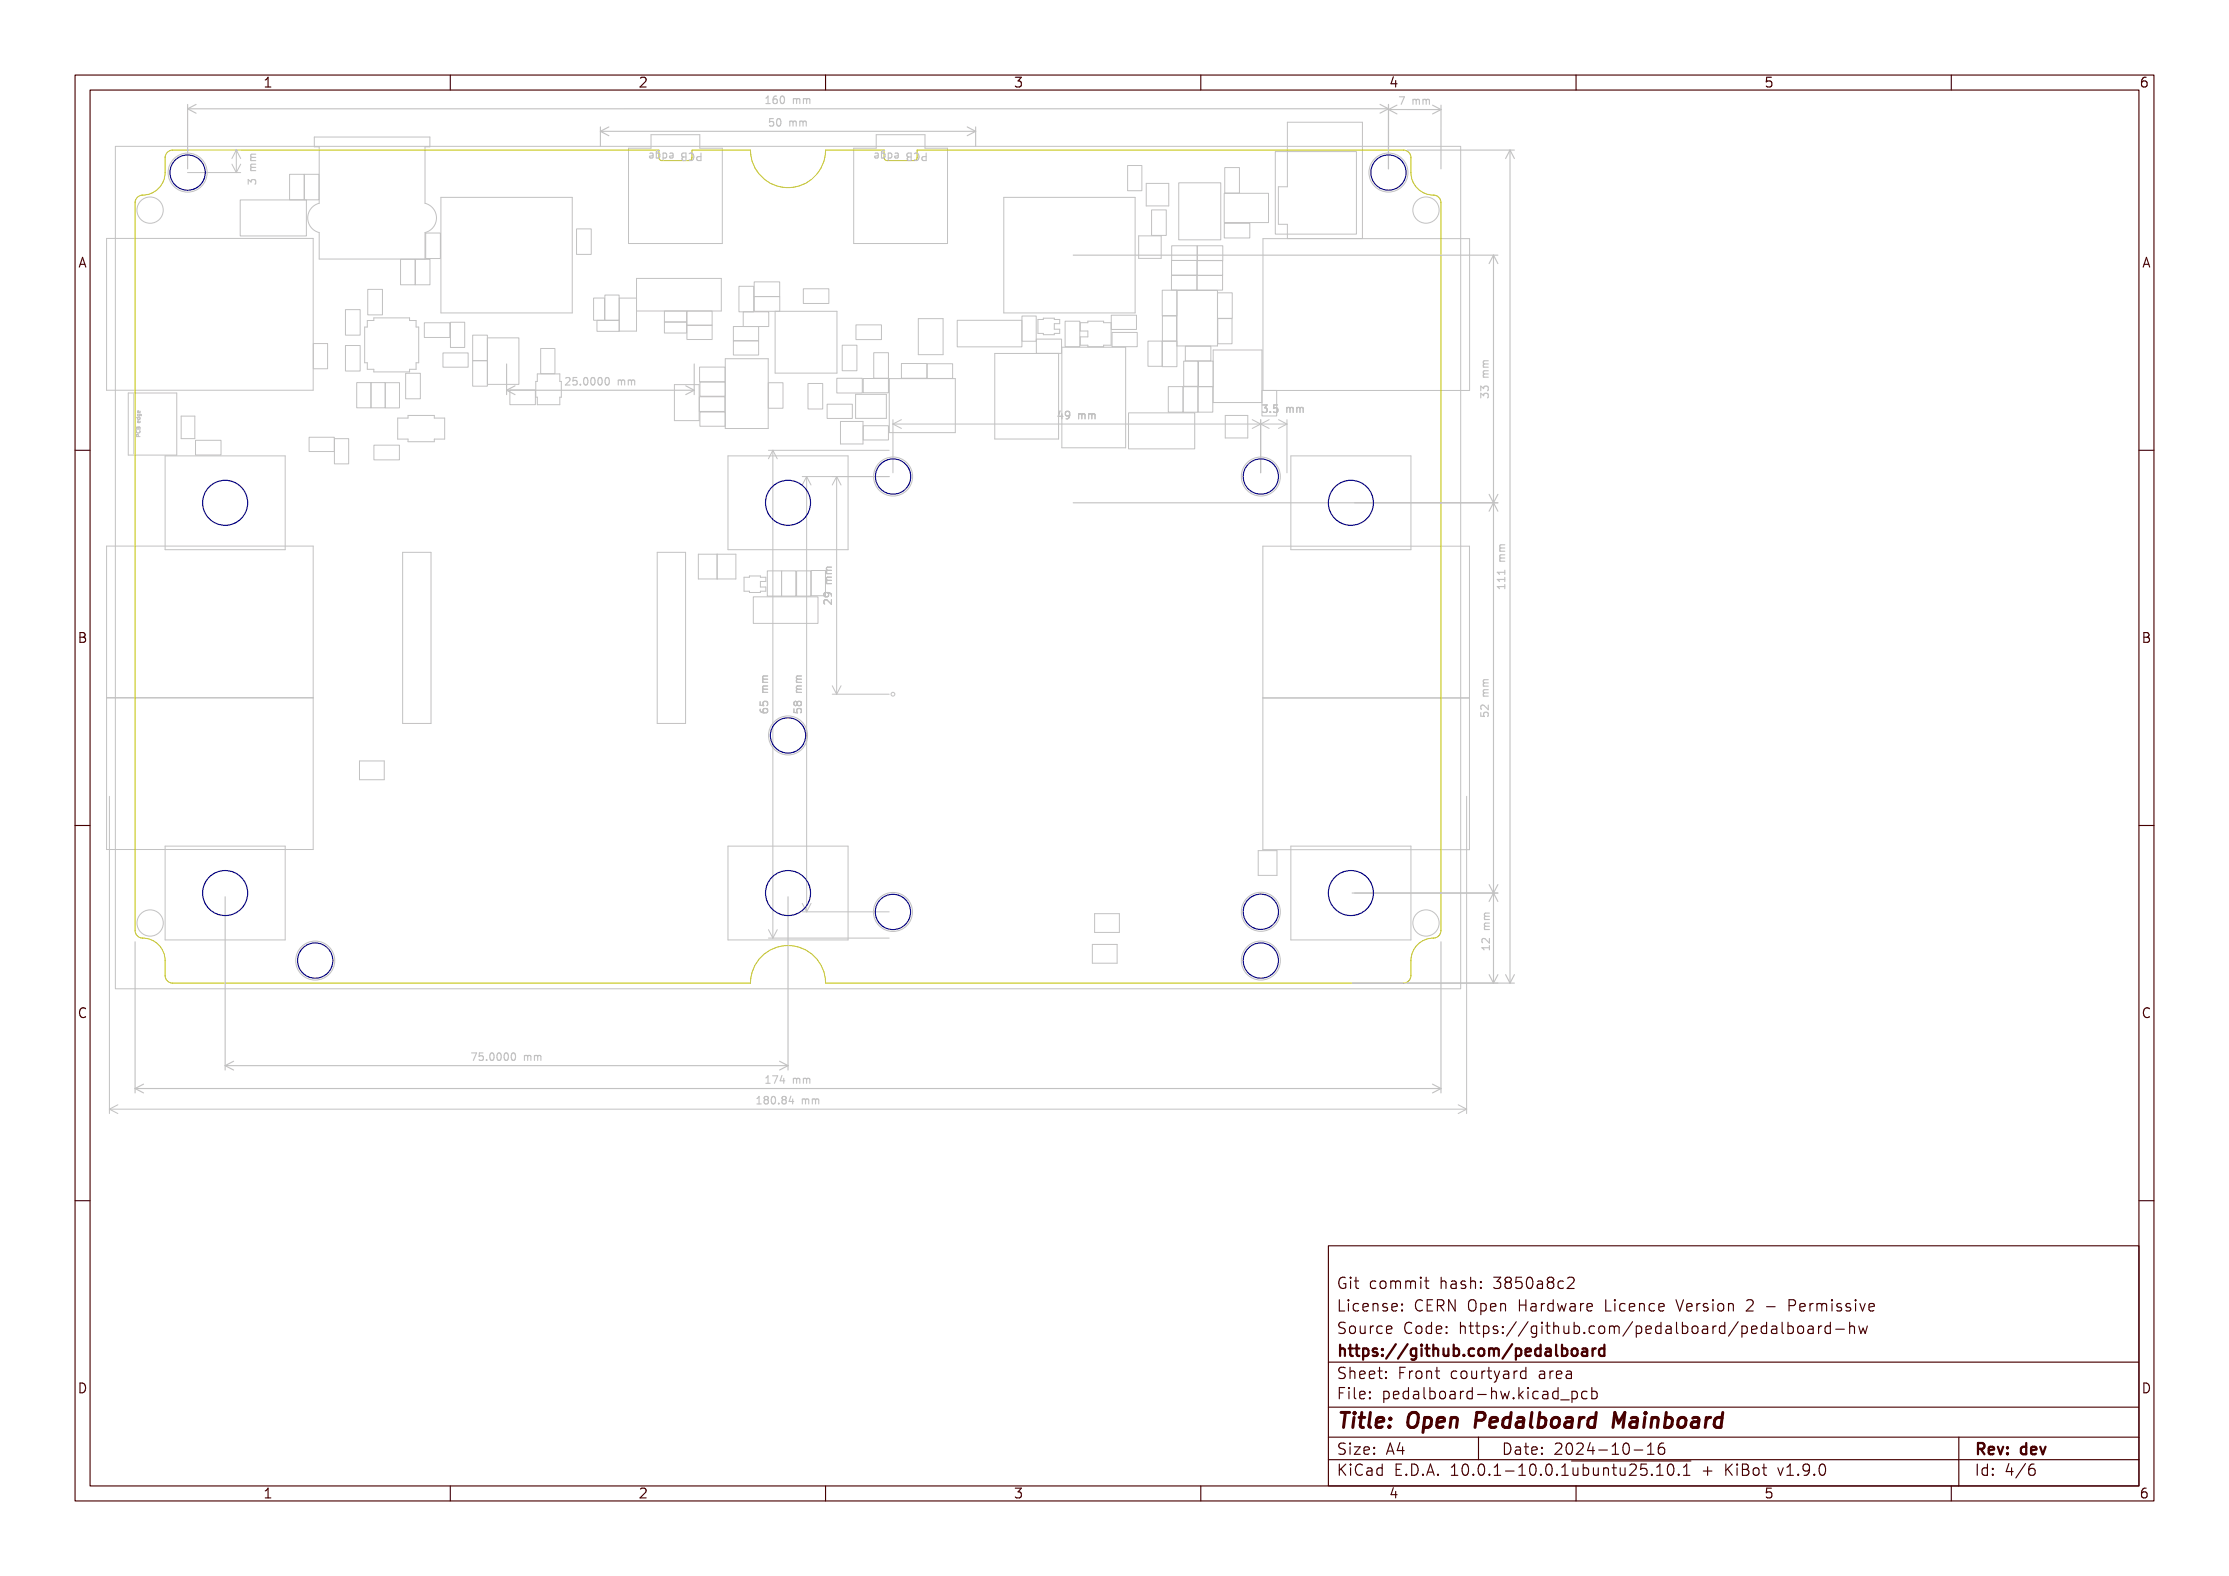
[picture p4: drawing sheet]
<svg xmlns="http://www.w3.org/2000/svg" width="297mm" height="210mm" viewBox="0 0 297 210" stroke-linecap="round" stroke-linejoin="round" font-family="sans-serif">
<defs><g id="words">
<text font-size="2.7" fill="#fff" x="178" y="190.3">Title: Open Pedalboard Mainboard</text>
<g font-size="2" fill="#fff">
<text x="178" y="171.8">Git commit hash: 3850a8c2</text>
<text x="178" y="174.8">License: CERN Open Hardware Licence Version 2 - Permissive</text>
<text x="178" y="177.8">Source Code: https://github.com/pedalboard/pedalboard-hw</text>
<text x="178" y="180.8">https://github.com/pedalboard</text>
<text x="178" y="183.8">Sheet: Front courtyard area</text>
<text x="178" y="186.5">File: pedalboard-hw.kicad_pcb</text>
<text x="178" y="193.9">Size: A4</text>
<text x="178" y="196.7">KiCad E.D.A. 10.0.1-10.0.1~{ubuntu25.10.1} + KiBot v1.9.0</text>
<text x="200" y="193.9">Date: 2024-10-16</text>
<text x="263" y="196.7">Id: 4/6</text>
<text x="263" y="193.9">Rev: dev</text>
</g>
<g font-size="1.7" fill="#fff">
<text x="35" y="11.6">1</text>
<text x="85" y="11.6">2</text>
<text x="135" y="11.6">3</text>
<text x="185" y="11.6">4</text>
<text x="235" y="11.6">5</text>
<text x="285" y="11.6">6</text>
<text x="10.5" y="35.6">A</text>
<text x="285.5" y="35.6">A</text>
<text x="10.5" y="85.6">B</text>
<text x="285.5" y="85.6">B</text>
<text x="10.5" y="135.6">C</text>
<text x="285.5" y="135.6">C</text>
<text x="10.5" y="185.6">D</text>
<text x="285.5" y="185.6">D</text>
<text x="35" y="199.7">1</text>
<text x="85" y="199.7">2</text>
<text x="135" y="199.7">3</text>
<text x="185" y="199.7">4</text>
<text x="235" y="199.7">5</text>
<text x="285" y="199.7">6</text>
</g>
<g font-size="1.3" fill="#fff">
<text x="102.6" y="13.8">160 mm</text>
<text x="103" y="16.8">50 mm</text>
<text x="186.9" y="13.9">7 mm</text>
<text x="93.2" y="20.4" transform="rotate(180 93.2 20.4)">PCB edge</text>
<text x="123.2" y="20.4" transform="rotate(180 123.2 20.4)">PCB edge</text>
<text x="34.1" y="24.1" transform="rotate(-90 34.1 24.1)">3 mm</text>
<text x="76" y="51.3">25.0000 mm</text>
<text x="198.3" y="52.5" transform="rotate(-90 198.3 52.5)">33 mm</text>
<text x="141.5" y="55.9">49 mm</text>
<text x="168.6" y="55">3.5 mm</text>
<text x="200.5" y="77.9" transform="rotate(-90 200.5 77.9)">111 mm</text>
<text x="110.8" y="80" transform="rotate(-90 110.8 80)">29 mm</text>
<text x="102.3" y="94.5" transform="rotate(-90 102.3 94.5)">65 mm</text>
<text x="106.8" y="94.5" transform="rotate(-90 106.8 94.5)">58 mm</text>
<text x="198.3" y="95" transform="rotate(-90 198.3 95)">52 mm</text>
<text x="198.5" y="126.1" transform="rotate(-90 198.5 126.1)">12 mm</text>
<text x="63.5" y="141.3">75.0000 mm</text>
<text x="101.4" y="147.1">180.84 mm</text>
<text x="102.6" y="144.4">174 mm</text>
</g>
<text font-size=".7" fill="#fff" x="18.7" y="58.1" transform="rotate(-90 18.7 58.1)">PCB edge</text>
</g></defs>
<g fill="none" stroke="#c2c2c2" stroke-width=".13">
<path d="M15.4 19.5h179.2v112.3h-179.2zM25 20h7.1M31.5 20v3M31.5 20l.6 1.1M31.5 20l-.6 1.1M41.9 18.3h15.4v1.3h-.7v7.5a2.01 2.01 0 0 1 1.6 1.9 2.01 2.01 0 0 1-1.6 2v3.5h-14.1v-3.5a2.01 2.01 0 0 1-1.5-2 2.01 2.01 0 0 1 1.5-1.9v-7.5h-.6zM83.7 19.7h3v-1.7h6.5v1.7h3v12.7h-12.5zM113.8 19.7h3v-1.7h6.5v1.7h3v12.7h-12.5zM171.5 16.3h10v15.5h-10v-1.9h-1.2v-5h1.2zM14.2 31.8h27.5v20.2h-27.5zM25 23h7.1M30.9 21.9l.6 1.1"/>
<path d="M32 26.6h8.8v4.8h-8.8zM32.1 21.9l-.6 1.1M38.6 23.2h1.9v3.4h-1.9zM40.5 23.2h2v3.4h-2zM49 38.6h2v3.4h-2zM53.4 34.6h1.9v3.4h-1.9zM55.3 34.6h2v3.4h-2zM56.7 31.1h2v3.3h-2zM58.7 26.3h17.5v15.4h-17.5zM76.8 30.5h2v3.4h-2zM79.1 39.7h1.5v3h-1.5zM80.6 39.3h1.9v3.4h-1.9z"/>
<path d="M84.8 39.7h-2.3v4.4h2.3v-7h11.3v4.3h-11.3M98.5 38.1h1.9v3.5h-1.9zM100.5 37.6h3.4v1.9h-3.4zM100.5 39.5h3.4v2h-3.4zM107 38.5h3.4v1.9h-3.4zM133.7 26.3h17.5v15.4h-17.5zM150.2 22.1h1.9v3.3h-1.9zM151.7 31.4h3v3h-3zM152.7 24.4h3v3h-3zM153.4 28h2v3.4h-2zM154.9 38.7h1.9v3.4h-1.9zM156.1 36.7h3.4v1.9h-3.4z"/>
<path d="M156.1 34.7h3.4v2h-3.4zM156.1 32.8h3.4v1.9h-3.4zM156.8 38.7h5.4v7.4h-5.4zM157.1 24.4h5.6v7.6h-5.6zM159.5 36.7h3.4v2h-3.4zM159.5 34.7h3.4v2h-3.4zM159.5 32.8h3.4v1.9h-3.4zM162.2 39h2v3.4h-2zM163.1 25.8h5.9v3.9h-5.9zM163.1 29.8h3.4v1.9h-3.4zM163.2 22.3h1.9v3.4h-1.9zM168.3 31.8h27.5v20.2h-27.5z"/>
<path d="M169.9 20.2h10.8v11h-10.8zM17.1 52.4h6.5v8.2h-6.5zM17.8 52.5v8M18.2 55.7h.4v.1l-.2 .1v-.2M18.2 56.9l.2 .1 .1-.1h.1l.1 .3h-.5zM18.2 57.4a.22 .22 0 0 0 .2 .3 .22 .22 0 0 0 .2-.3M18.3 55.2h.4l.1 .2M18.4 55.2v.2h.2v-.2M18.4 57.9h-.2v.3h.5M18.4 57.9h.1M18.4 57.9v.3M18.4 57v.2"/>
<path d="M18.6 54.8v.2h-.2v-.2v-.1l.1 .3M18.6 56.1v.2h-.2v-.2l.1 .2M24.1 55.4h1.9v3h-1.9zM26.1 58.7h3.4v1.9h-3.4zM41.2 58.3h3.3v1.9h-3.3zM41.8 45.8h1.8v3.3h-1.8zM44.6 58.5h1.9v3.3h-1.9zM46 41.3h2v3.4h-2zM46 46h2v3.4h-2zM47.5 51h1.9v3.3h-1.9zM48.9 42.7h.9v-.3h4.8v.3h.8v.9h.4v4.7h-.4v.9h-.8v.4h-4.8v-.4h-.9v-.9h-.3v-4.7h.3zM49.4 51h1.9v3.3h-1.9z"/>
<path d="M49.8 59.3h3.4v2h-3.4zM51.3 51h1.9v3.4h-1.9zM53 55.7h1.4v-.3h3.5v.3h1.4v2.8h-1.4v.4h-3.5v-.4h-1.4zM54 49.7h2v3.4h-2zM56.5 43h3.4v2h-3.4zM59 47h3.4v1.9h-3.4zM60 42.9h1.9v3.4h-1.9zM63 44.7h1.9v3.4h-1.9zM63 48.1h1.9v3.4h-1.9zM64.9 45h4.2v6.2h-4.2zM67.9 52h3.4v1.9h-3.4zM71.6 49.8h3v1h.2v2.1h-.2v1h-3v-1h-.2v-2.1h.2z"/>
<path d="M72 46.4h1.9v3.4h-1.9zM79.5 42.7h3v1.5h-3zM88.5 42.9h3v1.5h-3zM88.5 41.4h3v1.5h-3zM89.9 51.3h3.3v4.8h-3.3zM91.5 41.4h3.4v1.9h-3.4zM91.5 43.3h3.4v1.9h-3.4zM93.2 52.9h3.4v1.9h-3.4zM93.2 48.9h3.4v2h-3.4zM93.3 54.9h3.3v1.9h-3.3zM93.3 50.9h3.3v1.9h-3.3zM96.6 47.8h5.8v9.3h-5.8z"/>
<path d="M97.7 43.5h3.4v1.9h-3.4zM97.7 45.4h3.4v1.9h-3.4zM99 41.6h3.4v1.9h-3.4zM102.4 51h1.9v3.4h-1.9zM103.3 41.5h8.2v8.2h-8.2zM107.7 51.1h1.9v3.4h-1.9zM110.2 53.9h3.4v1.9h-3.4zM111.5 50.4h3.4v2h-3.4zM112 56.2h3v3h-3zM112.2 46h2v3.4h-2zM114 52.5h4.1v3.2h-4.1zM114.1 43.3h3.4v2h-3.4z"/>
<path d="M115 56.7h3.4v1.9h-3.4zM115 50.4h3.4v1.9h-3.4zM116.4 47h2v3.4h-2zM118.5 50.5h8.8v7.2h-8.8zM119 55.9v7.1M119 56.5h52.5M119 56.5l1.1 .6M120.1 55.9l-1.1 .6M120.1 48.4h3.4v2h-3.4zM122.4 42.5h3.3v4.8h-3.3zM123.5 48.5h3.4v1.9h-3.4zM127.5 42.7h8.7v3.5h-8.7z"/>
<path d="M132.5 47.1h8.6v11.4h-8.6zM136.2 42.1h1.9v3.4h-1.9zM138.1 45.2h3.3v1.9h-3.3zM138.3 42.6h.7v-.2h1.5v.2h.7v.5h-.7v.8h.7v.5h-.7v.2h-1.5v-.2h-.7zM141.5 46.3h8.5v13.4h-8.5zM141.9 42.8h2v3.4h-2zM143.9 43h1.1v-.2h2.1v.2h.9v3h-.9v.2h-2.1v-.2h-1.1v-1.1h1.1v-.8h-1.1zM148.1 42h3.3v1.9h-3.3zM148.2 44.3h3.3v1.9h-3.3zM150.4 55h8.8v4.8h-8.8zM153 45.5h1.9v3.3h-1.9zM154.9 45.5h1.9v3.4h-1.9z"/>
<path d="M154.9 42.1h1.9v3.4h-1.9zM155.7 51.5h1.9v3.4h-1.9zM157.7 51.5h1.9v3.4h-1.9zM157.7 48.1h1.9v3.4h-1.9zM157.9 46.1h3.4v2h-3.4zM159.6 51.5h2v3.4h-2zM159.7 48.1h1.9v3.4h-1.9zM161.6 46.6h6.5v7h-6.5zM162.3 42.5h1.9v3.3h-1.9zM163.3 55.4h3v3h-3zM166.9 55.9l2.2 1.2M168 55.9v7.1"/>
<path d="M168.1 52h2v3.4h-2zM169.1 55.9l-2.2 1.2M170.4 55.9l1.1 .6M171.5 55.9v7.1M171.5 56.5l-1.1 .6M14.2 72.8h27.5v40.4h-27.5zM22 60.7h16v12.5h-16zM53.6 73.6h3.8v22.8h-3.8zM87.6 73.6h3.8v22.8h-3.8zM93.1 73.9h5v3.2h-5zM95.6 73.9v3.2M97 60.7h16v12.5h-16z"/>
<path d="M99.1 76.9h.8v-.1h1.4v.1h.7v.6h-.7v.7h.7v.6h-.7v.2h-1.4v-.2h-.8zM100.4 79.5h8.6v3.6h-8.6zM102.2 76.1h1.9v3.3h-1.9zM102.4 60h16.1M103 60v65M103 60l.6 1.1M103 60l-.6 1.1M104.1 76.1h1.9v3.3h-1.9zM106.1 76.1h1.9v3.3h-1.9zM106.9 63.5h11.6M107.5 63.5v58M107.5 63.5l.6 1.1"/>
<path d="M107.5 63.5l-.6 1.1M108.1 76h1.9v3.4h-1.9zM111.5 63.5v29M111.5 63.5l.6 1.1M111.5 63.5l-.6 1.1M168.3 72.8h27.5v40.4h-27.5zM172 60.7h16v12.5h-16zM14.2 93h27.5M110.9 92.5h7.6M110.9 91.4l.6 1.1M112.1 91.4l-.6 1.1M168.3 93h27.5"/>
<path d="M14.6 106.1v42.3M22 112.7h16v12.5h-16zM47.9 101.4h3.3v2.5h-3.3zM97 112.7h16v12.5h-16zM167.6 113.4h2.6v3.2h-2.6zM172 112.7h16v12.5h-16zM195.4 106.1v42.3M102.4 125h16.1M102.4 123.9l.6 1.1M103.6 123.9l-.6 1.1M106.9 121.5h11.6M106.9 120.4l.6 1.1"/>
<path d="M108.1 120.4l-.6 1.1M145.5 125.8h3.4v2.6h-3.4zM145.9 121.7h3.3v2.5h-3.3zM14.6 147.8h180.8M14.6 147.8l1.1 .6M15.7 147.2l-1.1 .6M194.3 147.2l1.1 .6M195.4 147.8l-1.1 .6"/>
<circle cx="20" cy="28" r="1.75"/>
<circle cx="25" cy="23" r="2.6"/>
<circle cx="185" cy="23" r="2.6"/>
<circle cx="190" cy="28" r="1.75"/>
<circle cx="119" cy="63.5" r="2.6"/>
<circle cx="168" cy="63.5" r="2.6"/>
<circle cx="105" cy="98" r="2.6"/>
<circle cx="119" cy="92.5" r=".25"/>
<circle cx="20" cy="123" r="1.75"/>
<circle cx="42" cy="128" r="2.6"/>
<circle cx="119" cy="121.5" r="2.6"/>
<circle cx="168" cy="121.5" r="2.6"/>
<circle cx="168" cy="128" r="2.6"/>
<circle cx="190" cy="123" r="1.75"/>
</g>
<path d="M22.3 20.3l.3-.2 .4-.1h64.8v1l.2 .3 3.8 .1 .3-.2 .1-1.2h7.8a5 5 0 0 0 5 5 5 5 0 0 0 5-5h7.8l.1 1.2 .3 .2 3.8-.1 .2-.3v-1h64.8a1 1 0 0 1 1 1v2a3 3 0 0 0 3 3 1 1 0 0 1 1 1v97a1 1 0 0 1-1 1 3 3 0 0 0-3 3v2a1 1 0 0 1-1 1h-77a5 5 0 0 0-5-5 5 5 0 0 0-5 5h-77a1 1 0 0 1-1-1v-2a3 3 0 0 0-3-3 1 1 0 0 1-1-1v-97a1 1 0 0 1 1-1 3 3 0 0 0 3-3v-2l.1-.4z" fill="none" stroke="#c2c200" stroke-width=".13"/>
<g fill="none" stroke="#c2c2c2" stroke-width=".15">
<path d="M25 13.9v8.6M25 14.5l1.1 .6M26.1 13.9l-1.1 .6M80 16.9v2.6M80 17.5h50M80 17.5l1.1 .6M81.1 16.9l-1.1 .6M102.1 13.1l.2-.3v1M102.1 13.8h.5M103 15.8h-.4l-.1 .5 .2-.1h.3l.1 .2-.1 .3-.1 .1-.4-.1M103.5 12.8l-.3 .1a.67 .67 0 0 0 0 .9l.3-.1 .1-.3-.2-.2h-.2l-.2 .2M103.6 15.9l.1-.1a.53 .53 0 0 1 .4 .5 .53 .53 0 0 1-.4 .5l-.1-.1-.1-.3z"/>
<path d="M104.1 12.9l.1-.1a.53 .53 0 0 1 .3 .5 .53 .53 0 0 1-.3 .5l-.1-.1-.1-.3zM105.2 16.1v.7M105.2 16.2l.3-.1 .2 .2M105.7 16.3l.1-.2 .2 .1 .1 .6M105.7 16.3v.5M105.7 13.1v.7M105.7 13.2l.3-.1 .1 .2M106.1 13.3l.2-.2 .2 .1 .1 .6M106.1 13.3v.5M106.6 16.2l.3-.1 .1 .2M106.6 16.1v.7M107 16.3l.1-.2 .3 .1v.6"/>
<path d="M107 16.3v.5M107.1 13.1v.7M107.1 13.2l.2-.1 .2 .2M107.5 13.3l.1-.2 .3 .1v.6M107.5 13.3v.5M128.9 16.9l1.1 .6M130 16.9v2.6M130 17.5l-1.1 .6M183.9 13.9l1.1 .6M185 13.9v8.6M185 14.5h-160M185 14.5l-1.1 .6"/>
<path d="M185 14.6h7M185 14.6l1.1 .6M186.1 14l-1.1 .6M186.5 12.9h.6l-.4 1M187.5 20h14.3M188.3 13.2v.7M188.3 13.3l.3-.1 .1 .2M188.7 13.4v.5M188.7 13.4l.1-.2 .3 .1v.6M189.6 13.3l.3-.1 .1 .2M189.6 13.2v.7M190 13.4l.2-.2 .2 .1 .1 .6"/>
<path d="M190 13.4v.5M190.9 14l1.1 .6M192 14.6l-1.1 .6M192 14v8.5M201.2 20v111M201.2 20l.6 1.1M201.2 20l-.6 1.1M33.1 24.5v-.6l.4 .4v-.3h.5l.1 .1-.1 .4M33.4 22.7h.7M33.4 21.4h.7M33.5 22.3l-.1 .1 .1 .3M33.5 21l-.1 .1 .1 .3"/>
<path d="M33.5 22.3h.6M33.5 21h.6M34.1 20.5l-.6 .1-.1 .2 .1 .2M34.1 21.9h-.6l-.1 .3 .1 .1M86.6 20.4h.3l.1 .1v.5h-.4l-.1-.2 .5-.1M87.4 20.4h.3l.2 .2-.1 .4h-.4M87.9 20.1h-.3l-.2 .2v.8M88.4 20.4h.2l.2 .2-.1 .4h-.3M88.4 20.4v1M89.3 20.4h.2l.2 .1-.1 .5h-.3l-.1-.2 .5-.1M90.9 20.4h.5v1l-.5-.1v-.2l.2-.2-.3-.2zM91.1 20.9h.3"/>
<path d="M91.8 20.5a.47 .47 0 0 1 .7 .3 .47 .47 0 0 1-.5 .6l-.2-.1M93.4 20.4v1h-.4l-.1-.1-.1-.2 .1-.2h.5M116.6 20.4h.3l.1 .1v.5h-.4l-.1-.2 .5-.1M117.5 20.4h.2l.2 .2-.1 .4h-.3M117.9 20.1h-.3l-.1 .2v.8M118.4 20.4h.2l.2 .2-.1 .4h-.3M118.4 20.4v1M119.3 20.4h.2l.2 .1-.1 .5h-.3l-.1-.2 .5-.1M120.9 20.4h.5v1l-.5-.1v-.2l.2-.2-.3-.2zM121.1 20.9h.3M121.8 20.5a.47 .47 0 0 1 .7 .3 .47 .47 0 0 1-.5 .6l-.2-.1M123.4 20.4v1h-.4l-.1-.1-.1-.2 .1-.2h.5"/>
<path d="M143 34h56.6M199 34v97M199 34l.6 1.1M199 34l-.6 1.1M67.5 48.5v4.1M67.5 52h25M67.5 52l1.1 .6M68.6 51.4l-1.1 .6M75.4 50.4l.4-.1 .2 .3-.7 .7h.7M76.9 50.3h-.5l-.1 .5 .2-.1h.3l.1 .2v.3l-.2 .1-.4-.1M77.3 51.2v.1M77.9 50.4l.1-.1a.53 .53 0 0 1 .3 .5 .53 .53 0 0 1-.3 .5 .66 .66 0 0 1-.1-.9z"/>
<path d="M78.9 50.4l.1-.1a.53 .53 0 0 1 .3 .5 .53 .53 0 0 1-.3 .5 .67 .67 0 0 1-.1-.9zM79.8 50.4l.1-.1a.53 .53 0 0 1 .4 .5 .53 .53 0 0 1-.4 .5 .67 .67 0 0 1-.1-.9zM80.8 50.4l.1-.1a.53 .53 0 0 1 .3 .5 .53 .53 0 0 1-.3 .5 .66 .66 0 0 1-.1-.9zM82.4 50.6v.7M82.4 50.7l.3-.1 .1 .2M82.8 50.8l.2-.2 .2 .1v.6M82.8 50.8v.5M83.7 50.7l.3-.1 .1 .2M83.7 50.6v.7M84.1 50.8l.2-.2 .2 .1 .1 .6M84.1 50.8v.5M91.4 51.4l1.1 .6"/>
<path d="M92.5 48.5v4.1M92.5 52l-1.1 .6M141.2 54.8l-.2 .7h.6M141.5 55.1v.7M142.5 55.2l-.2 .2h-.2l-.1-.2 .1-.3 .2-.1 .2 .1a.66 .66 0 0 1-.3 .9h-.1M143.7 55.1v.7M143.7 55.2l.3-.1 .1 .2M144.1 55.3l.2-.2 .2 .1 .1 .6M144.1 55.3v.5M145.1 55.2l.2-.1 .2 .2M145.1 55.1v.7M145.5 55.3l.1-.2 .3 .1v.6"/>
<path d="M145.5 55.3v.5M168.2 54h.6l-.3 .3 .3 .1v.5l-.2 .1-.4-.1M169.3 54.9v.1M170.2 54h-.5v.4l.1-.1 .4 .1 .1 .1-.1 .4-.1 .1-.4-.1M171.5 54.3v.7M171.5 54.4l.2-.1 .2 .1M171.9 54.4l.1-.1h.3v.7M171.9 54.4v.6M172.8 54.4l.3-.1 .1 .1M172.8 54.3v.7M173.2 54.4l.2-.1h.2v.7M173.2 54.4v.6"/>
<path d="M197.3 52.1v-.6l.4 .3 .1-.3h.4l.1 .1-.1 .5M197.3 53v-.6l.4 .3 .1-.2h.4l.1 .1-.1 .4M197.6 50.3h.7M197.6 48.9h.7M197.8 49.8l-.2 .2 .1 .3M197.8 48.5l-.2 .1 .1 .3M197.8 49.8h.5M197.8 48.5h.5M198.3 48.1h-.6l-.1 .3 .2 .1M198.3 49.4l-.6 .1-.1 .2 .2 .1M110.1 77.8h.7M110.1 76.4h.7"/>
<path d="M110.2 79l.2 .1v.2l-.2 .2-.4-.1v-.3l.1-.1a.66 .66 0 0 1 .9 .2v.2M110.3 77.3l-.2 .2 .1 .3M110.3 76l-.2 .1 .1 .3M110.3 77.3h.5M110.3 76h.5M110.8 79.9v.6l-.7-.6-.3 .2 .1 .4M110.8 75.6h-.6l-.1 .3 .2 .1M110.8 76.9l-.6 .1-.1 .2 .2 .1M143 67h56.6M198.4 65.9l1.2 2.2M199.6 65.9l-1.2 2.2M199.8 74.8h.7"/>
<path d="M199.8 73.5h.7M200 74.4l-.2 .1 .1 .3M200 73l-.2 .2 .1 .3M200 74.4h.5M200 73h.5M200.5 76v.5M200.5 76.9v.6M200.5 77.9v.6M200.5 78.2h-1l.3 .3M200.5 77.2h-1l.3 .3M200.5 76.3h-1l.3 .2M200.5 72.6h-.6l-.1 .3 .2 .1"/>
<path d="M200.5 73.9l-.6 .1-.1 .2 .2 .2M101.3 94.5v.3a.67 .67 0 0 0 1 0l-.1-.3-.3-.1-.2 .2v.3l.2 .1M101.3 93.5v.5h.5l-.1-.1v-.3l.2-.1h.3l.1 .1-.1 .4M101.6 92.3h.7M101.6 90.9h.7M101.8 91.8h.5M101.8 90.5h.5M101.8 91.8l-.2 .2 .1 .3M101.8 90.5l-.2 .1 .1 .3M102.3 91.4l-.6 .1-.1 .2 .2 .1M102.3 90.1h-.6l-.1 .3 .2 .1M105.8 94.5v.4l.5 .1-.1-.2v-.3l.2-.1 .3 .1 .1 .1-.1 .4"/>
<path d="M106.1 92.3h.7M106.1 90.9h.7M106.2 93.6l-.2-.1-.2 .1v.3l.2 .1 .2-.2M106.2 93.6l.2-.1h.3l.1 .1-.1 .3-.1 .1h-.3l-.1-.2M106.2 93.6v.2M106.3 90.5l-.2 .1 .1 .3M106.3 91.8l-.2 .2 .1 .3M106.3 91.8h.5M106.3 90.5h.5M106.8 90.1h-.6l-.1 .3 .2 .1M106.8 91.4l-.6 .1-.1 .2 .2 .1M197.3 95v.4l.5 .1-.1-.2v-.3l.2-.1 .3 .1 .1 .1-.1 .4"/>
<path d="M197.6 92.8h.7M197.6 91.4h.7M197.8 91l-.2 .1 .1 .3M197.8 92.3l-.2 .2 .1 .3M197.8 92.3h.5M197.8 91h.5M198.3 94v.6l-.7-.6-.3 .1 .1 .4M198.3 90.6h-.6l-.1 .3 .2 .1M198.3 91.9l-.6 .1-.1 .2 .2 .1M30 119.5v23.1M105 119.5v23.1M180.2 119h19.4"/>
<path d="M198.4 117.9l1.2 2.2M199.6 117.9l-1.2 2.2M18 125.5v20.1M180.2 131h21.6M192 125.5v20.1M197.8 123.9h.7M197.8 122.5h.7M197.9 123.4l-.1 .2 .1 .3M197.9 122.1l-.1 .1 .1 .3M197.9 123.4h.6M197.9 122.1h.6M198.4 129.9l.6 1.1"/>
<path d="M198.5 125.1v.6l-.8-.6h-.2v.1v.4M198.5 126v.6M198.5 126.3h-1l.2 .3M198.5 121.7h-.7v.3l.1 .1M198.5 123l-.7 .1v.2l.1 .1M199.6 129.9l-.6 1.1M200.6 129.9l.6 1.1M201.8 129.9l-.6 1.1M18 145h174M18 145l1.1 .6M19.1 144.5l-1.1 .5M30 142h75"/>
<path d="M30 142l1.1 .6M31.1 141.4l-1.1 .6M62.8 140.3h.7l-.4 1M64.4 140.3h-.5l-.1 .5 .2-.1h.3l.1 .2v.3l-.2 .1-.4-.1M64.8 141.2v.1M65.4 140.4l.1-.1a.53 .53 0 0 1 .3 .5 .53 .53 0 0 1-.3 .5 .67 .67 0 0 1-.1-.9zM66.4 140.4l.1-.1a.53 .53 0 0 1 .3 .5 .53 .53 0 0 1-.3 .5 .67 .67 0 0 1-.1-.9zM67.3 140.4l.1-.1a.53 .53 0 0 1 .4 .5 .53 .53 0 0 1-.4 .5 .67 .67 0 0 1-.1-.9zM68.2 140.4l.2-.1a.53 .53 0 0 1 .3 .5 .53 .53 0 0 1-.3 .5l-.2-.1-.1-.3zM69.9 140.6v.7M69.9 140.7l.3-.1 .1 .2M70.3 140.8l.2-.2 .2 .1v.6"/>
<path d="M70.3 140.8v.5M71.2 140.7l.3-.1 .1 .2M71.2 140.6v.7M71.6 140.8l.2-.2 .2 .1 .1 .6M71.6 140.8v.5M100.9 147.1h.5M100.9 146.4l.2-.3v1M102 146.5l-.2 .2v.2l.2 .2h.3l.1-.2v-.2l-.2-.2M102 146.5l-.2-.2 .2-.2 .3 .1 .1 .1-.2 .2M102 146.5h.2M102 144.4h.6M102 143.6l.3-.2v1"/>
<path d="M102.9 146.2l.1-.1a.53 .53 0 0 1 .3 .5 .53 .53 0 0 1-.3 .5l-.1-.1-.1-.3zM103 143.4h.6l-.4 1M103.8 147v.1M103.9 141.4l1.1 .6M104.2 143.3l-.2 .7h.6M104.4 146.5l-.2 .2v.3l.2 .1h.3l.1-.2-.1-.3-.1-.1M104.4 146.5l-.2-.2 .2-.2 .3 .1 .1 .1-.2 .2M104.4 146.5h.2M104.4 143.7v.7M105 142l-1.1 .6M105.4 146.1l-.3 .7h.7M105.6 146.4v.7"/>
<path d="M105.7 143.7v.7M105.7 143.8l.3-.1 .1 .1M106.1 143.8l.2-.1h.2l.1 .7M106.1 143.8v.6M106.9 146.4v.7M106.9 146.5l.3-.1 .1 .2M107 143.8l.3-.1 .2 .1M107 143.7v.7M107.3 146.6l.2-.2 .2 .1 .1 .6M107.3 146.6v.5M107.5 143.8l.1-.1h.3v.7M107.5 143.8v.6"/>
<path d="M108.2 146.5l.3-.1 .2 .2M108.2 146.4v.7M108.7 146.6l.1-.2 .2 .1 .1 .6M108.7 146.6v.5M190.9 144.5l1.1 .5M192 145l-1.1 .6"/>
</g>
<g fill="none" stroke="#000084" stroke-width=".15">
<circle cx="25" cy="23" r="2.35"/>
<circle cx="185" cy="23" r="2.35"/>
<circle cx="30" cy="67" r="3"/>
<circle cx="105" cy="67" r="3"/>
<circle cx="119" cy="63.5" r="2.35"/>
<circle cx="168" cy="63.5" r="2.35"/>
<circle cx="180" cy="67" r="3"/>
<circle cx="105" cy="98" r="2.35"/>
<circle cx="30" cy="119" r="3"/>
<circle cx="105" cy="119" r="3"/>
<circle cx="180" cy="119" r="3"/>
<circle cx="42" cy="128" r="2.35"/>
<circle cx="119" cy="121.5" r="2.35"/>
<circle cx="168" cy="121.5" r="2.35"/>
<circle cx="168" cy="128" r="2.35"/>
</g>
<g fill="none" stroke="#480000" stroke-width=".15">
<path d="M10 10h277v190h-277zM12 12h273v186h-273zM35.3 11.6h.8M35.3 10.7l.4-.4v1.3M60 10v2M85.3 10.4l.2-.1 .5 .1a.35 .35 0 0 1 0 .5l-.7 .7h.8M110 10v2M135.3 10.3h.8l-.4 .5a.35 .35 0 0 1 .4 .2v.3l-.1 .2-.5 .1-.2-.1M160 10v2M185.7 10.2l-.4 1h.9M186 10.7v.9M210 10v2"/>
<path d="M236 10.3h-.6l-.1 .6 .2-.1 .5 .1 .1 .1-.1 .5-.2 .1h-.3l-.2-.1M260 10v2M286 10.3a.52 .52 0 0 0-.7 .6v.4l.2 .2 .3 .1 .2-.1 .1-.5-.1-.1-.4-.1-.3 .2M10.6 35.6l.4-1.3 .4 1.3M10.7 35.2h.6M285.6 35.6l.4-1.3 .4 1.3M285.7 35.2h.6M10 60h2M285 60h2M10.7 84.3h.4l.2 .1v.3l-.2 .2a.35 .35 0 0 1 .3 .3 .35 .35 0 0 1-.2 .4h-.5zM10.7 84.9h.4M285.7 84.3h.4l.2 .1v.3l-.2 .2a.35 .35 0 0 1 .3 .3 .35 .35 0 0 1-.2 .4h-.5z"/>
<path d="M285.7 84.9h.4M10 110h2M285 110h2M11.4 134.4a.52 .52 0 0 0-.6 0 .52 .52 0 0 0-.2 .6 .49 .49 0 0 0 .2 .5 .49 .49 0 0 0 .6 0M286.4 134.4a.52 .52 0 0 0-.6 0 .52 .52 0 0 0-.2 .6 .49 .49 0 0 0 .3 .5 .49 .49 0 0 0 .5 0M10 160h2M285 160h2M177 166h108v32h-108zM178.5 173.2v1.5h.7M179.2 176.3l-.5-.1a.36 .36 0 0 0-.3 .4 .36 .36 0 0 0 .3 .3 .55 .55 0 0 1 .5 .4v.3l-.2 .1-.6-.1M179.2 170.3a.62 .62 0 0 0-.7 .1 .62 .62 0 0 0-.1 .7 .56 .56 0 0 0 .3 .5 .56 .56 0 0 0 .6 0v-.5h-.3M179.7 173.2v.1"/>
<path d="M179.7 173.7v1M179.7 173.2l-.1 .1h.1M180 170.2v.1M180 170.7v1M180 176.8a.41 .41 0 0 1 .6 .2v.4a.41 .41 0 0 1-.4 .3 .41 .41 0 0 1-.4-.3v-.4zM180 170.2l-.1 .1h.1M180.5 170.7h.5M180.7 170.2v1.3v.1l.3 .1M181 173.8l-.4-.1-.3 .3v.4l.2 .2 .1 .1 .4-.1M181.2 176.7l.1 .9a.41 .41 0 0 0 .6 0M181.6 174.2l.7-.1-.1-.3-.4-.1-.2 .2 .1 .7 .1 .1 .4-.1M181.9 176.7v1"/>
<path d="M182.6 176.7v1M183 173.8a.37 .37 0 0 1 .6 .1v.8M183 173.7v1M183 176.7l-.3 .1-.1 .2M183.3 170.8l-.4-.1-.3 .3v.4l.1 .2 .2 .1 .4-.1M184 170.8a.41 .41 0 0 1 .4-.1 .41 .41 0 0 1 .3 .3v.4a.41 .41 0 0 1-.4 .3 .41 .41 0 0 1-.4-.3zM184.2 176.8l-.5-.1-.2 .3v.4l.1 .2 .1 .1 .5-.1M184.7 177.2l.8-.1-.1-.3-.4-.1-.3 .2 .1 .7 .2 .1 .4-.1M184.8 173.8l-.3-.1-.3 .2 .1 .2 .5 .2 .1 .1-.1 .2-.1 .1-.5-.1M185.3 170.8a.37 .37 0 0 1 .7 .1M185.3 170.7v1M185.5 174.2l.7-.1-.1-.3-.4-.1-.2 .2v.7l.2 .1 .4-.1"/>
<path d="M186 170.9l.2-.2 .3 .1 .1 .9M186 170.9v.8M186.8 174.6h.1l-.1 .1M186.8 174.6h-.1l.1 .1M186.8 173.8v.1M186.8 174.6v.1M186.8 173.8h.1l-.1 .1M186.8 173.8h-.1l.1 .1M187.3 170.8a.37 .37 0 0 1 .7 .1M187.3 170.7v1M188 170.9l.2-.2 .3 .1 .1 .9M188 170.9v.8"/>
<path d="M188.1 176.3a.6 .6 0 0 0-.7 0 .6 .6 0 0 0-.2 .8 .56 .56 0 0 0 .3 .5 .56 .56 0 0 0 .6 0M188.8 176.8a.41 .41 0 0 1 .7 .2v.4a.41 .41 0 0 1-.4 .3 .41 .41 0 0 1-.4-.3v-.4zM189.3 170.2l-.1 .1h.1M189.3 170.2v.1M189.3 170.7v1M189.3 170.2l.1 .1h-.1M189.5 173.3a.6 .6 0 0 0-.7 0 .6 .6 0 0 0-.2 .8 .56 .56 0 0 0 .3 .5 .56 .56 0 0 0 .6 0M189.8 170.7h.6M190 170.2v1.3l.1 .1 .3 .1M190.2 173.9h.5M190.7 176.2v1.5M190.7 176.8l-.4-.1-.3 .3v.4l.2 .2 .1 .1 .4-.1"/>
<path d="M190.9 173.2h-.7v1.5h.7M191.4 177.2l.7-.1-.1-.3-.4-.1-.2 .2 .1 .7 .1 .1 .4-.1M191.5 174h.6a.41 .41 0 0 0 .3-.4 .41 .41 0 0 0-.3-.4h-.6v1.5M191.9 174l.5 .7M192 170.8a.37 .37 0 0 1 .7 .1v.8M192 170.2v1.5M192.7 177.6h.1l-.1 .1M192.7 177.6v.1M192.7 176.8v.1M192.7 176.8h.1l-.1 .1M193.4 170.8l.1-.1 .5 .1v.9M193.9 173.2v1.5l-.9-1.5v1.5"/>
<path d="M194 171.1h-.5a.29 .29 0 0 0-.2 .3 .29 .29 0 0 0 .2 .3l.5-.1M194.6 176.2v1.5M194.6 176.8a.37 .37 0 0 1 .6 .1v.8M195.2 170.8l-.3-.1-.2 .2v.2l.5 .2 .1 .1-.1 .2-.1 .1-.4-.1M195.7 173.4a.5 .5 0 0 1 .6-.2 .5 .5 0 0 1 .4 .5v.5a.5 .5 0 0 1-.5 .5 .5 .5 0 0 1-.5-.5zM195.7 176.7h.6M196 176.2v1.3v.1l.3 .1M196 170.2v1.5M196 170.8a.37 .37 0 0 1 .6 .1v.8M196.6 176.7h.6M196.8 176.2v1.3l.1 .1 .3 .1M197.3 173.8l.4-.1 .3 .3v.4l-.1 .2-.2 .1-.4-.1"/>
<path d="M197.3 170.8v.1M197.3 171.6v.1M197.3 173.7v1.5M197.3 171.6h.1l-.1 .1M197.3 171.6h-.1l.1 .1M197.3 170.8h.1l-.1 .1M197.3 170.8h-.1l.1 .1M197.7 176.8l.4-.1 .3 .3v.4l-.2 .2-.1 .1-.4-.1M197.7 176.7v1.5M198.6 174.2l.7-.1-.1-.3-.4-.1-.2 .2 .1 .7 .1 .1 .4-.1M199 170.2h1l-.5 .6a.41 .41 0 0 1 .5 .3v.3l-.2 .2-.6 .1-.2-.1M199.5 176.8l-.3-.1-.2 .2v.2l.5 .2 .1 .1-.1 .2-.1 .1-.4-.1"/>
<path d="M200 173.8a.37 .37 0 0 1 .6 .1v.8M200 173.7v1M200.2 177.6h.1l-.1 .1M200.2 177.6v.1M200.2 176.8v.1M200.2 176.8h.1l-.1 .1M200.8 170.8l-.2-.1a.3 .3 0 0 1 0-.3 .3 .3 0 0 1 .2-.2l.4 .1a.31 .31 0 0 1 .2 .3 .31 .31 0 0 1-.3 .2M200.8 170.8l-.3 .3v.3l.3 .3h.3l.3-.3v-.3l-.3-.3M200.8 170.8h.3M202 176.1l-1.3 2M202.5 173.9h.8M202.5 173.2v1.5"/>
<path d="M202.7 170.2h-.7v.7l.2-.1h.5l.1 .3-.1 .5-.2 .1h-.3l-.2-.1M203.3 173.2v1.5M203.5 170.3a.36 .36 0 0 1 .4-.1 .36 .36 0 0 1 .3 .3 .78 .78 0 0 1-.5 1.2 .91 .91 0 0 1-.2-1.4zM203.6 176.1l-1.3 2M204 173.8l.2-.1 .4 .1 .1 .9M204.7 174.1h-.5a.29 .29 0 0 0-.3 .3 .29 .29 0 0 0 .3 .3l.5-.1M204.7 176.8l-.4-.1-.3 .3v.4l.2 .2 .1 .1 .4-.1M204.7 176.7v1.2a.41 .41 0 0 1-.6 .2M204.9 170.8l.1-.1 .5 .1v.9M205.4 173.7v1M205.5 176.2v.1M205.5 176.7v1"/>
<path d="M205.5 176.2l-.1 .1h.1M205.5 171.1h-.5a.29 .29 0 0 0-.2 .3 .29 .29 0 0 0 .2 .3l.5-.1M205.8 173.7l-.3 .1-.1 .2M206 176.7h.5M206.2 176.2v1.3v.1l.3 .1M206.5 170.8l-.3-.1a.3 .3 0 0 1 0-.3 .3 .3 0 0 1 .3-.2l.4 .1a.31 .31 0 0 1 .1 .3 .31 .31 0 0 1-.3 .2M206.5 170.8l-.3 .3v.3l.3 .3h.2l.3-.3v-.3l-.3-.3M206.5 170.8h.2M207 173.8l-.5-.1-.3 .3v.4l.2 .2 .1 .1 .5-.1M207 173.2v1.5M207 176.8a.37 .37 0 0 1 .7 .1v.8M207 176.2v1.5"/>
<path d="M207.5 173.7l.3 1 .3-.7 .3 .7 .3-1M208.3 170.8l-.4-.1-.3 .3v.4l.1 .2 .2 .1 .4-.1M208.4 176.7l.1 .9a.41 .41 0 0 0 .5 0M208.9 170.3l.2-.1 .5 .1a.41 .41 0 0 1 .1 .5l-.9 .9h.9M209 176.7v1M209.2 173.8l.2-.1 .4 .1 .1 .9M209.7 176.8l.5-.1 .3 .3v.4l-.2 .2-.1 .1-.5-.1M209.7 176.2v1.5M209.9 174.1h-.5a.3 .3 0 0 0-.2 .3 .3 .3 0 0 0 .2 .3l.5-.1M210.6 173.7v1M211 173.7l-.3 .1-.1 .2M211.1 177.6h.1l-.1 .1"/>
<path d="M211.1 177.6h-.1l.1 .1M211.1 177.6v.1M211.5 174.2l.7-.1-.1-.3-.4-.1-.2 .2v.7l.2 .1 .4-.1M212.5 176.8l-.5-.1-.3 .3v.4l.2 .2 .1 .1 .5-.1M213.1 176.8a.41 .41 0 0 1 .4-.1 .41 .41 0 0 1 .3 .3v.4a.41 .41 0 0 1-.4 .3 .41 .41 0 0 1-.4-.3zM214 173.2v1.5h.7M214.5 176.8a.37 .37 0 0 1 .6 .1M214.5 176.7v1M215.1 176.9l.2-.2 .4 .1v.9M215.1 176.9v.8M215.2 173.2l-.1 .1h.1M215.2 173.2v.1"/>
<path d="M215.2 173.7v1M216.5 173.8l-.4-.1-.3 .3v.4l.2 .2 .1 .1 .4-.1M217.1 174.2l.7-.1-.1-.3-.4-.1-.2 .2 .1 .7 .1 .1 .4-.1M217.5 176.1l-1.3 2M218 176.7v1.5M218 176.8l.5-.1 .2 .3v.4l-.1 .2-.1 .1-.5-.1M218.5 173.8a.37 .37 0 0 1 .6 .1v.8M218.5 173.7v1M219.3 177.2l.7-.1v-.3l-.5-.1-.2 .2 .1 .7 .1 .1 .5-.1M220.5 173.8l-.5-.1-.3 .3v.4l.2 .2 .1 .1 .5-.1M221 174.2l.7-.1v-.3l-.5-.1-.2 .2 .1 .7 .1 .1 .5-.1M221.3 176.8l-.4-.1-.3 .3v.4l.1 .2 .2 .1 .4-.1"/>
<path d="M221.3 176.2v1.5M222 176.8l.2-.1 .4 .1 .1 .9M222.7 177.1h-.5a.29 .29 0 0 0-.3 .3 .29 .29 0 0 0 .3 .3l.5-.1M223.3 173.2l.5 1.5 .5-1.5M223.4 176.2v1.3l.2 .2M224.2 176.8l.4-.1 .3 .3v.4l-.2 .2-.1 .1-.4-.1M224.2 176.2v1.5M224.7 174.2l.8-.1-.1-.3-.4-.1-.3 .2 .1 .7 .2 .1 .4-.1M225.6 176.8a.41 .41 0 0 1 .6 .2v.4a.41 .41 0 0 1-.3 .3 .41 .41 0 0 1-.4-.3v-.4zM226.1 173.7v1M226.5 173.7l-.3 .1-.1 .2M226.9 176.8l.1-.1 .5 .1v.9"/>
<path d="M227.5 177.1h-.5a.29 .29 0 0 0-.2 .3 .29 .29 0 0 0 .2 .3l.5-.1M227.5 173.8l-.3-.1-.2 .2v.2l.5 .2 .1 .1-.1 .2-.1 .1-.4-.1M228.2 173.2v.1M228.2 173.7v1M228.2 176.7v1M228.2 173.2l.1 .1h-.1M228.7 176.7l-.3 .1-.2 .2M229 173.8a.41 .41 0 0 1 .7 .2v.4a.41 .41 0 0 1-.4 .3 .41 .41 0 0 1-.4-.3v-.4zM229.8 176.8l-.4-.1-.3 .3v.4l.1 .2 .2 .1 .4-.1M229.8 176.2v1.5M230.3 173.8a.37 .37 0 0 1 .7 .1v.8M230.3 173.7v1"/>
<path d="M231.6 176.1l-1.3 2M232.1 176.8l.4-.1 .3 .3v.4l-.1 .2-.2 .1-.4-.1M232.1 176.7v1.5M232.7 173.3l.3-.1 .5 .1a.41 .41 0 0 1 0 .5l-.8 .9h.9M233.4 177.2l.7-.1-.1-.3-.4-.1-.2 .2 .1 .7 .1 .1 .4-.1M235.4 176.8l-.4-.1-.3 .3v.4l.1 .2 .2 .1 .4-.1M235.4 176.2v1.5M235.4 174.1h1.1M236.1 176.8l.1-.1 .5 .1v.9M236.7 177.1h-.5a.29 .29 0 0 0-.2 .3 .29 .29 0 0 0 .2 .3l.5-.1M237.5 176.2v1.3l.2 .2M238.2 176.8l.5-.1 .3 .3v.4l-.2 .2-.1 .1-.5-.1"/>
<path d="M238.2 176.2v1.5M238.4 174h.6a.41 .41 0 0 0 .3-.4 .41 .41 0 0 0-.3-.4h-.6v1.5M239.7 176.8a.41 .41 0 0 1 .6 .2v.4a.41 .41 0 0 1-.4 .3 .41 .41 0 0 1-.4-.3v-.4zM239.8 174.2l.7-.1v-.3l-.5-.1-.2 .2 .1 .7 .1 .1 .5-.1M241 176.8l.1-.1 .4 .1 .1 .9M241.2 173.7v1M241.6 177.1h-.5a.29 .29 0 0 0-.2 .3 .29 .29 0 0 0 .2 .3l.5-.1M241.6 173.7l-.3 .1-.1 .2M242.1 173.8a.37 .37 0 0 1 .6 .1M242.1 173.7v1M242.3 176.7v1M242.7 176.7l-.2 .1-.2 .2"/>
<path d="M242.7 173.9l.3-.2 .3 .1 .1 .9M242.7 173.9v.8M243.9 176.8l-.4-.1-.3 .3v.4l.1 .2 .2 .1 .4-.1M243.9 176.2v1.5M244.1 173.2v.1M244.1 173.7v1M244.1 173.2l-.1 .1h.1M244.1 173.2l.1 .1h-.1M244.6 177.1h1.1M245.3 173.8l-.3-.1-.3 .2 .1 .2 .5 .2 .1 .1-.1 .2-.1 .1-.5-.1M246.5 176.8a.37 .37 0 0 1 .6 .1v.8M246.5 176.2v1.5"/>
<path d="M246.5 173.8l-.3-.1-.2 .2v.2l.5 .2 .1 .1-.1 .2-.1 .1-.4-.1M247.2 173.2v.1M247.2 173.7v1M247.2 173.2l.1 .1h-.1M247.7 176.7l.3 1 .2-.7 .3 .7 .3-1M247.8 173.7l.4 1 .3-1M249 174.2l.7-.1v-.3l-.5-.1-.2 .2 .1 .7 .1 .1 .5-.1M10.7 184.3a.66 .66 0 0 1 .7 .6 .66 .66 0 0 1-.7 .7zM35.3 198.7l.4-.4v1.3M35.3 199.6h.8M60 198v2M85.3 198.4l.2-.1 .5 .1a.35 .35 0 0 1 0 .5l-.7 .7h.8"/>
<path d="M110 198v2M135.3 198.3h.8l-.4 .5a.35 .35 0 0 1 .4 .2v.4l-.1 .1-.5 .1-.2-.1M160 198v2M177 194.5h108M177 191.5h108M177 187.5h108M177 181.5h108M178.5 185.6h.5M178.5 195.1v1.5M178.7 195.7l.6 .9M179.2 184.9h-.7v1.5M179.2 192.4l-.5-.1a.36 .36 0 0 0-.3 .4 .36 .36 0 0 0 .3 .3 .55 .55 0 0 1 .5 .4v.3l-.2 .1-.6-.1"/>
<path d="M179.2 182.3l-.5-.1a.36 .36 0 0 0-.3 .4 .36 .36 0 0 0 .3 .3 .55 .55 0 0 1 .5 .4v.3l-.2 .1-.6-.1M179.3 195.1l-.8 .9M179.7 184.9v.1M179.7 185.4v1M179.7 184.9l.1 .1h-.1M179.9 182.2v1.5M179.9 192.3v.1M179.9 192.8v1M179.9 192.3l-.1 .1h.1M179.9 192.3l.1 .1h-.1M179.9 182.8a.37 .37 0 0 1 .6 .1v.8M180 195.1v.1"/>
<path d="M180 195.6v1M180 195.1l-.1 .1h.1M180.5 192.8h.7l-.7 1h.7M180.5 184.9v1.3l.2 .2M181.2 183.2l.7-.1-.1-.3-.4-.1-.2 .2v.7l.2 .1 .4-.1M181.2 185.9l.7-.2-.1-.2-.4-.1-.2 .2v.7l.2 .1 .4-.1M181.5 195.2a.6 .6 0 0 0-.7 0 .6 .6 0 0 0-.2 .8 .56 .56 0 0 0 .3 .5 .56 .56 0 0 0 .6 0M181.7 193.3l.8-.1-.1-.3-.4-.1-.3 .2 .1 .7 .2 .1 .4-.1M182.2 195.7l.1-.1 .4 .1 .1 .9M182.5 183.2l.7-.1-.1-.3-.4-.1-.2 .2v.7l.2 .1 .4-.1M182.5 186.3h.1l-.1 .1M182.5 186.3v.1"/>
<path d="M182.5 185.5v.1M182.5 185.5h.1l-.1 .1M182.8 196h-.5a.29 .29 0 0 0-.2 .3 .29 .29 0 0 0 .2 .3l.5-.1M183.1 193.7h.1l-.1 .1M183.1 193.7h-.1l.1 .1M183.1 192.9v.1M183.1 193.7v.1M183.1 192.9h.1l-.1 .1M183.1 192.9h-.1l.1 .1M183.6 182.7h.6M183.8 182.2v1.3l.1 .1 .3 .1M184.2 195.7l-.5-.1-.2 .3v.4l.1 .2 .1 .1 .5-.1"/>
<path d="M184.2 195.1v1.5M184.4 185.5l.4-.1 .3 .3v.4l-.1 .2-.2 .1-.4-.1M184.4 185.4v1.5M184.7 183.6v.1M184.7 183.6h-.1l.1 .1M184.7 182.8v.1M184.7 182.8h-.1l.1 .1M184.7 193.8l.5-1.5 .5 1.5M184.9 193.4h.7M185.7 198.2l-.4 1h.9M185.7 185.9l.7-.2-.1-.2-.4-.1-.2 .2v.7l.2 .1 .4-.1M186 198.7v.9"/>
<path d="M186 195.8h.5M186.5 192.2l-.3 1.1h.9M186.5 182.9h.5M186.7 195.1h-.7v1.5h.7M186.9 192.8v1M187.2 182.2h-.7v1.5M187.4 196.5h.1l-.1 .1M187.4 196.5h-.1l.1 .1M187.4 196.5v.1M187.7 185.5l-.5-.1-.2 .3v.4l.1 .2 .1 .1 .5-.1M187.7 184.9v1.5M187.8 182.7v1"/>
<path d="M188.1 195.1a.79 .79 0 0 1 .9 .5 .79 .79 0 0 1-.3 .9l-.6 .1zM188.2 182.7l-.2 .1-.2 .2M188.4 185.5l.1-.1 .5 .1v.9M188.8 182.8a.41 .41 0 0 1 .7 .2v.4a.41 .41 0 0 1-.4 .3 .41 .41 0 0 1-.4-.3v-.4zM189 185.7l-.5 .1a.3 .3 0 0 0-.2 .3 .3 .3 0 0 0 .2 .3l.5-.1M189.6 196.5h.1l-.1 .1M189.6 196.5h-.1l.1 .1M189.6 196.5v.1M189.7 184.9v1.3l.3 .2M190.1 196.6l.5-1.5 .5 1.5M190.1 182.8a.37 .37 0 0 1 .6 .1v.8M190.1 182.7v1"/>
<path d="M190.2 196.2h.8M190.5 185.5l.5-.1 .2 .3v.4l-.1 .2-.1 .1-.5-.1M190.5 184.9v1.5M191.2 182.7h.6M191.5 182.2v1.3v.1l.3 .1M191.6 196.5h.1l-.1 .1M191.6 196.5h-.1l.1 .1M191.6 196.5v.1M191.9 185.5a.41 .41 0 0 1 .4-.1 .41 .41 0 0 1 .3 .3v.4a.41 .41 0 0 1-.4 .3 .41 .41 0 0 1-.4-.3zM193.2 185.5l.2-.1 .4 .1 .1 .9M193.4 196.6h.8M193.4 195.5l.4-.4v1.5"/>
<path d="M193.9 185.7l-.5 .1a.29 .29 0 0 0-.2 .3 .29 .29 0 0 0 .2 .3l.5-.1M194.1 182.8l-.4-.1-.3 .3v.4l.1 .2 .2 .1 .4-.1M194.6 185.4v1M194.8 182.8a.41 .41 0 0 1 .7 .2v.4a.41 .41 0 0 1-.4 .3 .41 .41 0 0 1-.4-.3v-.4zM195 195.2a.36 .36 0 0 1 .3-.1 .36 .36 0 0 1 .3 .3 .77 .77 0 0 1-.4 1.2 .91 .91 0 0 1-.2-1.4zM195 185.4l-.3 .1-.1 .2M196.1 182.7l.1 .9a.41 .41 0 0 0 .5 0M196.2 185.5l-.5-.1-.2 .3v.4l.1 .2 .1 .1 .5-.1M196.2 184.9v1.5M196.3 196.5h.1l-.1 .1M196.3 196.5h-.1l.1 .1M196.3 196.5v.1"/>
<path d="M196.7 182.7v1M196.9 185.8h1.1M197 191.5v3M197.1 195.2a.36 .36 0 0 1 .4-.1 .36 .36 0 0 1 .2 .3 .77 .77 0 0 1-.4 1.2 .91 .91 0 0 1-.2-1.4zM197.5 182.7v1M197.9 182.7l-.3 .1-.1 .2M198.2 182.7h.5M198.4 182.2v1.3l.1 .1 .2 .1M198.5 196.5v.1M198.5 196.5h-.1l.1 .1M198.7 185.5a.37 .37 0 0 1 .7 .1v.8M198.7 184.9v1.5"/>
<path d="M199.1 196.6h.9M199.1 195.5l.4-.4v1.5M199.1 182.7l.4 1M199.5 183.7l-.2 .4-.2 .1M199.8 182.7l-.3 1M200 185.4l.2 1 .3-.7 .3 .7 .3-1M200.4 182.8l.1-.1 .5 .1v.9M200.5 192.3a.79 .79 0 0 1 .8 .5 .79 .79 0 0 1-.3 .9l-.5 .1zM200.6 196h1.1M201 183.1h-.5a.29 .29 0 0 0-.2 .3 .29 .29 0 0 0 .2 .3l.5-.1M201.7 186.3v.1M201.7 186.3h-.1l.1 .1"/>
<path d="M201.7 182.7v1M202 192.9l.1-.1 .4 .1 .1 .9M202.2 182.7l-.3 .1-.2 .2M202.4 196.6h.8M202.4 195.5l.4-.4v1.5M202.4 184.9v1.5M202.5 185.8l.5 .6M202.6 193.2h-.5a.29 .29 0 0 0-.2 .3 .29 .29 0 0 0 .2 .3l.5-.1M203 185.4l-.6 .6M203.1 192.8h.6M203.3 192.3v1.3l.1 .1 .3 .1M203.3 182.8l-.4-.1-.3 .3v.4l.1 .2 .2 .1 .4-.1"/>
<path d="M203.3 182.2v1.5M203.6 184.9v.1M203.6 185.4v1M203.6 184.9l-.1 .1h.1M203.6 184.9l.1 .1h-.1M204 195.2a.36 .36 0 0 1 .3-.1 .36 .36 0 0 1 .3 .3 .77 .77 0 0 1-.4 1.2 .91 .91 0 0 1-.2-1.4zM204.1 193.3l.7-.1-.1-.3-.4-.1-.2 .2 .1 .7 .1 .1 .4-.1M205 185.5l-.5-.1-.3 .3v.4l.2 .2 .1 .1 .5-.1M205.2 182.8l.1-.1 .4 .1 .1 .9M205.3 196.5h.1l-.1 .1M205.3 196.5h-.1l.1 .1M205.3 196.5v.1"/>
<path d="M205.5 193.7v.1M205.5 193.7h-.1l.1 .1M205.5 192.9v.1M205.5 192.9h-.1l.1 .1M205.6 185.5l.1-.1 .5 .1v.9M205.8 183.1h-.5a.29 .29 0 0 0-.2 .3 .29 .29 0 0 0 .2 .3l.5-.1M206.1 195.2a.36 .36 0 0 1 .4-.1 .36 .36 0 0 1 .2 .3 .77 .77 0 0 1-.4 1.2 .91 .91 0 0 1-.2-1.4zM206.2 185.7l-.5 .1a.29 .29 0 0 0-.2 .3 .29 .29 0 0 0 .2 .3l.5-.1M206.5 182.7v1M207 182.7l-.3 .1-.2 .2M207.2 192.4l.3-.1 .5 .1a.41 .41 0 0 1 0 .5l-.8 .9h.9M207.4 183.2l.7-.1-.1-.3-.4-.1-.2 .2 .1 .7 .1 .1 .4-.1"/>
<path d="M207.5 196.5v.1M207.5 196.5h-.1l.1 .1M207.6 185.5l-.4-.1-.3 .3v.4l.1 .2 .2 .1 .4-.1M207.6 184.9v1.5M208 186.5h1.1M208.1 196.6h.9M208.1 195.5l.4-.4v1.5M208.7 182.8l.2-.1 .4 .1 .1 .9M208.9 192.4a.35 .35 0 0 1 .6 .2 .77 .77 0 0 1-.5 1.2 1 1 0 0 1-.1-1.4zM209.4 183.1h-.5a.29 .29 0 0 0-.2 .3 .29 .29 0 0 0 .2 .3l.5-.1M209.4 194.7h15.9M209.5 185.5l.4-.1 .3 .3v.4l-.2 .2-.1 .1-.4-.1"/>
<path d="M209.5 185.4v1.5M209.6 195.6l.1 .9a.41 .41 0 0 0 .5 0M210 198v2M210.1 192.4l.2-.1 .5 .1a.41 .41 0 0 1 .1 .5l-.9 .9h1M210.2 195.6v1M211 195.1v1.5M211 195.7l.4-.1 .3 .3v.4l-.2 .2-.1 .1-.4-.1M211.5 185.5l-.5-.1-.3 .3v.4l.2 .2 .1 .1 .5-.1M211.9 192.2l-.4 1.1h1M212.1 185.5l.4-.1 .3 .3v.4l-.1 .2-.2 .1-.4-.1M212.1 184.9v1.5M212.2 192.8v1"/>
<path d="M212.3 195.6l.1 .9a.41 .41 0 0 0 .6 0M213 195.6v1M213 193.2h1.2M213.7 195.7a.37 .37 0 0 1 .6 .1v.8M213.7 195.6v1M214.8 193.8h.9M214.8 192.7l.4-.4v1.5M214.8 195.6h.6M215 195.1v1.3l.1 .1 .3 .1M215.9 195.6l.1 .9a.41 .41 0 0 0 .5 0M216.5 192.4a.36 .36 0 0 1 .5 .2 .77 .77 0 0 1-.4 1.2 1 1 0 0 1-.1-1.4zM216.5 195.6v1"/>
<path d="M217.2 195.2l.2-.1 .5 .1a.41 .41 0 0 1 .1 .5l-.9 .9h.9M217.7 193.2h1.2M219.4 195.1h-.7l-.1 .7 .2-.1h.5l.2 .3-.1 .5-.2 .1h-.4l-.2-.1M219.5 193.8h.9M219.5 192.7l.5-.4v1.5M220.1 196.5h.1l-.1 .1M220.1 196.5h-.1l.1 .1M220.1 196.5v.1M220.7 196.6h.9M220.7 195.5l.5-.4v1.5M221.7 192.3a.6 .6 0 0 0-.7 .6v.6l.1 .2 .4 .1 .2-.1 .1-.5-.1-.3h-.5l-.2 .3M222.3 195.2a.36 .36 0 0 1 .4-.1 .36 .36 0 0 1 .3 .3 .77 .77 0 0 1-.5 1.2 .91 .91 0 0 1-.2-1.4z"/>
<path d="M223.7 196.5v.1M223.7 196.5h-.1l.1 .1M224.3 196.6h.9M224.3 195.5l.4-.4v1.5M227 196h1.1M227.5 195.4v1.2M230 195.1v1.5M230.2 195.7l.6 .9M230.8 195.1l-.8 .9M231.5 195.1v.1M231.5 195.6v1M231.5 195.1l-.1 .1h.1"/>
<path d="M232.2 195.1l.6 .1a.36 .36 0 0 1 .2 .3 .36 .36 0 0 1-.3 .3 .4 .4 0 0 1 .3 .4 .4 .4 0 0 1-.3 .4h-.5zM232.2 195.8h.5M233.7 195.7a.41 .41 0 0 1 .7 .2v.4a.41 .41 0 0 1-.4 .3 .41 .41 0 0 1-.4-.3v-.4zM234.8 195.6h.6M235 195.1v1.3l.1 .1 .3 .1M236 198.3h-.6l-.1 .6 .2-.1 .5 .1 .1 .1-.1 .5-.2 .1h-.3l-.2-.1M236.9 195.6l.3 1 .4-1M238.1 196.6h.9M238.1 195.5l.4-.4v1.5M239.6 196.5h.1l-.1 .1M239.6 196.5h-.1l.1 .1M239.6 196.5v.1"/>
<path d="M241.1 195.7l-.3 .3h-.3l-.3-.3v-.3l.2-.2 .4-.1 .2 .1a.99 .99 0 0 1-.3 1.4h-.3M241.7 196.5h.1l-.1 .1M241.7 196.5v.1M242.5 195.2a.36 .36 0 0 1 .4-.1 .36 .36 0 0 1 .3 .3 .77 .77 0 0 1-.5 1.2 .91 .91 0 0 1-.2-1.4zM260 198v2M261 191.5v6.5M263.5 195.1v1.5M264.8 195.7l-.4-.1-.3 .3v.4l.1 .2 .2 .1 .4-.1M264.8 195.1v1.5M265.5 196.5h.1l-.1 .1M265.5 196.5v.1M265.5 195.7v.1"/>
<path d="M265.5 195.7h.1l-.1 .1M267.7 195l-.4 1.1h.9M268 195.6v1M269.9 195l-1.3 2M271 195.1a.6 .6 0 0 0-.7 .6v.6l.2 .2 .4 .1 .2-.1 .1-.5-.2-.3h-.4l-.3 .3M285.7 184.3a.66 .66 0 0 1 .7 .6 .66 .66 0 0 1-.7 .7zM286 198.3a.52 .52 0 0 0-.7 .6v.5l.2 .1 .3 .1 .2-.1 .1-.5-.1-.1-.4-.1-.3 .2"/>
</g>
<g fill="none" stroke="#480000" stroke-width=".3">
<path d="M178.6 179.2v1.5M178.6 179.8a.37 .37 0 0 1 .6 .1v.8M179.7 179.7h.6M179.9 179.2v1.3l.1 .1 .3 .1M180.6 179.7h.5M180.8 179.2v1.3v.1l.3 .1M181.6 179.8l.5-.1 .2 .3v.4l-.1 .2-.1 .1-.5-.1M181.6 179.7v1.5M183.5 179.8l-.4-.1-.2 .2 .1 .2 .5 .2 .1 .1-.1 .2-.2 .1-.4-.1M184.2 179.8v.1M184.2 179.8h.1l-.1 .1M184.2 179.8h-.1l.1 .1"/>
<path d="M186 179.1l-1.3 1.9M187.6 179.1l-1.3 1.9M188.7 179.8l-.4-.1-.3 .3v.4l.1 .2 .2 .1 .4-.1M188.7 179.7v1.2a.41 .41 0 0 1-.6 .2M189.4 179.2v.1M189.4 179.7v1M189.4 179.2l-.1 .1h.1M189.4 179.2l.1 .1h-.1M189.9 179.7h.6M190.1 179.2v1.3l.1 .1 .3 .1M191 179.8a.37 .37 0 0 1 .6 .1v.8M191 179.2v1.5"/>
<path d="M192.3 179.7l.1 .9a.41 .41 0 0 0 .6-.1M193 179.7v1M193.7 179.8l.4-.1 .3 .3v.4l-.1 .2-.2 .1-.4-.1M193.7 179.2v1.5M196.4 179.8l-.4-.1-.3 .3v.4l.1 .2 .2 .1 .4-.1M197.1 179.8a.41 .41 0 0 1 .4-.1 .41 .41 0 0 1 .3 .3v.4a.41 .41 0 0 1-.4 .3 .41 .41 0 0 1-.4-.3zM198.4 179.8a.37 .37 0 0 1 .7 .1M198.4 179.7v1M199.1 179.9l.2-.2 .3 .1 .1 .9M199.1 179.9v.8M201.5 179.1l-1.3 1.9M202 179.8l.4-.1 .3 .3v.4l-.1 .2-.2 .1-.4-.1"/>
<path d="M202 179.7v1.5M205.3 179.8l-.5-.1-.2 .3v.4l.1 .2 .1 .1 .5-.1M205.3 179.2v1.5M206 179.8l.1-.1 .5 .1v.9M207.3 179.2v1.3l.3 .2M208.1 179.8l.5-.1 .2 .3v.4l-.1 .2-.1 .1-.5-.1M208.1 179.2v1.5M209.5 179.8a.41 .41 0 0 1 .4-.1 .41 .41 0 0 1 .3 .3v.4a.41 .41 0 0 1-.4 .3 .41 .41 0 0 1-.4-.3zM210.8 179.8l.2-.1 .4 .1 .1 .9M212.2 179.7v1M212.6 179.7a.38 .38 0 0 0-.4 .3M213.8 179.8l-.5-.1-.2 .3v.4l.1 .2 .1 .1 .5-.1"/>
<path d="M213.8 179.2v1.5M184.2 180.5l.1 .1-.1 .1M184.2 180.5l-.1 .1 .1 .1M184.2 180.5v.2M195.1 180.5v.1v.1M195.1 180.5l-.1 .1 .1 .1M195.1 180.5v.2M203.3 180.2l.7-.2-.1-.2-.4-.1-.2 .2v.7l.2 .1 .4-.1M206.6 180l-.5 .1a.29 .29 0 0 0-.2 .3 .29 .29 0 0 0 .2 .3l.5-.1M211.5 180l-.5 .1a.29 .29 0 0 0-.2 .3 .29 .29 0 0 0 .2 .3l.5-.1M263.6 193.1h.5a.41 .41 0 0 0 .3-.4 .41 .41 0 0 0-.3-.4h-.5v1.5M263.9 193.1l.5 .7"/>
<path d="M265 193.3l.7-.2-.1-.2-.4-.1-.2 .2 .1 .7 .1 .1 .4-.1M266.2 192.8l.4 1 .3-1M267.5 193.6l.1 .1-.1 .1M267.5 193.6l-.1 .1 .1 .1M267.5 192.9v.1M267.5 193.6v.2M267.5 192.9h.1l-.1 .1M267.5 192.9h-.1l.1 .1M270 192.9l-.4-.1-.3 .3v.4l.1 .2 .2 .1 .4-.1M270 192.3v1.5M270.6 193.3l.7-.2v-.2l-.5-.1-.2 .2 .1 .7 .1 .1 .5-.1M271.8 192.8l.4 1 .4-1"/>
</g>
<g fill="none" stroke="#480000" stroke-width=".4">
<path d="M178.7 188.2h1.1M179.3 188.2l-.3 2M180.4 188.9l-.1 1.3M180.5 188.2l-.1 .1 .1 .1M180.5 188.2l.1 .1-.1 .1M180.5 188.2v.2M181.1 188.9h.7M181.5 188.2l-.3 1.7 .1 .2 .4 .1M182.6 188.2l-.2 1.7 .1 .2 .1 .1M183.4 189.5l1-.1-.1-.4-.2-.1-.5 .1-.2 .2-.1 .7 .1 .2 .2 .1 .6-.1M185.1 190l.1 .1-.1 .1M185.1 190l-.1 .1 .1 .1"/>
<path d="M185.1 190v.2M185.3 189l-.1 .2M185.3 189v.1l-.1 .1M185.3 189l-.1 .1v.1M187.8 188.5a.69 .69 0 0 1 1.1 0 1.67 1.67 0 0 1-.3 1.6l-.3 .1-.5-.1a1.5 1.5 0 0 1 0-1.6zM189.8 189l.2-.1 .6 .1 .2 .3-.1 .5a.66 .66 0 0 1-1 .3M189.8 188.9l-.2 2M191.5 189.5l1-.1-.1-.4-.6-.1-.3 .3-.1 .7 .1 .2 .2 .1 .6-.1M193.3 189.1a.49 .49 0 0 1 .9 .1l-.1 1M193.4 188.9l-.2 1.3M196.7 189.3h.7a.55 .55 0 0 0 .5-.5 .55 .55 0 0 0-.3-.6h-.8l-.3 2M198.5 189.5l1-.1v-.4l-.6-.1-.3 .3-.1 .7 .1 .2 .1 .1 .6-.1"/>
<path d="M201.3 189a.66 .66 0 0 0-1 .3l-.1 .5 .2 .3 .1 .1 .6-.1M201.4 188.2l-.3 2M202.2 189l.2-.1 .6 .1 .1 .2-.2 1M203 189.4h-.7a.4 .4 0 0 0-.3 .4 .4 .4 0 0 0 .3 .4l.6-.1M204.1 188.2l-.2 1.7 .1 .2 .2 .1M205.1 189l.2-.1 .5 .1 .2 .3-.1 .5a.66 .66 0 0 1-1 .3M205.2 188.2l-.3 2M206.9 189.1a.52 .52 0 0 1 .5-.2 .52 .52 0 0 1 .4 .4l-.1 .5a.55 .55 0 0 1-.5 .4 .55 .55 0 0 1-.5-.4l.1-.5zM208.7 189l.2-.1 .6 .1v.2l-.1 1M209.5 189.4h-.7a.4 .4 0 0 0-.3 .4 .4 .4 0 0 0 .2 .4l.7-.1M210.5 188.9l-.2 1.3M211.1 188.9a.59 .59 0 0 0-.6 .4"/>
<path d="M212.6 189a.66 .66 0 0 0-1 .3l-.1 .5 .2 .3 .2 .1 .6-.1M212.7 188.2l-.3 2M214.9 190.2l.3-2 .5 1.4 .8-1.4-.2 2M217.4 189l.2-.1 .5 .1 .1 .2-.1 1M218.2 189.4h-.7a.4 .4 0 0 0-.3 .4 .4 .4 0 0 0 .2 .4l.7-.1M219.2 188.9l-.2 1.3M219.3 188.2l-.1 .1v.1M219.3 188.2v.1l-.1 .1M219.3 188.2l-.1 .2M220.1 189.1a.49 .49 0 0 1 .9 .1l-.2 1M220.1 188.9l-.1 1.3M221.9 189l.2-.1 .6 .1 .1 .3v.5a.66 .66 0 0 1-1 .3"/>
<path d="M222 188.2l-.2 2M223.7 189.1a.52 .52 0 0 1 .6-.2 .52 .52 0 0 1 .4 .4l-.1 .5a.55 .55 0 0 1-.5 .4 .55 .55 0 0 1-.6-.4l.1-.5zM225.6 189l.2-.1 .5 .1 .1 .2-.1 1M226.4 189.4h-.7a.4 .4 0 0 0-.4 .4 .4 .4 0 0 0 .3 .4l.7-.1M227.4 188.9l-.2 1.3M227.9 188.9a.59 .59 0 0 0-.6 .4M229.5 189a.66 .66 0 0 0-1 .3l-.1 .5 .2 .3 .1 .1 .6-.1M229.6 188.2l-.3 2"/>
</g>
<use href="#words"/>
</svg>
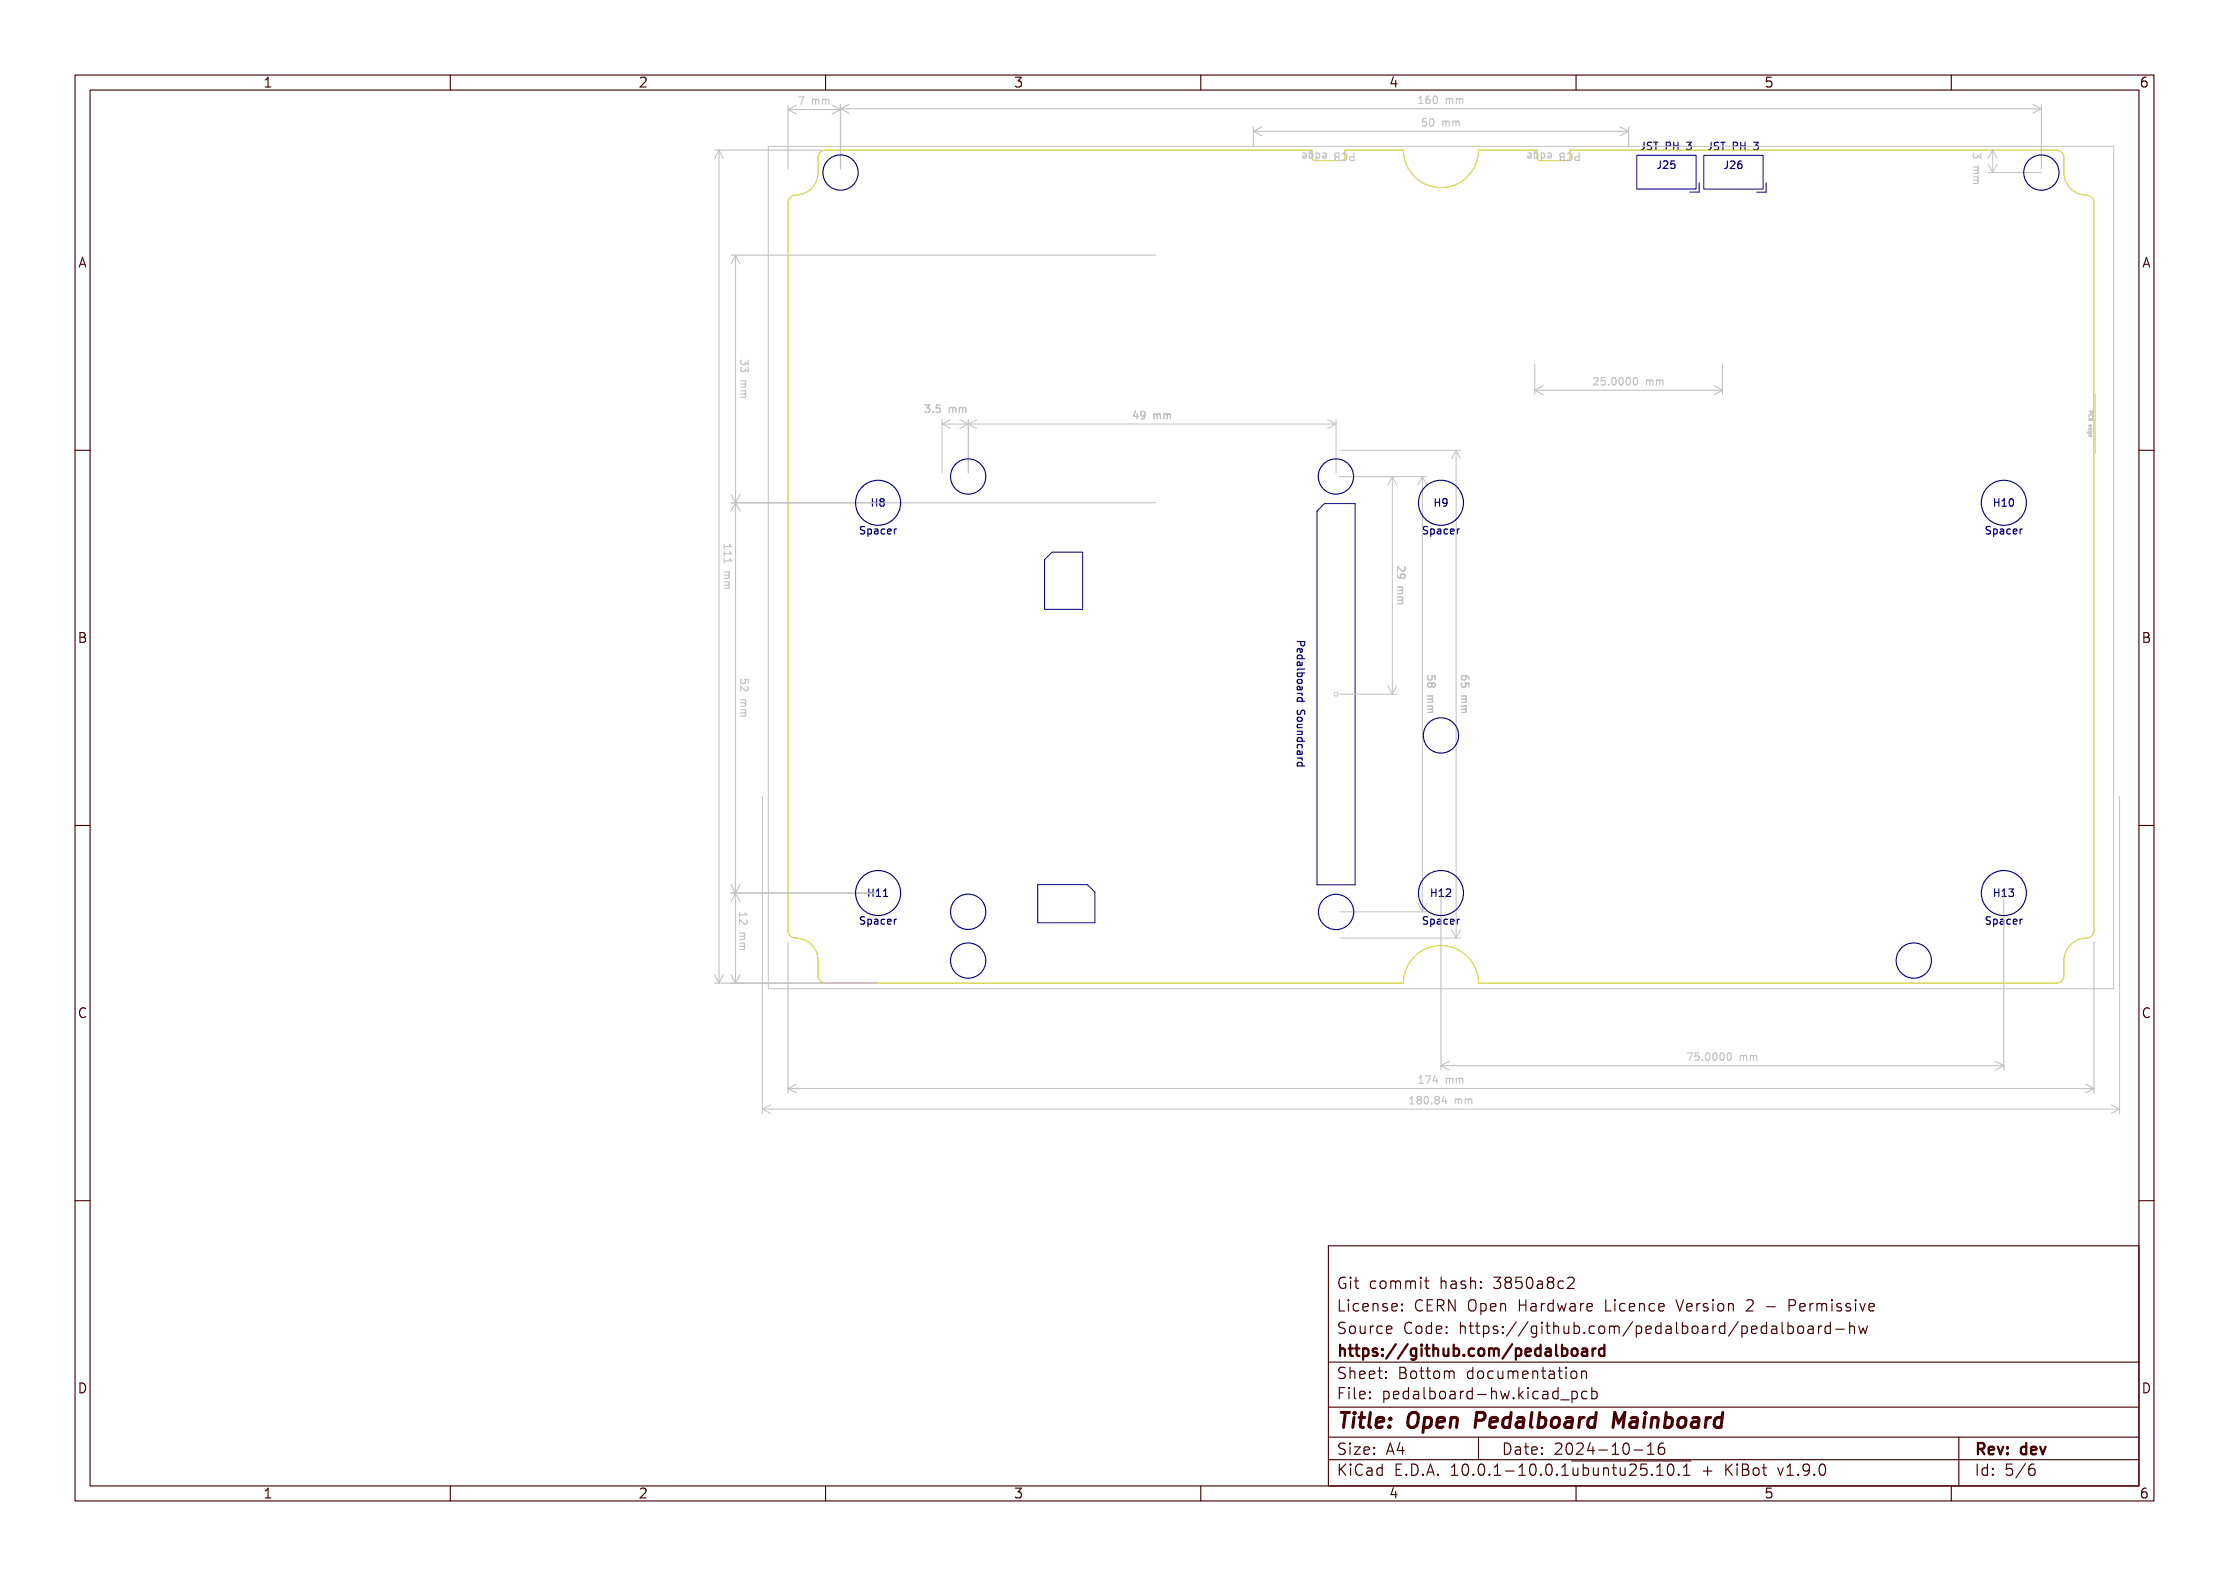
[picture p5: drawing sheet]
<svg xmlns="http://www.w3.org/2000/svg" width="297mm" height="210mm" viewBox="0 0 297 210" stroke-linecap="round" stroke-linejoin="round" font-family="sans-serif">
<defs><g id="words">
<text font-size="2.7" fill="#fff" x="178" y="190.3">Title: Open Pedalboard Mainboard</text>
<g font-size="2" fill="#fff">
<text x="178" y="171.8">Git commit hash: 3850a8c2</text>
<text x="178" y="174.8">License: CERN Open Hardware Licence Version 2 - Permissive</text>
<text x="178" y="177.8">Source Code: https://github.com/pedalboard/pedalboard-hw</text>
<text x="178" y="180.8">https://github.com/pedalboard</text>
<text x="178" y="183.8">Sheet: Bottom documentation</text>
<text x="178" y="186.5">File: pedalboard-hw.kicad_pcb</text>
<text x="178" y="193.9">Size: A4</text>
<text x="178" y="196.7">KiCad E.D.A. 10.0.1-10.0.1~{ubuntu25.10.1} + KiBot v1.9.0</text>
<text x="200" y="193.9">Date: 2024-10-16</text>
<text x="263" y="196.7">Id: 5/6</text>
<text x="263" y="193.9">Rev: dev</text>
</g>
<g font-size="1.7" fill="#fff">
<text x="35" y="11.6">1</text>
<text x="85" y="11.6">2</text>
<text x="135" y="11.6">3</text>
<text x="185" y="11.6">4</text>
<text x="235" y="11.6">5</text>
<text x="285" y="11.6">6</text>
<text x="10.5" y="35.6">A</text>
<text x="285.5" y="35.6">A</text>
<text x="10.5" y="85.6">B</text>
<text x="285.5" y="85.6">B</text>
<text x="10.5" y="135.6">C</text>
<text x="285.5" y="135.6">C</text>
<text x="10.5" y="185.6">D</text>
<text x="285.5" y="185.6">D</text>
<text x="35" y="199.7">1</text>
<text x="85" y="199.7">2</text>
<text x="135" y="199.7">3</text>
<text x="185" y="199.7">4</text>
<text x="235" y="199.7">5</text>
<text x="285" y="199.7">6</text>
</g>
<g font-size="1.3" fill="#fff">
<text x="106.9" y="13.9">7 mm</text>
<text x="189.6" y="13.8">160 mm</text>
<text x="190" y="16.8">50 mm</text>
<text x="180.2" y="20.4" transform="rotate(180 180.2 20.4)">PCB edge</text>
<text x="210.2" y="20.4" transform="rotate(180 210.2 20.4)">PCB edge</text>
<text x="218.8" y="20">JST PH 3</text>
<text x="220.8" y="22.5">J25</text>
<text x="227.8" y="20">JST PH 3</text>
<text x="229.8" y="22.5">J26</text>
<text x="262.9" y="20.9" transform="rotate(90 262.9 20.9)">3 mm</text>
<text x="98.7" y="48.5" transform="rotate(90 98.7 48.5)">33 mm</text>
<text x="213" y="51.3">25.0000 mm</text>
<text x="123.6" y="55">3.5 mm</text>
<text x="151.5" y="55.9">49 mm</text>
<text x="114.6" y="71.2">Spacer</text>
<text x="116.2" y="67.5">H8</text>
<text x="189.6" y="71.2">Spacer</text>
<text x="191.2" y="67.5">H9</text>
<text x="264.6" y="71.2">Spacer</text>
<text x="265.8" y="67.5">H10</text>
<text x="96.5" y="73.1" transform="rotate(90 96.5 73.1)">111 mm</text>
<text x="186.2" y="76" transform="rotate(90 186.2 76)">29 mm</text>
<text x="172.8" y="85.7" transform="rotate(90 172.8 85.7)">Pedalboard Soundcard</text>
<text x="98.7" y="91" transform="rotate(90 98.7 91)">52 mm</text>
<text x="190.2" y="90.5" transform="rotate(90 190.2 90.5)">58 mm</text>
<text x="194.7" y="90.5" transform="rotate(90 194.7 90.5)">65 mm</text>
<text x="115.8" y="119.5">H11</text>
<text x="190.8" y="119.5">H12</text>
<text x="265.8" y="119.5">H13</text>
<text x="98.5" y="122.1" transform="rotate(90 98.5 122.1)">12 mm</text>
<text x="114.6" y="123.2">Spacer</text>
<text x="189.6" y="123.2">Spacer</text>
<text x="264.6" y="123.2">Spacer</text>
<text x="225.5" y="141.3">75.0000 mm</text>
<text x="188.4" y="147.1">180.84 mm</text>
<text x="189.6" y="144.4">174 mm</text>
</g>
<text font-size=".7" fill="#fff" x="278.3" y="54.9" transform="rotate(90 278.3 54.9)">PCB edge</text>
</g></defs>
<g fill="none" stroke="#000084" stroke-width=".15">
<path d="M219.1 18.9v.8a.32 .32 0 0 1-.4 .2M220.1 19l-.4-.1-.2 .2 .1 .3 .4 .2v.2l-.1 .1h-.4M220.4 18.9h.5M220.6 18.9v1M222 19.5l.5-.1 .1-.1-.1-.3-.1-.1h-.4v1M223 18.9v1M223 19.4h.6M223.6 18.9v1M224.7 18.9h.7l-.4 .4 .3 .1v.4l-.1 .1-.5-.1M228 19v.7a.32 .32 0 0 1-.4 .3M229 19h-.4l-.2 .1 .1 .3 .4 .2v.3l-.1 .1-.4-.1M229.3 19h.6"/>
<path d="M229.6 19v1M230.9 19.5l.5-.1 .1-.1v-.3h-.2h-.4v1M231.9 19.4h.6M231.9 19v1M232.5 19v1M233.7 19h.6l-.4 .3 .3 .1v.5l-.1 .1-.4-.1M221.2 21.4v.8a.32 .32 0 0 1-.3 .2M221.7 21.5l.3-.1 .2 .3-.6 .7h.6M223.1 21.4h-.4l-.1 .5 .2-.1 .3 .1 .1 .1-.1 .3-.1 .1-.4-.1M230.2 21.5v.7a.32 .32 0 0 1-.4 .3M230.6 21.5h.4l.2 .2-.7 .8h.7M232 21.5h-.3a.67 .67 0 0 0 0 1l.4-.1v-.4l-.2-.2-.3 .1-.1 .1"/>
<path d="M115.2 70.2h-.4l-.2 .1 .1 .3 .5 .2v.3l-.2 .1-.4-.1M115.6 70.5h.3l.2 .2-.1 .4h-.4M115.6 70.5v1M116.2 66.9h.6M116.2 66.5v1M116.6 70.5h.3l.1 .7M116.8 66.5v1M117 70.7l-.4 .1-.1 .1 .1 .3 .4-.1M117.4 66.9l-.2 .2 .1 .3 .1 .1h.2l.2-.2v-.3l-.2-.1M117.4 66.9l-.2-.2 .2-.2h.2l.2 .1-.2 .3M117.4 66.9h.2M117.9 70.5h-.3l-.2 .2 .1 .4h.4"/>
<path d="M118.3 70.8l.4-.1v-.2h-.3l-.1 .1v.5h.4M119.2 70.5v.7M119.5 70.5l-.3 .2M190.2 70.2h-.4l-.2 .1 .1 .3 .5 .2v.3l-.2 .1-.4-.1M190.6 70.5h.3l.2 .2-.1 .4h-.4M190.6 70.5v1M191.2 66.5v1M191.2 66.9h.6M191.6 70.5h.3l.1 .7M191.8 66.5v1M192 70.7l-.4 .1-.1 .1 .1 .3 .4-.1M192.8 66.9l-.2 .2-.3-.1-.1-.1 .1-.4h.3h.2a.66 .66 0 0 1-.3 1h-.2"/>
<path d="M192.9 70.5h-.3l-.2 .2 .1 .4h.4M193.3 70.8l.4-.1v-.2h-.3l-.1 .1v.5h.4M194.2 70.5v.7M194.5 70.5l-.3 .2M265.2 70.2h-.4l-.2 .1 .1 .3 .5 .2v.3l-.2 .1-.4-.1M265.6 70.5v1M265.6 70.5h.3l.2 .2-.1 .4h-.4M265.8 66.5v1M265.8 66.9h.5M266.3 66.5v1M266.5 70.5h.4l.1 .7M266.8 66.7l.2-.2v1"/>
<path d="M266.8 67.5h.5M267 70.7l-.4 .1-.1 .1 .1 .3 .4-.1M267.9 66.5h.1a.53 .53 0 0 1 .3 .5 .53 .53 0 0 1-.3 .5 .67 .67 0 0 1-.1-1zM267.9 70.5h-.3l-.2 .2 .1 .4h.4M268.3 70.8l.4-.1v-.2h-.3l-.1 .1v.5h.4M269.2 70.5v.7M269.5 70.5l-.3 .2M172.8 85.5h1v.4v.1l-.3 .1-.1-.1-.1-.5M172.8 87.8h1M172.8 89.7h1M172.8 92.4h.7M172.8 93.4h1"/>
<path d="M172.8 97h.7M172.8 97.4h.7M172.8 98.8h1M172.9 94.6l-.1 .4 .1 .2h.3l.2-.5 .3-.1 .1 .2v.4M172.9 87.8l-.1-.3 .2-.2 .5 .1v.4M172.9 88.7l-.1-.4 .2-.1 .2 .1 .1 .4M172.9 89.7l-.1 .3 .2 .2 .5-.1v-.4M172.9 91.9l-.1-.3 .2-.2 .2 .1 .1 .4M172.9 93.4l-.1-.2 .2-.2 .5 .1v.3M172.9 98.8l-.1-.3 .2-.2 .5 .1v.4M172.9 99.7l-.1-.3 .2-.2 .5 .1v.4M172.9 90.6h.5l.1 .1v.3l-.2 .1-.4-.1-.1-.1z"/>
<path d="M172.9 95.6h.5l.1 .2v.2l-.2 .1h-.4l-.1-.2zM173.2 86.4l.1 .5h.2v-.3l-.1-.2-.5 .1v.4M173.3 92.4l.2 .3M173.4 97.4l.1 .2v.2l-.7 .1M173.5 88.3v.3l-.7 .1M173.5 91.5v.4h-.7M173.5 96.5l-.6 .1-.1 .2 .1 .2M173.8 89.2h-.8l-.2 .1M115.8 118.9h.5M115.8 118.5v1M116.3 118.5v1M116.8 119.5h.5"/>
<path d="M116.8 118.7l.2-.2v1M117.7 119.5h.6M117.7 118.7l.3-.2v1M172.8 101h.7M172.8 102.1h1M172.9 100.5l-.1-.3 .2-.1h.2l.1 .4M172.9 102.1l-.1-.3 .2-.2 .5 .1v.4M173.3 101l.2 .3M173.5 100.1v.4h-.7M190.8 118.9h.5M190.8 118.5v1M191.3 118.5v1"/>
<path d="M191.8 119.5h.5M191.8 118.7l.3-.2v1M192.7 118.5h.4h.1l.1 .2-.6 .8h.6M265.8 118.5v1M265.8 118.9h.5M266.3 118.5v1M266.8 119.5h.5M266.8 118.7l.2-.2v1M267.7 118.5h.6l-.3 .3 .2 .1v.5l-.1 .1-.4-.1M115.2 122.2h-.4l-.2 .1 .1 .3 .5 .2v.3l-.2 .1-.4-.1M115.6 122.5h.3l.2 .2-.1 .4h-.4M115.6 122.5v1"/>
<path d="M116.6 122.5h.3l.1 .7M117 122.7l-.4 .1-.1 .1 .1 .3 .4-.1M117.9 122.5h-.3l-.2 .2 .1 .4h.4M118.3 122.8l.4-.1v-.2h-.3l-.1 .1v.5h.4M119.2 122.5v.7M119.5 122.5h-.2l-.1 .2M190.2 122.2h-.4h-.1v.3l.4 .2 .1 .3-.2 .2-.4-.1M190.6 122.5h.3l.2 .2-.1 .4h-.4M190.6 122.5v1M191.6 122.5h.3l.1 .7M192 122.7l-.4 .1-.1 .1 .1 .3 .4-.1M192.9 122.5h-.3l-.2 .2 .1 .4h.4"/>
<path d="M193.3 122.8l.4-.1v-.2h-.3l-.1 .1v.5h.4M194.2 122.5v.7M194.5 122.5h-.2l-.1 .2M265.2 122.2h-.4h-.1v.3l.4 .2 .1 .3-.2 .2-.4-.1M265.6 122.5h.3l.2 .2-.1 .4h-.4M265.6 122.5v1M266.5 122.5h.4l.1 .7M267 122.7l-.4 .1-.1 .1 .1 .3 .4-.1M267.9 122.5h-.3l-.2 .2 .1 .4h.4M268.3 122.8l.4-.1v-.2h-.3l-.1 .1v.5h.4M269.2 122.5v.7M269.5 122.5l-.3 .2"/>
<circle cx="112" cy="23" r="2.35"/>
<circle cx="272" cy="23" r="2.35"/>
<circle cx="117" cy="67" r="3"/>
<circle cx="129" cy="63.5" r="2.35"/>
<circle cx="178" cy="63.5" r="2.35"/>
<circle cx="192" cy="67" r="3"/>
<circle cx="267" cy="67" r="3"/>
<circle cx="192" cy="98" r="2.35"/>
<circle cx="117" cy="119" r="3"/>
<circle cx="192" cy="119" r="3"/>
<circle cx="267" cy="119" r="3"/>
<circle cx="129" cy="121.5" r="2.35"/>
<circle cx="129" cy="128" r="2.35"/>
<circle cx="178" cy="121.5" r="2.35"/>
<circle cx="255" cy="128" r="2.35"/>
</g>
<path d="M218.1 20.7h7.9v4.5h-7.9zM226.4 24.3v1.3h-1.2M227 20.7h7.9v4.5h-7.9zM235.3 24.4v1.2h-1.2M140.2 73.6h4.1v7.6h-5.1v-6.6zM176.5 67.1h4.1v50.8h-5.1v-49.8zM138.3 117.9h6.6l1 1v4.1h-7.6z" fill="none" stroke="#000084" stroke-width=".13"/>
<path d="M109.3 20.3l.3-.2 .4-.1h64.8v1l.2 .3 3.8 .1 .3-.2 .1-1.2h7.8a5 5 0 0 0 5 5 5 5 0 0 0 5-5h7.8l.1 1.2 .3 .2 3.8-.1 .2-.3v-1h64.8a1 1 0 0 1 1 1v2a3 3 0 0 0 3 3 1 1 0 0 1 1 1v97a1 1 0 0 1-1 1 3 3 0 0 0-3 3v2a1 1 0 0 1-1 1h-77a5 5 0 0 0-5-5 5 5 0 0 0-5 5h-77a1 1 0 0 1-1-1v-2a3 3 0 0 0-3-3 1 1 0 0 1-1-1v-97a1 1 0 0 1 1-1 3 3 0 0 0 3-3v-2l.1-.4z" fill="none" stroke="#c2c200" stroke-width=".13"/>
<g fill="none" stroke="#c2c2c2" stroke-width=".13">
<path d="M102.4 19.5h179.2v112.3h-179.2zM264.9 20h7.1M265.5 20v3M265.5 20l-.6 1.1M265.5 20l.6 1.1M264.9 23h7.1M264.9 21.9l.6 1.1M266.1 21.9l-.6 1.1M125.5 56.5h52.5M125.5 55.9v7.1M125.5 56.5l1.1 .6M126.6 55.9l-1.1 .6"/>
<path d="M127.9 55.9l2.2 1.2M129 55.9v7.1M130.1 55.9l-2.2 1.2M176.9 55.9l1.1 .6M178 55.9v7.1M178 56.5l-1.1 .6M278.2 57.5l.1 .2h.4M278.3 54.8h.5v.2h-.2v-.2M278.3 55.8h.5v.1l-.1 .1-.1-.1-.2 .2zM278.4 57.7v-.2l.2 .1v.1M278.4 55.6a.22 .22 0 0 1 .2-.4 .22 .22 0 0 1 .2 .4M278.5 56.6l.1 .3v-.1v-.2l-.2 .1v.1"/>
<path d="M278.5 58l.1 .2v-.2h-.2v.2M278.6 55.8v.1M278.6 57.3v-.2h-.2v.2h.4M279.2 52.5v8M178.5 63.5h11.6M178.5 60h16.1M185.5 63.5v29M185.5 63.5l-.6 1.1M185.5 63.5l.6 1.1M189.5 63.5v58M189.5 63.5l-.6 1.1M189.5 63.5l.6 1.1"/>
<path d="M194 60v65M194 60l-.6 1.1M194 60l.6 1.1M178.5 92.5h7.6M184.9 91.4l.6 1.1M186.1 91.4l-.6 1.1M101.6 106.1v42.3M282.4 106.1v42.3M178.5 121.5h11.6M178.5 125h16.1M188.9 120.4l.6 1.1M190.1 120.4l-.6 1.1"/>
<path d="M193.4 123.9l.6 1.1M194.6 123.9l-.6 1.1M101.6 147.8h180.8M101.6 147.8l1.1 .6M102.7 147.2l-1.1 .6M281.3 147.2l1.1 .6M282.4 147.8l-1.1 .6"/>
<circle cx="178" cy="92.5" r=".25"/>
</g>
<g fill="none" stroke="#c2c2c2" stroke-width=".15">
<path d="M95.2 20h14.3M95.8 20v111M95.8 20l-.6 1.1M95.8 20l.6 1.1M105 14v8.5M105 14.6l1.1 .6M106.1 14l-1.1 .6M106.4 12.9h.7l-.4 1M108.3 13.2v.7M108.3 13.3l.2-.1 .2 .2M108.7 13.4v.5M108.7 13.4l.1-.2 .3 .1v.6"/>
<path d="M109.6 13.3l.3-.1 .1 .2M109.6 13.2v.7M110 13.4l.2-.2 .2 .1v.6M110 13.4v.5M110.9 14l1.1 .6M112 14.6h-7M112 14.6l-1.1 .6M112 13.9v8.6v-8.5M112 14.5h160M112 14.5l1.1 .6M113.1 13.9l-1.1 .6M167 16.9v2.6"/>
<path d="M167 17.5h50M167 17.5l1.1 .6M168.1 16.9l-1.1 .6M189 13.1l.3-.3v1M189 13.8h.6M190 15.8h-.4l-.1 .5 .2-.1h.3l.1 .2-.1 .3-.1 .1-.4-.1M190.5 12.8l-.3 .1a.67 .67 0 0 0 0 .9l.3-.1 .1-.3-.2-.2h-.2l-.2 .2M190.6 15.9l.1-.1a.53 .53 0 0 1 .4 .5 .53 .53 0 0 1-.4 .5l-.1-.1-.1-.3zM191 12.9l.2-.1a.53 .53 0 0 1 .3 .5 .53 .53 0 0 1-.3 .5l-.2-.1v-.3zM192.2 16.1v.7M192.2 16.2l.3-.1 .2 .2M192.7 16.3l.1-.2 .2 .1 .1 .6"/>
<path d="M192.7 16.3v.5M192.7 13.1v.7M192.7 13.2l.3-.1 .1 .2M193.1 13.3l.2-.2 .2 .1 .1 .6M193.1 13.3v.5M193.6 16.2l.3-.1 .1 .2M193.6 16.1v.7M194 16.3l.1-.2 .3 .1v.6M194 16.3v.5M194 13.1v.7M194 13.2l.3-.1 .2 .2M194.5 13.3v.5"/>
<path d="M194.5 13.3l.1-.2 .3 .1v.6M215.9 16.9l1.1 .6M217 16.9v2.6M217 17.5l-1.1 .6M270.9 13.9l1.1 .6M272 13.9v8.6M272 14.5l-1.1 .6M97.4 34h56.6M98 34v97M98 34l-.6 1.1M98 34l.6 1.1M173.6 20.4h.3l.1 .1v.5h-.4v-.2l.4-.1"/>
<path d="M174.5 20.4h.2l.2 .2-.1 .4h-.3M174.9 20.1h-.3l-.1 .2v.8M175.4 20.4h.2l.2 .2-.1 .4h-.3M175.4 20.4v1M176.3 20.4h.3l.1 .1-.1 .5h-.3l-.1-.2 .5-.1M177.9 20.5l.1-.1h.4v1l-.5-.1v-.2l.2-.2a.26 .26 0 0 1-.3-.1 .26 .26 0 0 1 .1-.3zM178.1 20.9h.3M178.8 20.5a.47 .47 0 0 1 .7 .3 .47 .47 0 0 1-.5 .6l-.2-.1M180.4 20.4v1h-.4l-.1-.1-.1-.2 .1-.2h.5M203.6 20.4h.3l.1 .1v.5h-.4v-.2l.4-.1M204.5 20.4h.2l.2 .2-.1 .4h-.3M204.9 20.1h-.2l-.2 .2v.8"/>
<path d="M205.4 20.4h.3l.1 .2-.1 .4h-.3M205.4 20.4v1M206.3 20.4h.3l.1 .1v.5h-.4l-.1-.2 .5-.1M207.9 20.5l.1-.1h.4v1l-.5-.1v-.2l.2-.2a.26 .26 0 0 1-.2-.1 .26 .26 0 0 1 0-.3zM208.1 20.9h.3M208.8 20.5a.47 .47 0 0 1 .7 .3 .47 .47 0 0 1-.5 .6l-.2-.1M210.4 20.4v1h-.4l-.1-.1-.1-.2 .1-.2h.5M262.9 22.3h.7M262.9 22.7h.6M262.9 23.6h.7M262.9 24h.6M263 20.5l-.1 .4 .2 .2 .4-.1v-.3l.4 .4v-.6"/>
<path d="M263.5 22.7l.1 .1-.1 .3h-.6M263.5 24l.1 .2-.1 .2h-.6M263.5 22.3l.1 .2-.1 .2M263.5 23.6l.1 .3-.1 .1M98.7 50.7h.7M98.7 51.2h.5M98.7 52.1h.7M98.7 52.5h.5M98.8 48l-.1 .4 .2 .2 .3-.1 .1-.2 .4 .3v-.6M98.8 48.9l-.1 .5 .2 .1h.3l.1-.3 .4 .3v-.6M99.2 51.2l.2 .1-.1 .2-.6 .1M99.2 52.5l.2 .1-.1 .3h-.6"/>
<path d="M99.3 50.7l.1 .3-.2 .2M99.3 52.1l.1 .3-.2 .1M123.3 54h.6l-.4 .3 .3 .1v.5l-.1 .1-.4-.1M124.3 54.9v.1M125.3 54h-.5l-.1 .4 .2-.1 .3 .1 .1 .1v.4l-.2 .1-.4-.1M126.5 54.3v.7M126.5 54.4l.3-.1 .1 .1M126.9 54.4l.2-.1h.2l.1 .7M126.9 54.4v.6M127.8 54.4l.3-.1 .2 .1M127.8 54.3v.7M128.3 54.4l.1-.1h.2l.1 .7"/>
<path d="M128.3 54.4v.6M151.3 54.8l-.3 .7h.7M151.5 55.1v.7M152.6 55.2l-.2 .2h-.3l-.1-.2 .1-.3 .3-.1 .1 .1a.66 .66 0 0 1-.2 .9h-.2M153.8 55.1v.7M153.8 55.2l.2-.1 .2 .2M154.2 55.3l.1-.2 .3 .1v.6M154.2 55.3v.5M155.1 55.2l.3-.1 .1 .2M155.1 55.1v.7M155.5 55.3l.2-.2 .2 .1 .1 .6M155.5 55.3v.5"/>
<path d="M204.5 48.5v4.1M204.5 52h25M204.5 52l1.1 .6M205.6 51.4l-1.1 .6M212.4 50.4l.4-.1 .2 .3-.7 .7h.7M213.9 50.3h-.5l-.1 .5 .2-.1h.3l.1 .2v.3l-.2 .1-.4-.1M214.3 51.2v.1M214.9 50.4l.1-.1a.53 .53 0 0 1 .3 .5 .53 .53 0 0 1-.3 .5 .67 .67 0 0 1-.1-.9zM215.9 50.4l.1-.1a.53 .53 0 0 1 .3 .5 .53 .53 0 0 1-.3 .5 .66 .66 0 0 1-.1-.9zM216.8 50.4l.1-.1a.53 .53 0 0 1 .4 .5 .53 .53 0 0 1-.4 .5l-.1-.1-.1-.3zM217.8 50.4l.1-.1a.53 .53 0 0 1 .3 .5 .53 .53 0 0 1-.3 .5 .66 .66 0 0 1-.1-.9zM219.4 50.6v.7"/>
<path d="M219.4 50.7l.3-.1 .1 .2M219.8 50.8l.2-.2 .2 .1v.6M219.8 50.8v.5M220.7 50.7l.3-.1 .1 .2M220.7 50.6v.7M221.1 50.8l.2-.2 .2 .1 .1 .6M221.1 50.8v.5M228.4 51.4l1.1 .6M229.5 48.5v4.1M229.5 52l-1.1 .6M96.5 72.5v.6M96.5 73.5v.6"/>
<path d="M96.5 74.5v.5M96.5 76.2h.7M96.5 76.6h.5M96.5 77.5h.7M96.5 78h.5M97 76.6l.2 .2-.1 .2-.6 .1M97 78l.2 .1-.1 .3h-.6M97.1 76.2l.1 .3-.2 .1M97.1 77.5l.1 .3-.2 .2M97.2 72.5l.3 .3h-1M97.2 73.5l.3 .3h-1M97.2 74.5l.3 .2h-1"/>
<path d="M97.4 67h56.6M97.4 65.9l1.2 2.2M98.6 65.9l-1.2 2.2M186.2 76.6l.1 .3a.67 .67 0 0 0 .9 0l-.1-.4h-.3l-.2 .2v.3l.2 .1M186.2 78.2h.7M186.2 78.7h.5M186.2 79.6h.7M186.7 78.7l.2 .1-.1 .3h-.6M186.8 78.2l.1 .3-.2 .2M186.8 79.6l.1 .3-.2 .1M187.1 75.5l.1 .4-.3 .2-.7-.6v.6M98.7 93.2h.7"/>
<path d="M98.7 93.7h.5M98.7 94.6h.7M98.7 95h.5M98.8 90.5l-.1 .2 .1 .3 .3 .1 .2-.1v-.3l-.1-.2 .5 .1v.4M99.2 93.7l.2 .1-.1 .2-.6 .1M99.2 95l.2 .1-.1 .3h-.6M99.3 93.2l.1 .3-.2 .2M99.3 94.6l.1 .3-.2 .1M99.6 91.5l.1 .4-.3 .1-.7-.6v.6M186.2 80h.5M186.7 80l.2 .1-.1 .3h-.6M190.2 92.7h.7"/>
<path d="M190.2 93.2h.5M190.2 94.1h.7M190.2 94.5h.5M190.3 90l-.1 .2 .1 .4h.3l.2-.1v-.3l-.1-.2 .5 .1v.5M190.7 93.2l.2 .1-.1 .3h-.6M190.7 94.5l.2 .1-.1 .3h-.6M190.8 91.2v.2M190.8 91.2l.2-.2 .2 .2v.2l-.2 .2-.2-.2M190.8 91.2l-.2-.2h-.3l-.1 .2 .1 .3 .1 .1 .3-.1 .1-.1M190.8 92.7l.1 .3-.2 .2M190.8 94.1l.1 .3-.2 .1M194.7 92.7h.7"/>
<path d="M194.7 93.2h.5M194.7 94.1h.7M194.7 94.5h.5M194.8 91l-.1 .1 .1 .4 .3 .1 .2-.1v-.4l-.1-.1h.5v.5M195.1 90l.2 .2v.2l-.2 .2-.3-.1-.1-.3 .1-.1a.66 .66 0 0 1 .9 .2v.2M195.2 93.2l.2 .1-.1 .3h-.6M195.2 94.5l.2 .1-.1 .3h-.6M195.3 92.7l.1 .3-.2 .2M195.3 94.1l.1 .3-.2 .1M97.4 119h19.4M97.4 117.9l1.2 2.2M98.6 117.9l-1.2 2.2"/>
<path d="M192 119.5v23.1M267 119.5v23.1M95.2 131h21.6M95.2 129.9l.6 1.1M96.4 129.9l-.6 1.1M97.4 129.9l.6 1.1M98.5 121.6v.6M98.5 124.3h.7M98.5 124.8h.6M98.5 125.7h.7M98.5 126.1h.6M98.6 129.9l-.6 1.1"/>
<path d="M99.1 124.8l.1 .1v.2l-.7 .1M99.1 126.1l.1 .1v.3h-.7M99.1 124.3l.1 .3-.1 .2M99.1 125.7l.1 .3-.1 .1M99.3 121.6l.2 .3h-1M99.5 122.6v.4l-.2 .1-.8-.6v.6M105 125.5v20.1M279 125.5v20.1M105 145h174M105 145l1.1 .6M106.1 144.5l-1.1 .5M187.9 147.1h.5"/>
<path d="M187.9 146.4l.2-.3v1M189 146.5l-.2 .2 .1 .3 .1 .1h.3l.1-.2v-.2l-.2-.2M189 146.5l-.2-.2 .2-.2 .3 .1 .1 .1-.2 .2M189 146.5h.2M189.1 144.4h.5M189.1 143.6l.2-.2v1M189.9 146.2l.1-.1a.53 .53 0 0 1 .3 .5 .53 .53 0 0 1-.3 .5 .66 .66 0 0 1-.1-.9zM190 143.4h.6l-.4 1M190.8 147v.1M191.2 143.3l-.2 .7h.6M191.4 146.5l-.2 .2v.3l.2 .1h.3l.1-.2-.1-.3-.1-.1M191.4 146.5l-.2-.2 .2-.2 .3 .1 .1 .1-.2 .2"/>
<path d="M191.4 146.5h.2M191.4 143.7v.7M192 142h75M192 142l1.1 .6M192.4 146.1l-.3 .7h.7M192.6 146.4v.7M192.7 143.7v.7M192.7 143.8l.3-.1 .1 .1M193.1 141.4l-1.1 .6M193.1 143.8l.2-.1h.2l.1 .7M193.1 143.8v.6M193.9 146.4v.7"/>
<path d="M193.9 146.5l.3-.1 .1 .2M194 143.8l.3-.1 .2 .1M194 143.7v.7M194.3 146.6l.2-.2 .2 .1 .1 .6M194.3 146.6v.5M194.5 143.8l.1-.1h.3v.7M194.5 143.8v.6M195.2 146.5l.3-.1 .2 .2M195.2 146.4v.7M195.7 146.6l.1-.2 .2 .1 .1 .6M195.7 146.6v.5M224.8 140.3h.7l-.4 1"/>
<path d="M226.4 140.3h-.5l-.1 .5 .2-.1h.3l.1 .2v.3l-.2 .1-.4-.1M226.8 141.2v.1M227.4 140.4l.1-.1a.53 .53 0 0 1 .3 .5 .53 .53 0 0 1-.3 .5 .67 .67 0 0 1-.1-.9zM228.4 140.4l.1-.1a.53 .53 0 0 1 .3 .5 .53 .53 0 0 1-.3 .5 .67 .67 0 0 1-.1-.9zM229.3 140.4l.1-.1a.53 .53 0 0 1 .4 .5 .53 .53 0 0 1-.4 .5 .67 .67 0 0 1-.1-.9zM230.2 140.4l.2-.1a.53 .53 0 0 1 .3 .5 .53 .53 0 0 1-.3 .5l-.2-.1-.1-.3zM231.9 140.6v.7M231.9 140.7l.3-.1 .1 .2M232.3 140.8l.2-.2 .2 .1v.6M232.3 140.8v.5M233.2 140.7l.3-.1 .1 .2M233.2 140.6v.7"/>
<path d="M233.6 140.8l.2-.2 .2 .1 .1 .6M233.6 140.8v.5M265.9 141.4l1.1 .6M267 142l-1.1 .6M277.9 144.5l1.1 .5M279 145l-1.1 .6"/>
</g>
<g fill="none" stroke="#480000" stroke-width=".15">
<path d="M10 10h277v190h-277zM12 12h273v186h-273zM35.3 11.6h.8M35.3 10.7l.4-.4v1.3M60 10v2M85.3 10.4l.2-.1 .5 .1a.35 .35 0 0 1 0 .5l-.7 .7h.8M110 10v2M135.3 10.3h.8l-.4 .5a.35 .35 0 0 1 .4 .2v.3l-.1 .2-.5 .1-.2-.1M160 10v2M185.7 10.2l-.4 1h.9M186 10.7v.9M210 10v2"/>
<path d="M236 10.3h-.6l-.1 .6 .2-.1 .5 .1 .1 .1-.1 .5-.2 .1h-.3l-.2-.1M260 10v2M286 10.3a.52 .52 0 0 0-.7 .6v.4l.2 .2 .3 .1 .2-.1 .1-.5-.1-.1-.4-.1-.3 .2M10.6 35.6l.4-1.3 .4 1.3M10.7 35.2h.6M285.6 35.6l.4-1.3 .4 1.3M285.7 35.2h.6M10 60h2M285 60h2M10.7 84.3h.4l.2 .1v.3l-.2 .2a.35 .35 0 0 1 .3 .3 .35 .35 0 0 1-.2 .4h-.5zM10.7 84.9h.4M285.7 84.3h.4l.2 .1v.3l-.2 .2a.35 .35 0 0 1 .3 .3 .35 .35 0 0 1-.2 .4h-.5z"/>
<path d="M285.7 84.9h.4M10 110h2M285 110h2M11.4 134.4a.52 .52 0 0 0-.6 0 .52 .52 0 0 0-.2 .6 .49 .49 0 0 0 .2 .5 .49 .49 0 0 0 .6 0M286.4 134.4a.52 .52 0 0 0-.6 0 .52 .52 0 0 0-.2 .6 .49 .49 0 0 0 .3 .5 .49 .49 0 0 0 .5 0M10 160h2M285 160h2M177 166h108v32h-108zM178.5 173.2v1.5h.7M179.2 176.3l-.5-.1a.36 .36 0 0 0-.3 .4 .36 .36 0 0 0 .3 .3 .55 .55 0 0 1 .5 .4v.3l-.2 .1-.6-.1M179.2 170.3a.62 .62 0 0 0-.7 .1 .62 .62 0 0 0-.1 .7 .56 .56 0 0 0 .3 .5 .56 .56 0 0 0 .6 0v-.5h-.3M179.7 173.2v.1"/>
<path d="M179.7 173.7v1M179.7 173.2l-.1 .1h.1M180 170.2v.1M180 170.7v1M180 176.8a.41 .41 0 0 1 .6 .2v.4a.41 .41 0 0 1-.4 .3 .41 .41 0 0 1-.4-.3v-.4zM180 170.2l-.1 .1h.1M180.5 170.7h.5M180.7 170.2v1.3v.1l.3 .1M181 173.8l-.4-.1-.3 .3v.4l.2 .2 .1 .1 .4-.1M181.2 176.7l.1 .9a.41 .41 0 0 0 .6 0M181.6 174.2l.7-.1-.1-.3-.4-.1-.2 .2 .1 .7 .1 .1 .4-.1M181.9 176.7v1"/>
<path d="M182.6 176.7v1M183 173.8a.37 .37 0 0 1 .6 .1v.8M183 173.7v1M183 176.7l-.3 .1-.1 .2M183.3 170.8l-.4-.1-.3 .3v.4l.1 .2 .2 .1 .4-.1M184 170.8a.41 .41 0 0 1 .4-.1 .41 .41 0 0 1 .3 .3v.4a.41 .41 0 0 1-.4 .3 .41 .41 0 0 1-.4-.3zM184.2 176.8l-.5-.1-.2 .3v.4l.1 .2 .1 .1 .5-.1M184.7 177.2l.8-.1-.1-.3-.4-.1-.3 .2 .1 .7 .2 .1 .4-.1M184.8 173.8l-.3-.1-.3 .2 .1 .2 .5 .2 .1 .1-.1 .2-.1 .1-.5-.1M185.3 170.8a.37 .37 0 0 1 .7 .1M185.3 170.7v1M185.5 174.2l.7-.1-.1-.3-.4-.1-.2 .2v.7l.2 .1 .4-.1"/>
<path d="M186 170.9l.2-.2 .3 .1 .1 .9M186 170.9v.8M186.8 174.6h.1l-.1 .1M186.8 174.6h-.1l.1 .1M186.8 173.8v.1M186.8 174.6v.1M186.8 173.8h.1l-.1 .1M186.8 173.8h-.1l.1 .1M187.3 170.7v1M187.3 170.8a.37 .37 0 0 1 .7 .1M188 170.9v.8M188 170.9l.2-.2 .3 .1 .1 .9"/>
<path d="M188.1 176.3a.6 .6 0 0 0-.7 0 .6 .6 0 0 0-.2 .8 .56 .56 0 0 0 .3 .5 .56 .56 0 0 0 .6 0M188.8 176.8a.41 .41 0 0 1 .7 .2v.4a.41 .41 0 0 1-.4 .3 .41 .41 0 0 1-.4-.3v-.4zM189.3 170.2l-.1 .1h.1M189.3 170.2v.1M189.3 170.7v1M189.3 170.2l.1 .1h-.1M189.5 173.3a.6 .6 0 0 0-.7 0 .6 .6 0 0 0-.2 .8 .56 .56 0 0 0 .3 .5 .56 .56 0 0 0 .6 0M189.8 170.7h.6M190 170.2v1.3l.1 .1 .3 .1M190.2 173.9h.5M190.7 176.8l-.4-.1-.3 .3v.4l.2 .2 .1 .1 .4-.1M190.7 176.2v1.5"/>
<path d="M190.9 173.2h-.7v1.5h.7M191.4 177.2l.7-.1-.1-.3-.4-.1-.2 .2 .1 .7 .1 .1 .4-.1M191.5 174h.6a.41 .41 0 0 0 .3-.4 .41 .41 0 0 0-.3-.4h-.6v1.5M191.9 174l.5 .7M192 170.8a.37 .37 0 0 1 .7 .1v.8M192 170.2v1.5M192.7 177.6h.1l-.1 .1M192.7 177.6v.1M192.7 176.8v.1M192.7 176.8h.1l-.1 .1M193.4 170.8l.1-.1 .5 .1v.9M193.9 173.2v1.5l-.9-1.5v1.5"/>
<path d="M194 171.1h-.5a.29 .29 0 0 0-.2 .3 .29 .29 0 0 0 .2 .3l.5-.1M194.6 176.2v1.5M194.6 176.8a.37 .37 0 0 1 .6 .1v.8M195.2 170.8l-.3-.1-.2 .2v.2l.5 .2 .1 .1-.1 .2-.1 .1-.4-.1M195.7 173.4a.5 .5 0 0 1 .6-.2 .5 .5 0 0 1 .4 .5v.5a.5 .5 0 0 1-.5 .5 .5 .5 0 0 1-.5-.5zM195.7 176.7h.6M196 176.2v1.3v.1l.3 .1M196 170.2v1.5M196 170.8a.37 .37 0 0 1 .6 .1v.8M196.6 176.7h.6M196.8 176.2v1.3l.1 .1 .3 .1M197.3 173.8l.4-.1 .3 .3v.4l-.1 .2-.2 .1-.4-.1"/>
<path d="M197.3 170.8v.1M197.3 171.6v.1M197.3 173.7v1.5M197.3 171.6h.1l-.1 .1M197.3 171.6h-.1l.1 .1M197.3 170.8h.1l-.1 .1M197.3 170.8h-.1l.1 .1M197.7 176.7v1.5M197.7 176.8l.4-.1 .3 .3v.4l-.2 .2-.1 .1-.4-.1M198.6 174.2l.7-.1-.1-.3-.4-.1-.2 .2 .1 .7 .1 .1 .4-.1M199 170.2h1l-.5 .6a.41 .41 0 0 1 .5 .3v.3l-.2 .2-.6 .1-.2-.1M199.5 176.8l-.3-.1-.2 .2v.2l.5 .2 .1 .1-.1 .2-.1 .1-.4-.1"/>
<path d="M200 173.8a.37 .37 0 0 1 .6 .1v.8M200 173.7v1M200.2 177.6h.1l-.1 .1M200.2 176.8v.1M200.2 177.6v.1M200.2 176.8h.1l-.1 .1M200.8 170.8l-.2-.1a.3 .3 0 0 1 0-.3 .3 .3 0 0 1 .2-.2l.4 .1a.31 .31 0 0 1 .2 .3 .31 .31 0 0 1-.3 .2M200.8 170.8l-.3 .3v.3l.3 .3h.3l.3-.3v-.3l-.3-.3M200.8 170.8h.3M202 176.1l-1.3 2M202.5 173.9h.8M202.5 173.2v1.5"/>
<path d="M202.7 170.2h-.7v.7l.2-.1h.5l.1 .3-.1 .5-.2 .1h-.3l-.2-.1M203.3 173.2v1.5M203.5 170.3a.36 .36 0 0 1 .4-.1 .36 .36 0 0 1 .3 .3 .78 .78 0 0 1-.5 1.2 .91 .91 0 0 1-.2-1.4zM203.6 176.1l-1.3 2M204 173.8l.2-.1 .4 .1 .1 .9M204.7 174.1h-.5a.29 .29 0 0 0-.3 .3 .29 .29 0 0 0 .3 .3l.5-.1M204.7 176.8l-.4-.1-.3 .3v.4l.2 .2 .1 .1 .4-.1M204.7 176.7v1.2a.41 .41 0 0 1-.6 .2M204.9 170.8l.1-.1 .5 .1v.9M205.4 173.7v1M205.5 176.2v.1M205.5 176.7v1"/>
<path d="M205.5 176.2l-.1 .1h.1M205.5 171.1h-.5a.29 .29 0 0 0-.2 .3 .29 .29 0 0 0 .2 .3l.5-.1M205.8 173.7l-.3 .1-.1 .2M206 176.7h.5M206.2 176.2v1.3v.1l.3 .1M206.5 170.8l-.3-.1a.3 .3 0 0 1 0-.3 .3 .3 0 0 1 .3-.2l.4 .1a.31 .31 0 0 1 .1 .3 .31 .31 0 0 1-.3 .2M206.5 170.8l-.3 .3v.3l.3 .3h.2l.3-.3v-.3l-.3-.3M206.5 170.8h.2M207 173.8l-.5-.1-.3 .3v.4l.2 .2 .1 .1 .5-.1M207 173.2v1.5M207 176.8a.37 .37 0 0 1 .7 .1v.8M207 176.2v1.5"/>
<path d="M207.5 173.7l.3 1 .3-.7 .3 .7 .3-1M208.3 170.8l-.4-.1-.3 .3v.4l.1 .2 .2 .1 .4-.1M208.4 176.7l.1 .9a.41 .41 0 0 0 .5 0M208.9 170.3l.2-.1 .5 .1a.41 .41 0 0 1 .1 .5l-.9 .9h.9M209 176.7v1M209.2 173.8l.2-.1 .4 .1 .1 .9M209.7 176.8l.5-.1 .3 .3v.4l-.2 .2-.1 .1-.5-.1M209.7 176.2v1.5M209.9 174.1h-.5a.3 .3 0 0 0-.2 .3 .3 .3 0 0 0 .2 .3l.5-.1M210.6 173.7v1M211 173.7l-.3 .1-.1 .2M211.1 177.6h.1l-.1 .1"/>
<path d="M211.1 177.6h-.1l.1 .1M211.1 177.6v.1M211.5 174.2l.7-.1-.1-.3-.4-.1-.2 .2v.7l.2 .1 .4-.1M212.5 176.8l-.5-.1-.3 .3v.4l.2 .2 .1 .1 .5-.1M213.1 176.8a.41 .41 0 0 1 .4-.1 .41 .41 0 0 1 .3 .3v.4a.41 .41 0 0 1-.4 .3 .41 .41 0 0 1-.4-.3zM214 173.2v1.5h.7M214.5 176.8a.37 .37 0 0 1 .6 .1M214.5 176.7v1M215.1 176.9l.2-.2 .4 .1v.9M215.1 176.9v.8M215.2 173.2l-.1 .1h.1M215.2 173.2v.1"/>
<path d="M215.2 173.7v1M216.5 173.8l-.4-.1-.3 .3v.4l.2 .2 .1 .1 .4-.1M217.1 174.2l.7-.1-.1-.3-.4-.1-.2 .2 .1 .7 .1 .1 .4-.1M217.5 176.1l-1.3 2M218 176.7v1.5M218 176.8l.5-.1 .2 .3v.4l-.1 .2-.1 .1-.5-.1M218.5 173.8a.37 .37 0 0 1 .6 .1v.8M218.5 173.7v1M219.3 177.2l.7-.1v-.3l-.5-.1-.2 .2 .1 .7 .1 .1 .5-.1M220.5 173.8l-.5-.1-.3 .3v.4l.2 .2 .1 .1 .5-.1M221 174.2l.7-.1v-.3l-.5-.1-.2 .2 .1 .7 .1 .1 .5-.1M221.3 176.8l-.4-.1-.3 .3v.4l.1 .2 .2 .1 .4-.1"/>
<path d="M221.3 176.2v1.5M222 176.8l.2-.1 .4 .1 .1 .9M222.7 177.1h-.5a.29 .29 0 0 0-.3 .3 .29 .29 0 0 0 .3 .3l.5-.1M223.3 173.2l.5 1.5 .5-1.5M223.4 176.2v1.3l.2 .2M224.2 176.8l.4-.1 .3 .3v.4l-.2 .2-.1 .1-.4-.1M224.2 176.2v1.5M224.7 174.2l.8-.1-.1-.3-.4-.1-.3 .2 .1 .7 .2 .1 .4-.1M225.6 176.8a.41 .41 0 0 1 .6 .2v.4a.41 .41 0 0 1-.3 .3 .41 .41 0 0 1-.4-.3v-.4zM226.1 173.7v1M226.5 173.7l-.3 .1-.1 .2M226.9 176.8l.1-.1 .5 .1v.9"/>
<path d="M227.5 177.1h-.5a.29 .29 0 0 0-.2 .3 .29 .29 0 0 0 .2 .3l.5-.1M227.5 173.8l-.3-.1-.2 .2v.2l.5 .2 .1 .1-.1 .2-.1 .1-.4-.1M228.2 173.2v.1M228.2 173.7v1M228.2 176.7v1M228.2 173.2l.1 .1h-.1M228.7 176.7l-.3 .1-.2 .2M229 173.8a.41 .41 0 0 1 .7 .2v.4a.41 .41 0 0 1-.4 .3 .41 .41 0 0 1-.4-.3v-.4zM229.8 176.8l-.4-.1-.3 .3v.4l.1 .2 .2 .1 .4-.1M229.8 176.2v1.5M230.3 173.8a.37 .37 0 0 1 .7 .1v.8M230.3 173.7v1"/>
<path d="M231.6 176.1l-1.3 2M232.1 176.8l.4-.1 .3 .3v.4l-.1 .2-.2 .1-.4-.1M232.1 176.7v1.5M232.7 173.3l.3-.1 .5 .1a.41 .41 0 0 1 0 .5l-.8 .9h.9M233.4 177.2l.7-.1-.1-.3-.4-.1-.2 .2 .1 .7 .1 .1 .4-.1M235.4 176.8l-.4-.1-.3 .3v.4l.1 .2 .2 .1 .4-.1M235.4 176.2v1.5M235.4 174.1h1.1M236.1 176.8l.1-.1 .5 .1v.9M236.7 177.1h-.5a.29 .29 0 0 0-.2 .3 .29 .29 0 0 0 .2 .3l.5-.1M237.5 176.2v1.3l.2 .2M238.2 176.8l.5-.1 .3 .3v.4l-.2 .2-.1 .1-.5-.1"/>
<path d="M238.2 176.2v1.5M238.4 174h.6a.41 .41 0 0 0 .3-.4 .41 .41 0 0 0-.3-.4h-.6v1.5M239.7 176.8a.41 .41 0 0 1 .6 .2v.4a.41 .41 0 0 1-.4 .3 .41 .41 0 0 1-.4-.3v-.4zM239.8 174.2l.7-.1v-.3l-.5-.1-.2 .2 .1 .7 .1 .1 .5-.1M241 176.8l.1-.1 .4 .1 .1 .9M241.2 173.7v1M241.6 177.1h-.5a.29 .29 0 0 0-.2 .3 .29 .29 0 0 0 .2 .3l.5-.1M241.6 173.7l-.3 .1-.1 .2M242.1 173.8a.37 .37 0 0 1 .6 .1M242.1 173.7v1M242.3 176.7v1M242.7 176.7l-.2 .1-.2 .2"/>
<path d="M242.7 173.9l.3-.2 .3 .1 .1 .9M242.7 173.9v.8M243.9 176.8l-.4-.1-.3 .3v.4l.1 .2 .2 .1 .4-.1M243.9 176.2v1.5M244.1 173.2l-.1 .1h.1M244.1 173.2v.1M244.1 173.7v1M244.1 173.2l.1 .1h-.1M244.6 177.1h1.1M245.3 173.8l-.3-.1-.3 .2 .1 .2 .5 .2 .1 .1-.1 .2-.1 .1-.5-.1M246.5 176.8a.37 .37 0 0 1 .6 .1v.8M246.5 176.2v1.5"/>
<path d="M246.5 173.8l-.3-.1-.2 .2v.2l.5 .2 .1 .1-.1 .2-.1 .1-.4-.1M247.2 173.2v.1M247.2 173.7v1M247.2 173.2l.1 .1h-.1M247.7 176.7l.3 1 .2-.7 .3 .7 .3-1M247.8 173.7l.4 1 .3-1M249 174.2l.7-.1v-.3l-.5-.1-.2 .2 .1 .7 .1 .1 .5-.1M10.7 184.3a.66 .66 0 0 1 .7 .6 .66 .66 0 0 1-.7 .7zM35.3 198.7l.4-.4v1.3M35.3 199.6h.8M60 198v2M85.3 198.4l.2-.1 .5 .1a.35 .35 0 0 1 0 .5l-.7 .7h.8"/>
<path d="M110 198v2M135.3 198.3h.8l-.4 .5a.35 .35 0 0 1 .4 .2v.4l-.1 .1-.5 .1-.2-.1M160 198v2M177 194.5h108M177 191.5h108M177 187.5h108M177 181.5h108M178.5 185.6h.5M178.5 195.1v1.5M178.7 195.7l.6 .9M179.2 184.9h-.7v1.5M179.2 192.4l-.5-.1a.36 .36 0 0 0-.3 .4 .36 .36 0 0 0 .3 .3 .55 .55 0 0 1 .5 .4v.3l-.2 .1-.6-.1"/>
<path d="M179.2 182.3l-.5-.1a.36 .36 0 0 0-.3 .4 .36 .36 0 0 0 .3 .3 .55 .55 0 0 1 .5 .4v.3l-.2 .1-.6-.1M179.3 195.1l-.8 .9M179.7 184.9v.1M179.7 185.4v1M179.7 184.9l.1 .1h-.1M179.9 182.2v1.5M179.9 192.3v.1M179.9 192.8v1M179.9 192.3l-.1 .1h.1M179.9 192.3l.1 .1h-.1M179.9 182.8a.37 .37 0 0 1 .6 .1v.8M180 195.1v.1"/>
<path d="M180 195.6v1M180 195.1l-.1 .1h.1M180.5 192.8h.7l-.7 1h.7M180.5 184.9v1.3l.2 .2M181.2 183.2l.7-.1-.1-.3-.4-.1-.2 .2v.7l.2 .1 .4-.1M181.2 185.9l.7-.2-.1-.2-.4-.1-.2 .2v.7l.2 .1 .4-.1M181.5 195.2a.6 .6 0 0 0-.7 0 .6 .6 0 0 0-.2 .8 .56 .56 0 0 0 .3 .5 .56 .56 0 0 0 .6 0M181.7 193.3l.8-.1-.1-.3-.4-.1-.3 .2 .1 .7 .2 .1 .4-.1M182.2 195.7l.1-.1 .4 .1 .1 .9M182.5 183.2l.7-.1-.1-.3-.4-.1-.2 .2v.7l.2 .1 .4-.1M182.5 186.3h.1l-.1 .1M182.5 186.3v.1"/>
<path d="M182.5 185.5v.1M182.5 185.5h.1l-.1 .1M182.8 196h-.5a.29 .29 0 0 0-.2 .3 .29 .29 0 0 0 .2 .3l.5-.1M183.1 193.7h.1l-.1 .1M183.1 193.7h-.1l.1 .1M183.1 192.9v.1M183.1 193.7v.1M183.1 192.9h.1l-.1 .1M183.1 192.9h-.1l.1 .1M183.6 182.7h.6M183.8 182.2v1.3l.1 .1 .3 .1M184.2 195.7l-.5-.1-.2 .3v.4l.1 .2 .1 .1 .5-.1"/>
<path d="M184.2 195.1v1.5M184.4 185.5l.4-.1 .3 .3v.4l-.1 .2-.2 .1-.4-.1M184.4 185.4v1.5M184.7 183.6v.1M184.7 183.6h-.1l.1 .1M184.7 182.8v.1M184.7 182.8h-.1l.1 .1M184.7 193.8l.5-1.5 .5 1.5M184.9 193.4h.7M185.7 198.2l-.4 1h.9M185.7 185.9l.7-.2-.1-.2-.4-.1-.2 .2v.7l.2 .1 .4-.1M186 198.7v.9"/>
<path d="M186 195.8h.5M186.5 192.2l-.3 1.1h.9M186.5 182.2l.7 .1a.36 .36 0 0 1 .1 .3 .36 .36 0 0 1-.3 .3 .4 .4 0 0 1 .4 .4 .4 .4 0 0 1-.3 .4h-.6zM186.5 182.9h.5M186.7 195.1h-.7v1.5h.7M186.9 192.8v1M187.4 196.5h.1l-.1 .1M187.4 196.5h-.1l.1 .1M187.4 196.5v.1M187.7 185.5l-.5-.1-.2 .3v.4l.1 .2 .1 .1 .5-.1M187.7 184.9v1.5M188 182.8a.41 .41 0 0 1 .4-.1 .41 .41 0 0 1 .3 .3v.4a.41 .41 0 0 1-.3 .3 .41 .41 0 0 1-.4-.3z"/>
<path d="M188.1 195.1a.79 .79 0 0 1 .9 .5 .79 .79 0 0 1-.3 .9l-.6 .1zM188.4 185.5l.1-.1 .5 .1v.9M189 185.7l-.5 .1a.3 .3 0 0 0-.2 .3 .3 .3 0 0 0 .2 .3l.5-.1M189.2 182.7h.5M189.4 182.2v1.3l.1 .1 .2 .1M189.6 196.5h.1l-.1 .1M189.6 196.5h-.1l.1 .1M189.6 196.5v.1M189.7 184.9v1.3l.3 .2M190 182.7h.6M190.1 196.6l.5-1.5 .5 1.5M190.2 196.2h.8"/>
<path d="M190.2 182.2v1.3l.1 .1 .3 .1M190.5 185.5l.5-.1 .2 .3v.4l-.1 .2-.1 .1-.5-.1M190.5 184.9v1.5M191.1 182.8a.41 .41 0 0 1 .4-.1 .41 .41 0 0 1 .3 .3v.4a.41 .41 0 0 1-.4 .3 .41 .41 0 0 1-.4-.3zM191.6 196.5h.1l-.1 .1M191.6 196.5h-.1l.1 .1M191.6 196.5v.1M191.9 185.5a.41 .41 0 0 1 .4-.1 .41 .41 0 0 1 .3 .3v.4a.41 .41 0 0 1-.4 .3 .41 .41 0 0 1-.4-.3zM192.5 182.8a.37 .37 0 0 1 .6 .1M192.5 182.7v1M193.1 182.9l.2-.2 .4 .1v.9M193.1 182.9v.8"/>
<path d="M193.2 185.5l.2-.1 .4 .1 .1 .9M193.4 196.6h.8M193.4 195.5l.4-.4v1.5M193.9 185.7l-.5 .1a.29 .29 0 0 0-.2 .3 .29 .29 0 0 0 .2 .3l.5-.1M194.6 185.4v1M195 195.2a.36 .36 0 0 1 .3-.1 .36 .36 0 0 1 .3 .3 .77 .77 0 0 1-.4 1.2 .91 .91 0 0 1-.2-1.4zM195 185.4l-.3 .1-.1 .2M196.2 185.5l-.5-.1-.2 .3v.4l.1 .2 .1 .1 .5-.1M196.2 184.9v1.5M196.2 182.8l-.4-.1-.3 .3v.4l.2 .2 .1 .1 .4-.1M196.2 182.2v1.5M196.3 196.5h.1l-.1 .1"/>
<path d="M196.3 196.5h-.1l.1 .1M196.3 196.5v.1M196.9 185.8h1.1M197 191.5v3M197 182.8a.41 .41 0 0 1 .7 .2v.4a.41 .41 0 0 1-.4 .3 .41 .41 0 0 1-.4-.3v-.4zM197.1 195.2a.36 .36 0 0 1 .4-.1 .36 .36 0 0 1 .2 .3 .77 .77 0 0 1-.4 1.2 .91 .91 0 0 1-.2-1.4zM198.5 196.5v.1M198.5 196.5h-.1l.1 .1M198.7 185.5a.37 .37 0 0 1 .7 .1v.8M198.7 184.9v1.5M199 182.8l-.5-.1-.3 .3v.4l.2 .2 .1 .1 .5-.1M199.1 196.6h.9"/>
<path d="M199.1 195.5l.4-.4v1.5M199.6 182.7l.1 .9a.41 .41 0 0 0 .5 0M200 185.4l.2 1 .3-.7 .3 .7 .3-1M200.2 182.7v1M200.5 192.3a.79 .79 0 0 1 .8 .5 .79 .79 0 0 1-.3 .9l-.5 .1zM200.6 196h1.1M201 182.8a.37 .37 0 0 1 .6 .1M201 182.7v1M201.6 182.9l.2-.2 .4 .1v.9M201.6 182.9v.8M201.7 186.3v.1M201.7 186.3h-.1l.1 .1"/>
<path d="M202 192.9l.1-.1 .4 .1 .1 .9M202.4 196.6h.8M202.4 195.5l.4-.4v1.5M202.4 184.9v1.5M202.5 185.8l.5 .6M202.6 193.2h-.5a.29 .29 0 0 0-.2 .3 .29 .29 0 0 0 .2 .3l.5-.1M202.9 183.2l.7-.1-.1-.3-.4-.1-.2 .2 .1 .7 .1 .1 .4-.1M203 185.4l-.6 .6M203.1 192.8h.6M203.3 192.3v1.3l.1 .1 .3 .1M203.6 184.9v.1M203.6 185.4v1"/>
<path d="M203.6 184.9l-.1 .1h.1M203.6 184.9l.1 .1h-.1M204 195.2a.36 .36 0 0 1 .3-.1 .36 .36 0 0 1 .3 .3 .77 .77 0 0 1-.4 1.2 .91 .91 0 0 1-.2-1.4zM204.1 193.3l.7-.1-.1-.3-.4-.1-.2 .2 .1 .7 .1 .1 .4-.1M204.2 182.7v1M204.2 182.8a.37 .37 0 0 1 .7 .1v.8M205 185.5l-.5-.1-.3 .3v.4l.2 .2 .1 .1 .5-.1M205.3 196.5h.1l-.1 .1M205.3 196.5h-.1l.1 .1M205.3 196.5v.1M205.4 182.7h.6M205.5 193.7v.1"/>
<path d="M205.5 193.7h-.1l.1 .1M205.5 192.9v.1M205.5 192.9h-.1l.1 .1M205.6 185.5l.1-.1 .5 .1v.9M205.6 182.2v1.3l.1 .1 .3 .1M206.1 195.2a.36 .36 0 0 1 .4-.1 .36 .36 0 0 1 .2 .3 .77 .77 0 0 1-.4 1.2 .91 .91 0 0 1-.2-1.4zM206.2 185.7l-.5 .1a.29 .29 0 0 0-.2 .3 .29 .29 0 0 0 .2 .3l.5-.1M206.5 182.8l.1-.1 .4 .1 .1 .9M207.1 183.1h-.5a.29 .29 0 0 0-.2 .3 .29 .29 0 0 0 .2 .3l.5-.1M207.2 192.4l.3-.1 .5 .1a.41 .41 0 0 1 0 .5l-.8 .9h.9M207.5 196.5v.1M207.5 196.5h-.1l.1 .1"/>
<path d="M207.6 185.5l-.4-.1-.3 .3v.4l.1 .2 .2 .1 .4-.1M207.6 184.9v1.5M207.6 182.7h.6M207.8 182.2v1.3l.1 .1 .3 .1M208 186.5h1.1M208.1 196.6h.9M208.1 195.5l.4-.4v1.5M208.7 182.2v.1M208.7 182.7v1M208.7 182.2l-.1 .1h.1M208.9 192.4a.35 .35 0 0 1 .6 .2 .77 .77 0 0 1-.5 1.2 1 1 0 0 1-.1-1.4zM209.4 194.7h15.9"/>
<path d="M209.5 182.8a.41 .41 0 0 1 .6 .2v.4a.41 .41 0 0 1-.4 .3 .41 .41 0 0 1-.4-.3v-.4zM209.5 185.5l.4-.1 .3 .3v.4l-.2 .2-.1 .1-.4-.1M209.5 185.4v1.5M209.6 195.6l.1 .9a.41 .41 0 0 0 .5 0M210 198v2M210.1 192.4l.2-.1 .5 .1a.41 .41 0 0 1 .1 .5l-.9 .9h1M210.2 195.6v1M210.7 182.7v1M210.7 182.8a.37 .37 0 0 1 .7 .1v.8M211 195.1v1.5M211 195.7l.4-.1 .3 .3v.4l-.2 .2-.1 .1-.4-.1M211.5 185.5l-.5-.1-.3 .3v.4l.2 .2 .1 .1 .5-.1"/>
<path d="M211.9 192.2l-.4 1.1h1M212.1 185.5l.4-.1 .3 .3v.4l-.1 .2-.2 .1-.4-.1M212.1 184.9v1.5M212.2 192.8v1M212.3 195.6l.1 .9a.41 .41 0 0 0 .6 0M213 195.6v1M213 193.2h1.2M213.7 195.7a.37 .37 0 0 1 .6 .1v.8M213.7 195.6v1M214.8 193.8h.9M214.8 192.7l.4-.4v1.5M214.8 195.6h.6"/>
<path d="M215 195.1v1.3l.1 .1 .3 .1M215.9 195.6l.1 .9a.41 .41 0 0 0 .5 0M216.5 192.4a.36 .36 0 0 1 .5 .2 .77 .77 0 0 1-.4 1.2 1 1 0 0 1-.1-1.4zM216.5 195.6v1M217.2 195.2l.2-.1 .5 .1a.41 .41 0 0 1 .1 .5l-.9 .9h.9M217.7 193.2h1.2M219.4 195.1h-.7l-.1 .7 .2-.1h.5l.2 .3-.1 .5-.2 .1h-.4l-.2-.1M219.5 193.8h.9M219.5 192.7l.5-.4v1.5M220.1 196.5h.1l-.1 .1M220.1 196.5h-.1l.1 .1M220.1 196.5v.1"/>
<path d="M220.7 196.6h.9M220.7 195.5l.5-.4v1.5M221.7 192.3a.6 .6 0 0 0-.7 .6v.6l.1 .2 .4 .1 .2-.1 .1-.5-.1-.3h-.5l-.2 .3M222.3 195.2a.36 .36 0 0 1 .4-.1 .36 .36 0 0 1 .3 .3 .77 .77 0 0 1-.5 1.2 .91 .91 0 0 1-.2-1.4zM223.7 196.5v.1M223.7 196.5h-.1l.1 .1M224.3 196.6h.9M224.3 195.5l.4-.4v1.5M227 196h1.1M227.5 195.4v1.2M230 195.1v1.5M230.2 195.7l.6 .9"/>
<path d="M230.8 195.1l-.8 .9M231.5 195.1v.1M231.5 195.6v1M231.5 195.1l-.1 .1h.1M232.2 195.1l.6 .1a.36 .36 0 0 1 .2 .3 .36 .36 0 0 1-.3 .3 .4 .4 0 0 1 .3 .4 .4 .4 0 0 1-.3 .4h-.5zM232.2 195.8h.5M233.7 195.7a.41 .41 0 0 1 .7 .2v.4a.41 .41 0 0 1-.4 .3 .41 .41 0 0 1-.4-.3v-.4zM234.8 195.6h.6M235 195.1v1.3l.1 .1 .3 .1M236 198.3h-.6l-.1 .6 .2-.1 .5 .1 .1 .1-.1 .5-.2 .1h-.3l-.2-.1M236.9 195.6l.3 1 .4-1M238.1 196.6h.9"/>
<path d="M238.1 195.5l.4-.4v1.5M239.6 196.5h.1l-.1 .1M239.6 196.5h-.1l.1 .1M239.6 196.5v.1M241.1 195.7l-.3 .3h-.3l-.3-.3v-.3l.2-.2 .4-.1 .2 .1a.99 .99 0 0 1-.3 1.4h-.3M241.7 196.5h.1l-.1 .1M241.7 196.5v.1M242.5 195.2a.36 .36 0 0 1 .4-.1 .36 .36 0 0 1 .3 .3 .77 .77 0 0 1-.5 1.2 .91 .91 0 0 1-.2-1.4zM260 198v2M261 191.5v6.5M263.5 195.1v1.5M264.8 195.7l-.4-.1-.3 .3v.4l.1 .2 .2 .1 .4-.1"/>
<path d="M264.8 195.1v1.5M265.5 196.5h.1l-.1 .1M265.5 196.5v.1M265.5 195.7v.1M265.5 195.7h.1l-.1 .1M268.1 195.1h-.7l-.1 .7 .2-.1h.5l.2 .3-.1 .5-.2 .1h-.4l-.2-.1M269.9 195l-1.3 2M271 195.1a.6 .6 0 0 0-.7 .6v.6l.2 .2 .4 .1 .2-.1 .1-.5-.2-.3h-.4l-.3 .3M285.7 184.3a.66 .66 0 0 1 .7 .6 .66 .66 0 0 1-.7 .7zM286 198.3a.52 .52 0 0 0-.7 .6v.5l.2 .1 .3 .1 .2-.1 .1-.5-.1-.1-.4-.1-.3 .2"/>
</g>
<g fill="none" stroke="#480000" stroke-width=".3">
<path d="M178.6 179.2v1.5M178.6 179.8a.37 .37 0 0 1 .6 .1v.8M179.7 179.7h.6M179.9 179.2v1.3l.1 .1 .3 .1M180.6 179.7h.5M180.8 179.2v1.3v.1l.3 .1M181.6 179.8l.5-.1 .2 .3v.4l-.1 .2-.1 .1-.5-.1M181.6 179.7v1.5M183.5 179.8l-.4-.1-.2 .2 .1 .2 .5 .2 .1 .1-.1 .2-.2 .1-.4-.1M184.2 179.8v.1M184.2 179.8h.1l-.1 .1M184.2 179.8h-.1l.1 .1"/>
<path d="M186 179.1l-1.3 1.9M187.6 179.1l-1.3 1.9M188.7 179.8l-.4-.1-.3 .3v.4l.1 .2 .2 .1 .4-.1M188.7 179.7v1.2a.41 .41 0 0 1-.6 .2M189.4 179.2v.1M189.4 179.7v1M189.4 179.2l-.1 .1h.1M189.4 179.2l.1 .1h-.1M189.9 179.7h.6M190.1 179.2v1.3l.1 .1 .3 .1M191 179.8a.37 .37 0 0 1 .6 .1v.8M191 179.2v1.5"/>
<path d="M192.3 179.7l.1 .9a.41 .41 0 0 0 .6-.1M193 179.7v1M193.7 179.8l.4-.1 .3 .3v.4l-.1 .2-.2 .1-.4-.1M193.7 179.2v1.5M196.4 179.8l-.4-.1-.3 .3v.4l.1 .2 .2 .1 .4-.1M197.1 179.8a.41 .41 0 0 1 .4-.1 .41 .41 0 0 1 .3 .3v.4a.41 .41 0 0 1-.4 .3 .41 .41 0 0 1-.4-.3zM198.4 179.8a.37 .37 0 0 1 .7 .1M198.4 179.7v1M199.1 179.9l.2-.2 .3 .1 .1 .9M199.1 179.9v.8M201.5 179.1l-1.3 1.9M202 179.8l.4-.1 .3 .3v.4l-.1 .2-.2 .1-.4-.1"/>
<path d="M202 179.7v1.5M205.3 179.8l-.5-.1-.2 .3v.4l.1 .2 .1 .1 .5-.1M205.3 179.2v1.5M206 179.8l.1-.1 .5 .1v.9M207.3 179.2v1.3l.3 .2M208.1 179.8l.5-.1 .2 .3v.4l-.1 .2-.1 .1-.5-.1M208.1 179.2v1.5M209.5 179.8a.41 .41 0 0 1 .4-.1 .41 .41 0 0 1 .3 .3v.4a.41 .41 0 0 1-.4 .3 .41 .41 0 0 1-.4-.3zM210.8 179.8l.2-.1 .4 .1 .1 .9M212.2 179.7v1M212.6 179.7a.38 .38 0 0 0-.4 .3M213.8 179.8l-.5-.1-.2 .3v.4l.1 .2 .1 .1 .5-.1"/>
<path d="M213.8 179.2v1.5M184.2 180.5l.1 .1-.1 .1M184.2 180.5l-.1 .1 .1 .1M184.2 180.5v.2M195.1 180.5v.1v.1M195.1 180.5l-.1 .1 .1 .1M195.1 180.5v.2M203.3 180.2l.7-.2-.1-.2-.4-.1-.2 .2v.7l.2 .1 .4-.1M206.6 180l-.5 .1a.29 .29 0 0 0-.2 .3 .29 .29 0 0 0 .2 .3l.5-.1M211.5 180l-.5 .1a.29 .29 0 0 0-.2 .3 .29 .29 0 0 0 .2 .3l.5-.1M263.6 193.1h.5a.41 .41 0 0 0 .3-.4 .41 .41 0 0 0-.3-.4h-.5v1.5M263.9 193.1l.5 .7"/>
<path d="M265 193.3l.7-.2-.1-.2-.4-.1-.2 .2 .1 .7 .1 .1 .4-.1M266.2 192.8l.4 1 .3-1M267.5 193.6l.1 .1-.1 .1M267.5 193.6l-.1 .1 .1 .1M267.5 192.9v.1M267.5 193.6v.2M267.5 192.9h.1l-.1 .1M267.5 192.9h-.1l.1 .1M270 192.9l-.4-.1-.3 .3v.4l.1 .2 .2 .1 .4-.1M270 192.3v1.5M270.6 193.3l.7-.2v-.2l-.5-.1-.2 .2 .1 .7 .1 .1 .5-.1M271.8 192.8l.4 1 .4-1"/>
</g>
<g fill="none" stroke="#480000" stroke-width=".4">
<path d="M178.7 188.2h1.1M179.3 188.2l-.3 2M180.4 188.9l-.1 1.3M180.5 188.2l-.1 .1 .1 .1M180.5 188.2l.1 .1-.1 .1M180.5 188.2v.2M181.1 188.9h.7M181.5 188.2l-.3 1.7 .1 .2 .4 .1M182.6 188.2l-.2 1.7 .1 .2 .1 .1M183.4 189.5l1-.1-.1-.4-.2-.1-.5 .1-.2 .2-.1 .7 .1 .2 .2 .1 .6-.1M185.1 190l.1 .1-.1 .1M185.1 190l-.1 .1 .1 .1"/>
<path d="M185.1 190v.2M185.3 189l-.1 .2M185.3 189v.1l-.1 .1M185.3 189l-.1 .1v.1M187.8 188.5a.69 .69 0 0 1 1.1 0 1.67 1.67 0 0 1-.3 1.6l-.3 .1-.5-.1a1.5 1.5 0 0 1 0-1.6zM189.8 189l.2-.1 .6 .1 .2 .3-.1 .5a.66 .66 0 0 1-1 .3M189.8 188.9l-.2 2M191.5 189.5l1-.1-.1-.4-.6-.1-.3 .3-.1 .7 .1 .2 .2 .1 .6-.1M193.3 189.1a.49 .49 0 0 1 .9 .1l-.1 1M193.4 188.9l-.2 1.3M196.7 189.3h.7a.55 .55 0 0 0 .5-.5 .55 .55 0 0 0-.3-.6h-.8l-.3 2M198.5 189.5l1-.1v-.4l-.6-.1-.3 .3-.1 .7 .1 .2 .1 .1 .6-.1"/>
<path d="M201.3 189a.66 .66 0 0 0-1 .3l-.1 .5 .2 .3 .1 .1 .6-.1M201.4 188.2l-.3 2M202.2 189l.2-.1 .6 .1 .1 .2-.2 1M203 189.4h-.7a.4 .4 0 0 0-.3 .4 .4 .4 0 0 0 .3 .4l.6-.1M204.1 188.2l-.2 1.7 .1 .2 .2 .1M205.1 189l.2-.1 .5 .1 .2 .3-.1 .5a.66 .66 0 0 1-1 .3M205.2 188.2l-.3 2M206.9 189.1a.52 .52 0 0 1 .5-.2 .52 .52 0 0 1 .4 .4l-.1 .5a.55 .55 0 0 1-.5 .4 .55 .55 0 0 1-.5-.4l.1-.5zM208.7 189l.2-.1 .6 .1v.2l-.1 1M209.5 189.4h-.7a.4 .4 0 0 0-.3 .4 .4 .4 0 0 0 .2 .4l.7-.1M210.5 188.9l-.2 1.3M211.1 188.9a.59 .59 0 0 0-.6 .4"/>
<path d="M212.6 189a.66 .66 0 0 0-1 .3l-.1 .5 .2 .3 .2 .1 .6-.1M212.7 188.2l-.3 2M214.9 190.2l.3-2 .5 1.4 .8-1.4-.2 2M217.4 189l.2-.1 .5 .1 .1 .2-.1 1M218.2 189.4h-.7a.4 .4 0 0 0-.3 .4 .4 .4 0 0 0 .2 .4l.7-.1M219.2 188.9l-.2 1.3M219.3 188.2l-.1 .1v.1M219.3 188.2v.1l-.1 .1M219.3 188.2l-.1 .2M220.1 189.1a.49 .49 0 0 1 .9 .1l-.2 1M220.1 188.9l-.1 1.3M221.9 189l.2-.1 .6 .1 .1 .3v.5a.66 .66 0 0 1-1 .3"/>
<path d="M222 188.2l-.2 2M223.7 189.1a.52 .52 0 0 1 .6-.2 .52 .52 0 0 1 .4 .4l-.1 .5a.55 .55 0 0 1-.5 .4 .55 .55 0 0 1-.6-.4l.1-.5zM225.6 189l.2-.1 .5 .1 .1 .2-.1 1M226.4 189.4h-.7a.4 .4 0 0 0-.4 .4 .4 .4 0 0 0 .3 .4l.7-.1M227.4 188.9l-.2 1.3M227.9 188.9a.59 .59 0 0 0-.6 .4M229.5 189a.66 .66 0 0 0-1 .3l-.1 .5 .2 .3 .1 .1 .6-.1M229.6 188.2l-.3 2"/>
</g>
<use href="#words"/>
</svg>
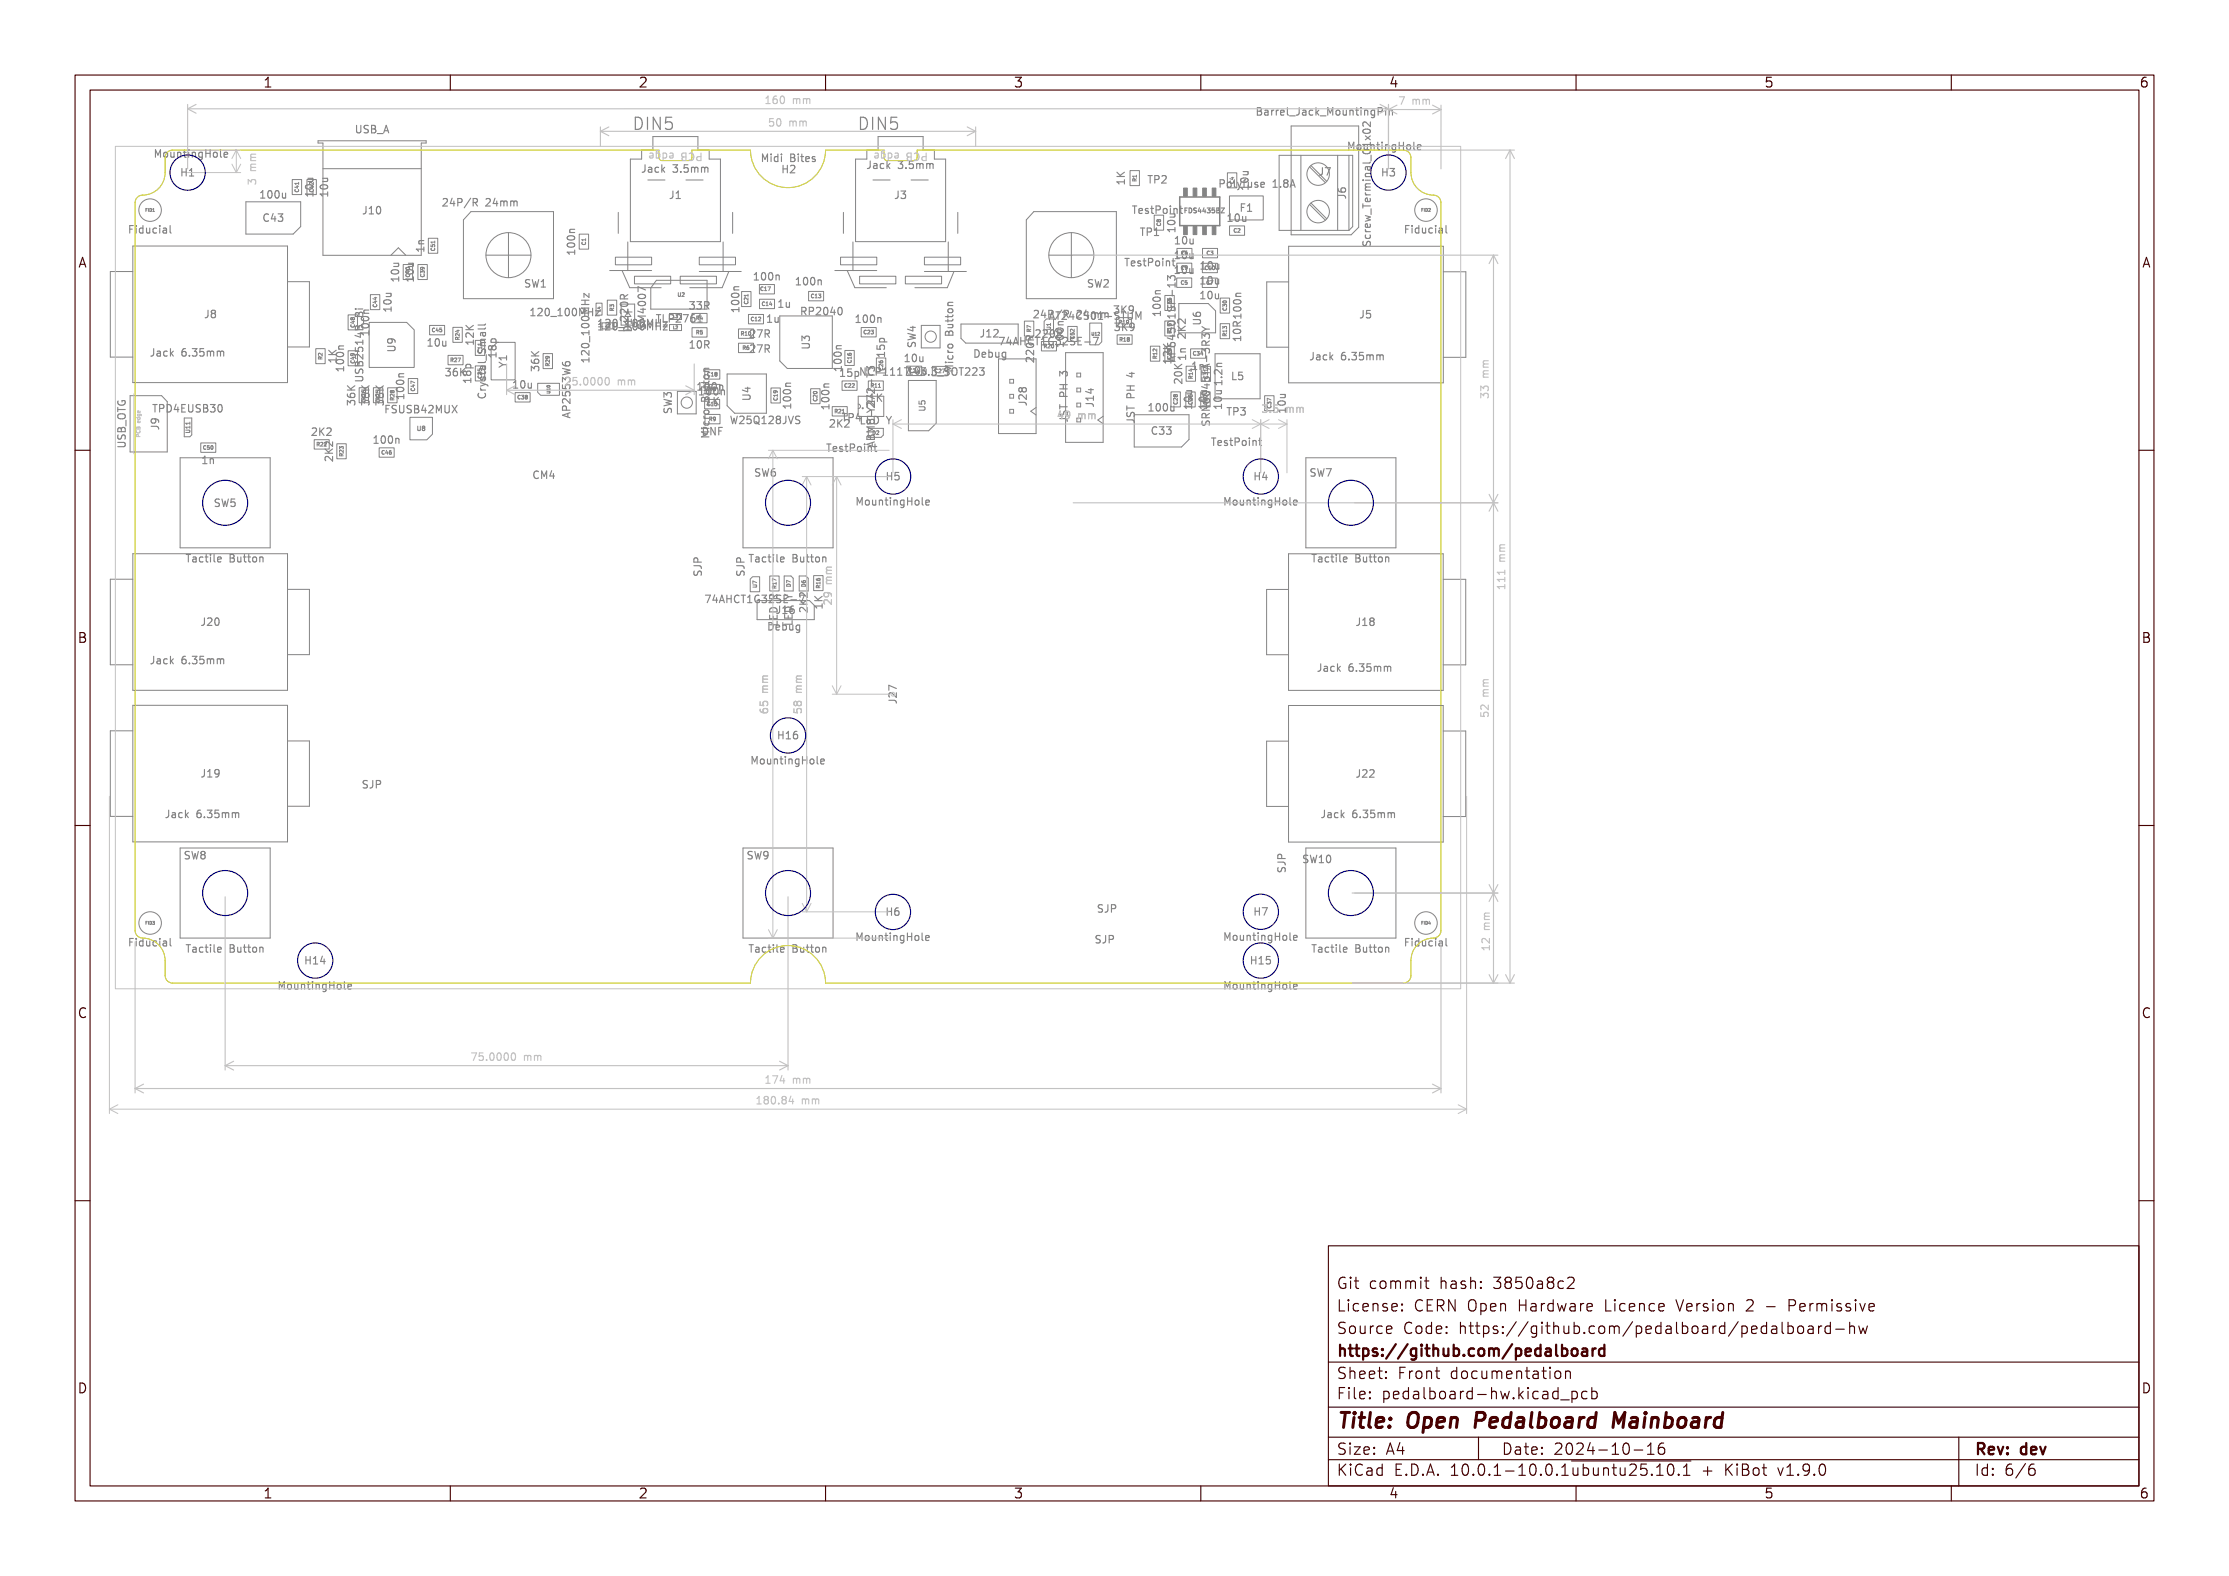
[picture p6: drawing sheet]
<svg xmlns="http://www.w3.org/2000/svg" width="297mm" height="210mm" viewBox="0 0 297 210" stroke-linecap="round" stroke-linejoin="round" font-family="sans-serif">
<defs><g id="words">
<text font-size="2.7" fill="#fff" x="178" y="190.3">Title: Open Pedalboard Mainboard</text>
<g font-size="2.2" fill="#fff">
<text x="84.8" y="17.3">DIN5</text>
<text x="114.8" y="17.3">DIN5</text>
</g>
<g font-size="2" fill="#fff">
<text x="178" y="171.8">Git commit hash: 3850a8c2</text>
<text x="178" y="174.8">License: CERN Open Hardware Licence Version 2 - Permissive</text>
<text x="178" y="177.8">Source Code: https://github.com/pedalboard/pedalboard-hw</text>
<text x="178" y="180.8">https://github.com/pedalboard</text>
<text x="178" y="183.8">Sheet: Front documentation</text>
<text x="178" y="186.5">File: pedalboard-hw.kicad_pcb</text>
<text x="178" y="193.9">Size: A4</text>
<text x="178" y="196.7">KiCad E.D.A. 10.0.1-10.0.1~{ubuntu25.10.1} + KiBot v1.9.0</text>
<text x="200" y="193.9">Date: 2024-10-16</text>
<text x="263" y="196.7">Id: 6/6</text>
<text x="263" y="193.9">Rev: dev</text>
</g>
<g font-size="1.7" fill="#fff">
<text x="35" y="11.6">1</text>
<text x="85" y="11.6">2</text>
<text x="135" y="11.6">3</text>
<text x="185" y="11.6">4</text>
<text x="235" y="11.6">5</text>
<text x="285" y="11.6">6</text>
<text x="10.5" y="35.6">A</text>
<text x="285.5" y="35.6">A</text>
<text x="10.5" y="85.6">B</text>
<text x="285.5" y="85.6">B</text>
<text x="10.5" y="135.6">C</text>
<text x="285.5" y="135.6">C</text>
<text x="10.5" y="185.6">D</text>
<text x="285.5" y="185.6">D</text>
<text x="35" y="199.7">1</text>
<text x="85" y="199.7">2</text>
<text x="135" y="199.7">3</text>
<text x="185" y="199.7">4</text>
<text x="235" y="199.7">5</text>
<text x="285" y="199.7">6</text>
</g>
<g font-size="1.3" fill="#fff">
<text x="47.6" y="17.7">USB_A</text>
<text x="102.6" y="13.8">160 mm</text>
<text x="103" y="16.8">50 mm</text>
<text x="167.3" y="15.4">Barrel_Jack_MountingPin</text>
<text x="186.9" y="13.9">7 mm</text>
<text x="20.7" y="21">MountingHole</text>
<text x="24.2" y="23.5">H1</text>
<text x="86" y="23">Jack 3.5mm</text>
<text x="93.2" y="20.4" transform="rotate(180 93.2 20.4)">PCB edge</text>
<text x="101.1" y="21.6">Midi Bites</text>
<text x="104.3" y="23.1">H2</text>
<text x="116" y="22.5">Jack 3.5mm</text>
<text x="123.2" y="20.4" transform="rotate(180 123.2 20.4)">PCB edge</text>
<text x="175.7" y="23.4">J7</text>
<text x="179.7" y="20">MountingHole</text>
<text x="184.2" y="23.5">H3</text>
<text x="34.1" y="24.1" transform="rotate(-90 34.1 24.1)">3 mm</text>
<text x="34.8" y="26.4">100u</text>
<text x="35.2" y="29.5">C43</text>
<text x="41.7" y="26.1" transform="rotate(-90 41.7 26.1)">10u</text>
<text x="43.7" y="26.1" transform="rotate(-90 43.7 26.1)">10u</text>
<text x="48.4" y="28.5">J10</text>
<text x="60" y="27.5">24P/R 24mm</text>
<text x="89.2" y="26.5">J1</text>
<text x="119.2" y="26.5">J3</text>
<text x="149.9" y="24.5" transform="rotate(-90 149.9 24.5)">1K</text>
<text x="150.6" y="28.5">TestPoint</text>
<text x="153" y="24.4">TP2</text>
<text x="162.3" y="25">Polyfuse 1.8A</text>
<text x="163.6" y="29.5">10u</text>
<text x="165.3" y="28.2">F1</text>
<text x="166.3" y="25.2" transform="rotate(-90 166.3 25.2)">10u</text>
<text x="179.3" y="26.5" transform="rotate(-90 179.3 26.5)">J6</text>
<text x="16.8" y="31.1">Fiducial</text>
<text x="56.5" y="33.6" transform="rotate(-90 56.5 33.6)">1n</text>
<text x="76.6" y="33.8" transform="rotate(-90 76.6 33.8)">100n</text>
<text x="149.6" y="35.5">TestPoint</text>
<text x="152" y="31.4">TP1</text>
<text x="156.6" y="34.5">10u</text>
<text x="156.6" y="30.9" transform="rotate(-90 156.6 30.9)">10u</text>
<text x="156.6" y="32.5">10u</text>
<text x="160" y="35.9">10u</text>
<text x="182.6" y="32.5" transform="rotate(-90 182.6 32.5)">Screw_Terminal_01x02</text>
<text x="186.8" y="31.1">Fiducial</text>
<text x="52.2" y="41.5" transform="rotate(-90 52.2 41.5)">10u</text>
<text x="53.2" y="37.5" transform="rotate(-90 53.2 37.5)">10u</text>
<text x="55.1" y="37.5" transform="rotate(-90 55.1 37.5)">10u</text>
<text x="70.1" y="38.3">SW1</text>
<text x="92" y="41.2">33R</text>
<text x="98.5" y="41.5" transform="rotate(-90 98.5 41.5)">100n</text>
<text x="100.6" y="37.4">100n</text>
<text x="103.7" y="41">1u</text>
<text x="106.2" y="38">100n</text>
<text x="107.1" y="42">RP2040</text>
<text x="145.1" y="38.3">SW2</text>
<text x="148.5" y="41.8">3K9</text>
<text x="154.7" y="42" transform="rotate(-90 154.7 42)">100n</text>
<text x="156.6" y="36.5">10u</text>
<text x="160" y="39.9">10u</text>
<text x="160" y="37.9">10u</text>
<text x="20.6" y="47.5">Jack 6.35mm</text>
<text x="27.2" y="42.4">J8</text>
<text x="49.2" y="44.6" transform="rotate(-90 49.2 44.6)">100n</text>
<text x="52.7" y="46.8" transform="rotate(-90 52.7 46.8)">U9</text>
<text x="57" y="46.2">10u</text>
<text x="63.1" y="45.8" transform="rotate(-90 63.1 45.8)">12K</text>
<text x="66.1" y="47.6" transform="rotate(-90 66.1 47.6)">18p</text>
<text x="71.3" y="42.1">120_100MHz</text>
<text x="78.5" y="47.7" transform="rotate(-90 78.5 47.7)">120_100MHz</text>
<text x="80.3" y="44">120_100MHz</text>
<text x="80.3" y="43.6">120_100MHz</text>
<text x="83.7" y="42.6" transform="rotate(-90 83.7 42.6)">220R</text>
<text x="84.2" y="44.1" transform="rotate(-90 84.2 44.1)">D1</text>
<text x="86.1" y="43.4" transform="rotate(-90 86.1 43.4)">SM4007</text>
<text x="87.8" y="43">TLP2761</text>
<text x="92" y="46.4">10R</text>
<text x="100.1" y="47">27R</text>
<text x="100.1" y="45">27R</text>
<text x="102.2" y="43">1u</text>
<text x="107.9" y="46.4" transform="rotate(-90 107.9 46.4)">U3</text>
<text x="114.1" y="43">100n</text>
<text x="117.9" y="47.5" transform="rotate(-90 117.9 47.5)">15p</text>
<text x="122" y="46.1" transform="rotate(-90 122 46.1)">SW4</text>
<text x="129.9" y="47.6">Debug</text>
<text x="130.7" y="44.9">J12</text>
<text x="134.1" y="46">74AHCT1G32SE-7</text>
<text x="138.2" y="45">220R</text>
<text x="138.7" y="42.4">24P/R 24mm</text>
<text x="140.8" y="42.6">AT24CS01-STUM</text>
<text x="141.7" y="46.1" transform="rotate(-90 141.7 46.1)">100n</text>
<text x="148.6" y="44.1">3K9</text>
<text x="156.6" y="47.2" transform="rotate(-90 156.6 47.2)">AP64501SP-13</text>
<text x="158" y="45" transform="rotate(-90 158 45)">2K2</text>
<text x="158" y="48" transform="rotate(-90 158 48)">1n</text>
<text x="160" y="43.2" transform="rotate(-90 160 43.2)">U6</text>
<text x="165.4" y="45.3" transform="rotate(-90 165.4 45.3)">10R 100n</text>
<text x="175.1" y="48">Jack 6.35mm</text>
<text x="181.2" y="42.4">J5</text>
<text x="44.8" y="48.3" transform="rotate(-90 44.8 48.3)">1K</text>
<text x="45.8" y="49.3" transform="rotate(-90 45.8 49.3)">100n</text>
<text x="47.3" y="53.9" transform="rotate(-90 47.3 53.9)">36K</text>
<text x="48.4" y="50.4" transform="rotate(-90 48.4 50.4)">USB2514B_Bi</text>
<text x="49.2" y="53.9" transform="rotate(-90 49.2 53.9)">36K</text>
<text x="51.1" y="53.9" transform="rotate(-90 51.1 53.9)">36K</text>
<text x="53.8" y="53" transform="rotate(-90 53.8 53)">100n</text>
<text x="59.5" y="50.1">36K</text>
<text x="62.8" y="51" transform="rotate(-90 62.8 51)">18p</text>
<text x="64.7" y="53.3" transform="rotate(-90 64.7 53.3)">Crystal_Small</text>
<text x="67.5" y="48.9" transform="rotate(-90 67.5 48.9)">Y1</text>
<text x="68.4" y="51.8">10u</text>
<text x="71.8" y="49.3" transform="rotate(-90 71.8 49.3)">36K</text>
<text x="76" y="51.3">25.0000 mm</text>
<text x="93.1" y="52">100n</text>
<text x="93.3" y="52.7">100n</text>
<text x="94.1" y="54">1K</text>
<text x="100" y="53.3" transform="rotate(-90 100 53.3)">U4</text>
<text x="112" y="50.2">15p</text>
<text x="112.1" y="49.3" transform="rotate(-90 112.1 49.3)">100n</text>
<text x="115.7" y="50">NCP1117-3.3_SOT223</text>
<text x="115.9" y="53.5">1K</text>
<text x="120.6" y="48.2">10u</text>
<text x="121" y="49.9">10u</text>
<text x="127" y="49.7" transform="rotate(-90 127 49.7)">Micro Button</text>
<text x="137.8" y="48.1" transform="rotate(-90 137.8 48.1)">220R</text>
<text x="156.1" y="48.3" transform="rotate(-90 156.1 48.3)">12K</text>
<text x="157.5" y="51" transform="rotate(-90 157.5 51)">20K</text>
<text x="158.8" y="49.3">1n</text>
<text x="164.1" y="50.6">L5</text>
<text x="198.3" y="52.5" transform="rotate(-90 198.3 52.5)">33 mm</text>
<text x="16.7" y="59.3" transform="rotate(-90 16.7 59.3)">USB_OTG</text>
<text x="21" y="54.9">TPD4EUSB30</text>
<text x="21.2" y="57.3" transform="rotate(-90 21.2 57.3)">J9</text>
<text x="41.7" y="58.1">2K2</text>
<text x="49.9" y="59.1">100n</text>
<text x="52.1" y="55.1">FSUSB42MUX</text>
<text x="76" y="55.1" transform="rotate(-90 76 55.1)">AP2553W6</text>
<text x="89.5" y="54.9" transform="rotate(-90 89.5 54.9)">SW3</text>
<text x="93.7" y="58">DNF</text>
<text x="94.5" y="58.5" transform="rotate(-90 94.5 58.5)">Micro Button</text>
<text x="98" y="56.5">W25Q128JVS</text>
<text x="105.4" y="54.3" transform="rotate(-90 105.4 54.3)">100n</text>
<text x="110.5" y="54.4" transform="rotate(-90 110.5 54.4)">100n</text>
<text x="110.7" y="57">2K2</text>
<text x="112.3" y="56.2">TP4</text>
<text x="114.7" y="56.5">LED Y</text>
<text x="116.6" y="58.6" transform="rotate(-90 116.6 58.6)">ABM8-272-T3</text>
<text x="116.6" y="54.9" transform="rotate(-90 116.6 54.9)">Y2</text>
<text x="136.8" y="54" transform="rotate(-90 136.8 54)">J28</text>
<text x="141.5" y="55.9">49 mm</text>
<text x="142.2" y="56" transform="rotate(-90 142.2 56)">JST PH 3</text>
<text x="145.7" y="54.2" transform="rotate(-90 145.7 54.2)">J14</text>
<text x="151.2" y="56.2" transform="rotate(-90 151.2 56.2)">JST PH 4</text>
<text x="153.2" y="54.8">100u</text>
<text x="153.6" y="57.9">C33</text>
<text x="158.8" y="54.4" transform="rotate(-90 158.8 54.4)">10u</text>
<text x="160.8" y="54.4" transform="rotate(-90 160.8 54.4)">10u</text>
<text x="161.1" y="59.4">TestPoint</text>
<text x="161.2" y="55.8" transform="rotate(-90 161.2 55.8)">SRN6045TA-3R3Y</text>
<text x="162.8" y="54.4" transform="rotate(-90 162.8 54.4)">10u 1.2n</text>
<text x="163.6" y="55.4">TP3</text>
<text x="168.6" y="55">3.5 mm</text>
<text x="171.3" y="54.9" transform="rotate(-90 171.3 54.9)">10u</text>
<text x="26.9" y="61.8">1n</text>
<text x="44.4" y="61.3" transform="rotate(-90 44.4 61.3)">2K2</text>
<text x="71.3" y="63.8">CM4</text>
<text x="100.8" y="63.5">SW6</text>
<text x="109.9" y="60.2">TestPoint</text>
<text x="118.2" y="64">H5</text>
<text x="167.2" y="64">H4</text>
<text x="174.8" y="63.5">SW7</text>
<text x="28.8" y="67.5">SW5</text>
<text x="114.2" y="67.3">MountingHole</text>
<text x="163.2" y="67.3">MountingHole</text>
<text x="24.4" y="74.9">Tactile Button</text>
<text x="93.5" y="76.7" transform="rotate(-90 93.5 76.7)">SJP</text>
<text x="99.2" y="76.7" transform="rotate(-90 99.2 76.7)">SJP</text>
<text x="99.4" y="74.9">Tactile Button</text>
<text x="174.4" y="74.9">Tactile Button</text>
<text x="200.5" y="77.9" transform="rotate(-90 200.5 77.9)">111 mm</text>
<text x="26.8" y="83.4">J20</text>
<text x="95" y="80.4">74AHCT1G32SE-7</text>
<text x="102.5" y="84">Debug</text>
<text x="103.5" y="81.8">J16</text>
<text x="103.6" y="83.3" transform="rotate(-90 103.6 83.3)">LED R</text>
<text x="105.6" y="83.3" transform="rotate(-90 105.6 83.3)">LED Y</text>
<text x="107.6" y="81.5" transform="rotate(-90 107.6 81.5)">2K2</text>
<text x="109.6" y="81.1" transform="rotate(-90 109.6 81.1)">1K</text>
<text x="110.8" y="80" transform="rotate(-90 110.8 80)">29 mm</text>
<text x="180.7" y="83.4">J18</text>
<text x="20.6" y="88.5">Jack 6.35mm</text>
<text x="176.1" y="89.5">Jack 6.35mm</text>
<text x="102.3" y="94.5" transform="rotate(-90 102.3 94.5)">65 mm</text>
<text x="106.8" y="94.5" transform="rotate(-90 106.8 94.5)">58 mm</text>
<text x="119.5" y="93.7" transform="rotate(-90 119.5 93.7)">J27</text>
<text x="198.3" y="95" transform="rotate(-90 198.3 95)">52 mm</text>
<text x="100.2" y="101.8">MountingHole</text>
<text x="103.8" y="98.5">H16</text>
<text x="26.8" y="103.6">J19</text>
<text x="48.3" y="105">SJP</text>
<text x="180.7" y="103.6">J22</text>
<text x="22.6" y="109">Jack 6.35mm</text>
<text x="176.6" y="109">Jack 6.35mm</text>
<text x="24.8" y="114.5">SW8</text>
<text x="99.8" y="114.5">SW9</text>
<text x="171.3" y="116.2" transform="rotate(-90 171.3 116.2)">SJP</text>
<text x="173.9" y="115">SW10</text>
<text x="114.2" y="125.4">MountingHole</text>
<text x="118.2" y="122">H6</text>
<text x="146" y="125.7">SJP</text>
<text x="146.3" y="121.6">SJP</text>
<text x="163.2" y="125.3">MountingHole</text>
<text x="167.2" y="122">H7</text>
<text x="16.8" y="126.1">Fiducial</text>
<text x="24.4" y="126.9">Tactile Button</text>
<text x="37.2" y="131.8">MountingHole</text>
<text x="40.8" y="128.5">H14</text>
<text x="99.4" y="126.9">Tactile Button</text>
<text x="163.2" y="131.8">MountingHole</text>
<text x="166.8" y="128.5">H15</text>
<text x="174.4" y="126.9">Tactile Button</text>
<text x="186.8" y="126.1">Fiducial</text>
<text x="198.5" y="126.1" transform="rotate(-90 198.5 126.1)">12 mm</text>
<text x="63.5" y="141.3">75.0000 mm</text>
<text x="101.4" y="147.1">180.84 mm</text>
<text x="102.6" y="144.4">174 mm</text>
</g>
<text font-size="1.1" fill="#fff" x="123.3" y="54.7" transform="rotate(-90 123.3 54.7)">U5</text>
<text font-size=".9" fill="#fff" x="158.2" y="28.4">FDS4435BZ</text>
<text font-size=".8" fill="#fff" x="55.6" y="57.4">U8</text>
<g font-size=".7" fill="#fff">
<text x="39.8" y="25.5" transform="rotate(-90 39.8 25.5)">C41</text>
<text x="41.8" y="25.5" transform="rotate(-90 41.8 25.5)">C42</text>
<text x="151.4" y="24.1" transform="rotate(-90 151.4 24.1)">R1</text>
<text x="164.4" y="24.4" transform="rotate(-90 164.4 24.4)">C4</text>
<text x="57.9" y="33.4" transform="rotate(-90 57.9 33.4)">C51</text>
<text x="78" y="32.6" transform="rotate(-90 78 32.6)">C1</text>
<text x="154.7" y="30.1" transform="rotate(-90 154.7 30.1)">C8</text>
<text x="157.4" y="35.9">C9</text>
<text x="157.4" y="34">C6</text>
<text x="160.6" y="36">C10</text>
<text x="160.8" y="34">C3</text>
<text x="164.4" y="31">C2</text>
<text x="50.2" y="40.9" transform="rotate(-90 50.2 40.9)">C44</text>
<text x="54.6" y="36.9" transform="rotate(-90 54.6 36.9)">C40</text>
<text x="56.6" y="36.9" transform="rotate(-90 56.6 36.9)">C39</text>
<text x="81.8" y="41.4" transform="rotate(-90 81.8 41.4)">R3</text>
<text x="90.4" y="39.5">U2</text>
<text x="99.7" y="40.5" transform="rotate(-90 99.7 40.5)">C21</text>
<text x="101.4" y="38.7">C17</text>
<text x="101.6" y="40.7">C14</text>
<text x="108.1" y="39.7">C13</text>
<text x="156.1" y="41" transform="rotate(-90 156.1 41)">C35</text>
<text x="157.4" y="37.9">C5</text>
<text x="160.8" y="37.9">C7</text>
<text x="163.5" y="41.3" transform="rotate(-90 163.5 41.3)">C30</text>
<text x="42.9" y="47.9" transform="rotate(-90 42.9 47.9)">R2</text>
<text x="47.3" y="43.6" transform="rotate(-90 47.3 43.6)">C48</text>
<text x="57.6" y="44.2">C45</text>
<text x="61.2" y="45.2" transform="rotate(-90 61.2 45.2)">R24</text>
<text x="64.2" y="47" transform="rotate(-90 64.2 47)">C11</text>
<text x="92.8" y="44.5">R5</text>
<text x="92.8" y="42.6">R4</text>
<text x="98.8" y="44.7">R10</text>
<text x="99" y="46.6">R6</text>
<text x="100.1" y="42.8">C12</text>
<text x="115.1" y="44.5">C23</text>
<text x="137.4" y="44.2" transform="rotate(-90 137.4 44.2)">R7</text>
<text x="139.2" y="46.4">R20</text>
<text x="140" y="43.9" transform="rotate(-90 140 43.9)">U1</text>
<text x="143.1" y="45.1" transform="rotate(-90 143.1 45.1)">C52</text>
<text x="149.1" y="43.2">R19</text>
<text x="149.2" y="45.5">R18</text>
<text x="154.2" y="47.7" transform="rotate(-90 154.2 47.7)">R12</text>
<text x="156.1" y="44.4" transform="rotate(-90 156.1 44.4)">R15</text>
<text x="156.1" y="47.8" transform="rotate(-90 156.1 47.8)">C29</text>
<text x="159" y="47.4">C34</text>
<text x="163.5" y="44.7" transform="rotate(-90 163.5 44.7)">R13</text>
<text x="47.3" y="48.3" transform="rotate(-90 47.3 48.3)">C49</text>
<text x="48.7" y="53.3" transform="rotate(-90 48.7 53.3)">R26</text>
<text x="50.6" y="53.3" transform="rotate(-90 50.6 53.3)">R25</text>
<text x="52.5" y="53.3" transform="rotate(-90 52.5 53.3)">R28</text>
<text x="55.3" y="52" transform="rotate(-90 55.3 52)">C47</text>
<text x="60.1" y="48.2">R27</text>
<text x="64.2" y="50.4" transform="rotate(-90 64.2 50.4)">C25</text>
<text x="69" y="53.2">C38</text>
<text x="73.2" y="48.7" transform="rotate(-90 73.2 48.7)">R29</text>
<text x="94.3" y="50.1">C18</text>
<text x="94.5" y="52.1">R8</text>
<text x="103.6" y="53.3" transform="rotate(-90 103.6 53.3)">C19</text>
<text x="108.9" y="53.4" transform="rotate(-90 108.9 53.4)">C20</text>
<text x="112.6" y="51.6">C22</text>
<text x="113.4" y="48.3" transform="rotate(-90 113.4 48.3)">C16</text>
<text x="116.1" y="51.6">R11</text>
<text x="117.6" y="49.3" transform="rotate(-90 117.6 49.3)">C26</text>
<text x="121.2" y="49.7">C24</text>
<text x="124.6" y="49.7">C27</text>
<text x="156.9" y="53.8" transform="rotate(-90 156.9 53.8)">C28</text>
<text x="158.9" y="53.8" transform="rotate(-90 158.9 53.8)">C36</text>
<text x="158.9" y="50.4" transform="rotate(-90 158.9 50.4)">R14</text>
<text x="160.9" y="53.8" transform="rotate(-90 160.9 53.8)">C32</text>
<text x="160.9" y="50.4" transform="rotate(-90 160.9 50.4)">C31</text>
<text x="18.7" y="58.1" transform="rotate(-90 18.7 58.1)">PCB edge</text>
<text x="25.3" y="57.6" transform="rotate(-90 25.3 57.6)">U11</text>
<text x="27.1" y="59.9">C50</text>
<text x="42.3" y="59.5">R22</text>
<text x="94.3" y="54.1">C15</text>
<text x="94.5" y="56.1">R9</text>
<text x="111.3" y="55.1">R21</text>
<text x="116.3" y="57.9">D2</text>
<text x="169.4" y="54.3" transform="rotate(-90 169.4 54.3)">C37</text>
<text x="45.8" y="60.7" transform="rotate(-90 45.8 60.7)">R23</text>
<text x="50.9" y="60.5">C46</text>
<text x="100.8" y="78.3" transform="rotate(-90 100.8 78.3)">U7</text>
<text x="103.4" y="78.4" transform="rotate(-90 103.4 78.4)">R17</text>
<text x="105.3" y="78.2" transform="rotate(-90 105.3 78.2)">D7</text>
<text x="107.3" y="78.2" transform="rotate(-90 107.3 78.2)">D6</text>
<text x="109.3" y="78.3" transform="rotate(-90 109.3 78.3)">R16</text>
</g>
<g font-size=".5" fill="#fff">
<text x="19.4" y="28.2">FID1</text>
<text x="189.4" y="28.2">FID2</text>
<text x="80" y="41.5" transform="rotate(-90 80 41.5)">L4</text>
<text x="80.7" y="43.6">L1</text>
<text x="89.7" y="42.4">L3</text>
<text x="89.7" y="43.8">L2</text>
<text x="145.5" y="44.7">U12</text>
<text x="73.3" y="52.4" transform="rotate(-90 73.3 52.4)">U10</text>
<text x="19.4" y="123.2">FID3</text>
<text x="189.4" y="123.2">FID4</text>
</g>
</g></defs>
<g fill="none" stroke="#848484" stroke-width=".15">
<path d="M24.6 20v.8l.2 .2M25.1 20v.1M27.4 20v1M28 20v1M29.4 20v.8l.1 .2M47.5 16.7v.8l.2 .2h.2l.2-.2v-.8M49.1 16.8l-.4-.1-.2 .2 .1 .2 .4 .2v.3l-.1 .1h-.4M49.5 17.2h.3M49.5 16.7h.3l.2 .2-.2 .3 .2 .1 .1 .2-.2 .2h-.4zM50.3 17.8h.7M51.1 17.7l.4-1 .3 1M51.2 17.4h.5"/>
<path d="M167.5 14.3l.5 .1 .1 .2-.2 .2a.27 .27 0 0 1 .2 .3 .27 .27 0 0 1-.2 .2h-.4zM167.5 14.8h.4M168.5 14.7h.4l.1 .6M169 14.9l-.4 .1-.1 .1 .1 .2h.4M169.4 14.7v.6M169.7 14.7h-.2l-.1 .2M170.1 14.7v.6M170.3 14.7l-.2 .2M170.6 15l.5-.1v-.2h-.3l-.2 .1 .1 .5h.4M171.5 14.3v.9l.2 .1M171.8 15.4h.8M173.1 14.3v.8a.32 .32 0 0 1-.4 .2"/>
<path d="M173.6 14.7h.4v.6M174 14.9l-.3 .1-.2 .1 .2 .2h.3M174.9 14.7h-.3l-.2 .2 .1 .4h.4M175.3 14.3v1M175.4 15l.3 .3M175.7 14.7l-.4 .4M175.9 15.4h.8M176.9 15.3v-1l.4 .8 .3-.8v1M178.1 14.7h.2l.2 .2v.3l-.2 .1h-.2l-.1-.1zM179 14.7v.6h.3l.1-.1M179.4 14.7v.6M179.7 19.9v-1l.4 .8 .3-.8v1"/>
<path d="M179.9 14.8l.1-.1h.3v.6M179.9 14.7v.6M180.6 14.7h.4M180.8 14.3v.9l.2 .1M180.9 19.3h.2l.2 .2v.3l-.2 .1h-.2l-.1-.1zM181.3 14.3v.1M181.3 14.7v.6M181.6 17.3a.59 .59 0 0 1 1 .2 .57 .57 0 0 1-1-.1zM181.8 19.3v.6h.3h.1M181.8 14.8l.2-.1h.2l.1 .6M181.8 14.7v.6M181.9 18.1l.7 .5"/>
<path d="M182.2 19.3v.6M182.6 16.2v.7l-.7-.7-.3 .2 .1 .4M182.6 19v.5M182.6 19.2h-1l.3 .3M182.6 18.1l-.7 .5M182.7 19.3v.6M182.7 19.4l.1-.1h.3v.6M183.2 14.7h-.3l-.2 .2 .1 .4h.4M183.2 14.7v.8l-.2 .2-.3-.1M183.4 19.3h.4M183.6 18.9v.9l.2 .1M183.6 14.9l.5-.1 .1-.1v-.3l-.2-.1h-.4v1"/>
<path d="M184.1 18.9v.1M184.1 19.3v.6M184.6 19.4l.2-.1h.2l.1 .6M184.6 19.3v.6M184.6 14.3v.1M184.6 14.7v.6M185.1 14.8l.2-.1h.2v.6M185.1 14.7v.6M186 19.3h-.3l-.2 .2 .1 .4h.4M186 19.3v.8l-.2 .2-.3-.1M186.4 18.9v1M186.4 19.4h.6"/>
<path d="M187 18.9v1M187.5 19.3h.3l.2 .2v.3l-.2 .1h-.3l-.1-.1zM188.4 18.9v.9l.1 .1M188.9 19.6l.4-.1v-.2h-.3l-.1 .1v.5h.4M17.3 30.5h.3M17.8 30.1h-.5v1M18.1 30.1v.1M18.1 30.4v.7M19 30.1v1M19 30.4h-.2l-.2 .2 .1 .4h.3M19.5 30.4l.1 .6 .2 .1 .2-.1M20 30.4v.7"/>
<path d="M20.7 21v-1l.3 .7 .4-.7v1M20.9 30.4h-.3l-.2 .2 .1 .4h.4M21.3 30.1v.1M21.3 30.4v.7M21.8 30.4h.3l.1 .7M21.9 20.4l.1-.1 .3 .1v.4l-.1 .1-.2 .1-.1-.1zM22.2 30.6l-.3 .1-.2 .1 .2 .3 .3-.1M22.7 30.1v.8l.1 .2M22.8 20.3v.6l.2 .1 .2-.1M23.2 20.3v.7M23.7 20.4l.1-.1h.2l.1 .7M23.7 20.3v.7"/>
<path d="M24.2 22.5v1M24.2 22.9h.6M24.4 20.3h.4M24.8 22.5v1M25.1 20.3v.7M25.2 23.5h.6M25.2 22.7l.3-.2v1M25.6 20.4l.2-.1h.2v.7M25.6 20.3v.7M27 20.3h-.3l-.2 .2 .1 .4h.4M27 20.3v.8l-.2 .2-.3-.1M27.4 20.4h.6"/>
<path d="M28.5 20.4l.1-.1 .3 .1 .1 .4-.1 .1-.3 .1-.1-.1zM29.9 20.6l.4-.1v-.2h-.3l-.1 .1v.5h.4M34.7 26.4h.6M34.7 25.7l.3-.3v1M35.8 28.6a.47 .47 0 0 0-.7 .3 .47 .47 0 0 0 .5 .6l.2-.1M35.8 25.4h.1a.53 .53 0 0 1 .4 .5 .53 .53 0 0 1-.4 .5 .67 .67 0 0 1-.1-1zM36.4 28.4l-.2 .8h.6M36.6 28.8v.7M36.8 25.4h.1a.53 .53 0 0 1 .3 .5 .53 .53 0 0 1-.3 .5 .67 .67 0 0 1-.1-1zM37.1 28.5h.6l-.4 .4 .3 .1v.4l-.1 .1-.4-.1M37.6 25.7l.1 .6 .2 .1 .2-.1M38.1 25.7v.7"/>
<path d="M40.8 24.7a.54 .54 0 0 1 .9 .3 .57 .57 0 0 1-1-.1zM41 23.8h.7M41.6 23.8l.1 .1v.2l-.7 .1M41.7 25.9h-1l.3 .2M41.7 25.6v.5M42.7 24.8a.59 .59 0 0 1 1 .2 .57 .57 0 0 1-1-.1zM43 23.8h.7M43.6 23.8l.1 .1-.1 .2-.6 .1M43.7 25.9h-1l.2 .2M43.7 25.6v.5M48.8 27.5v.7a.32 .32 0 0 1-.4 .3M49.2 28.5h.6"/>
<path d="M49.2 27.8l.3-.3v1M50.2 27.6l.2-.1a.53 .53 0 0 1 .3 .5 .53 .53 0 0 1-.3 .5l-.2-.1v-.3zM51.4 39.1h.7M52 39.1l.1 .1v.3h-.7M52.2 36a.54 .54 0 0 1 .9 .3 .57 .57 0 0 1-1-.1zM52.5 35.1h.6M53 35.1l.1 .1v.3h-.6M53.1 36.9v.6M53.1 37.2h-1l.3 .3M54.2 36a.54 .54 0 0 1 .9 .3 .57 .57 0 0 1-1-.1zM54.4 35.1h.7M55 35.1l.1 .1-.1 .3h-.6"/>
<path d="M55.1 37.2h-1l.3 .3M55.1 36.9v.6M55.8 32.5h.7M56.5 32.1h-.6l-.1 .2 .1 .2M56.5 32.9v.6M56.5 33.2h-1l.3 .3M59 26.6l.4-.1 .2 .2-.6 .8h.6M60.2 26.4l-.2 .7h.6M60.5 26.8v.7M61 27l.5-.1 .1-.1-.1-.2-.1-.1h-.4v1M62.7 26.4l-.8 1.3M63 27l.5-.1 .1-.1v-.2l-.2-.1h-.4v1"/>
<path d="M63.3 27l.3 .5M64.8 26.6l.3-.1 .2 .2-.6 .8h.6M66 26.4l-.3 .7h.6M66.2 26.8v.7M66.7 26.8v.7M66.7 26.9l.3-.1 .1 .1M67.1 26.9l.2-.1h.2l.1 .7M67.1 26.9v.6M68 26.9l.3-.1 .2 .1M68 26.8v.7M68.5 26.9l.1-.1h.3v.7M68.5 26.9v.6"/>
<path d="M70.6 37.3h-.4l-.1 .1v.2l.4 .2 .1 .3-.2 .2-.4-.1M70.9 37.3l.3 1 .2-.8 .1 .8 .3-1M72.1 38.3h.6M72.1 37.5l.3-.2v1M75.6 32.5a.59 .59 0 0 1 1 .2 .57 .57 0 0 1-1-.1zM75.7 31.5a.54 .54 0 0 1 .9 .2 .57 .57 0 0 1-1 0zM75.9 31h.7M76.6 30.6h-.6l-.1 .2 .1 .2M76.6 33.3v.6M76.6 33.6h-1l.3 .3M78.5 39.1v.5l-.7-.5v.5M83.2 39.8l-.1-.4-.1-.1h-.3v.1v.4h1"/>
<path d="M83.7 39.3l-.5 .3M85.1 39.4a.59 .59 0 0 1 .9 .1 .57 .57 0 0 1-1 0zM85.9 22v.7a.32 .32 0 0 1-.3 .3M86 38.6l-1-.4v.7M86.4 22.3h.4l.1 .7M86.9 22.5l-.4 .1-.1 .1 .1 .3 .4-.1M87.8 22.3h-.3l-.2 .2 .1 .4h.4M88.2 22v1M88.3 22.6l.3 .4M88.6 22.3l-.4 .4M89.7 25.5v.7a.32 .32 0 0 1-.4 .3M89.7 22h.6l-.4 .3 .3 .1v.5l-.1 .1-.4-.1"/>
<path d="M90.1 26.5h.6M90.1 25.7l.3-.2v1M90.7 22.9v.1M91.7 22h-.5l-.1 .4 .2-.1 .3 .1 .1 .1v.4l-.2 .1-.4-.1M92.1 22.4l.3-.1 .2 .1M92.1 22.3v.7M92.6 22.4l.1-.1h.2l.1 .7M92.6 22.4v.6M93.5 22.3v.7M93.5 22.4l.3-.1 .1 .1M93.9 22.4v.6M93.9 22.4l.1-.1h.3v.7"/>
<path d="M97.5 39.2a.59 .59 0 0 1 1 .2 .57 .57 0 0 1-1-.1zM97.8 38.6h.7M98.5 38.2l-.7 .1v.2l.1 .1M100.5 37.3h.6M100.5 36.6l.3-.3v1M101.6 36.4l.1-.1a.53 .53 0 0 1 .3 .5 .53 .53 0 0 1-.3 .5 .67 .67 0 0 1-.1-.9zM101.6 21.5v-1l.3 .7 .4-.7v1M102.5 36.4l.1-.1a.53 .53 0 0 1 .4 .5 .53 .53 0 0 1-.4 .5 .67 .67 0 0 1-.1-.9zM102.7 20.5v.1M102.7 20.9v.6M103.4 36.6v.7M103.4 36.7l.1-.1 .3 .1v.6"/>
<path d="M103.6 20.5v1M103.6 20.9h-.2l-.2 .2 .1 .4h.3M104.1 20.5v.1M104.1 20.9v.6M104.3 22v1M104.3 22.5h.6M104.9 22v1M105.3 22.1l.4-.1 .2 .3-.6 .7h.6M105.4 20.5l.4 .1 .1 .2-.2 .2a.27 .27 0 0 1 .2 .2 .27 .27 0 0 1-.2 .3h-.3zM105.4 21h.3M106.1 38h.6M106.1 37.3l.3-.3v1"/>
<path d="M106.4 20.5v.1M106.4 20.9v.6M106.7 20.9h.4M106.8 20.5v.9l.3 .1M107.1 37.1l.2-.1a.53 .53 0 0 1 .3 .5 .53 .53 0 0 1-.3 .5l-.2-.1v-.3zM107.4 21.2l.4-.1v-.2h-.3l-.1 .1v.5h.4M108.1 37.1l.1-.1a.53 .53 0 0 1 .4 .5 .53 .53 0 0 1-.4 .5l-.1-.1-.1-.3zM108.6 20.9h-.2l-.2 .1 .1 .1 .3 .1v.3h-.4M109 37.3v.7M109 37.4l.1-.1h.3v.7M116 21.5v.7a.32 .32 0 0 1-.4 .3M116.4 21.8h.4l.1 .7"/>
<path d="M116.9 22l-.4 .1-.1 .1 .1 .3 .4-.1M117.8 21.8h-.3l-.2 .2 .1 .4h.4M118.2 21.5v1M118.3 22.1l.3 .4M118.6 21.8l-.4 .4M119.7 21.5h.6l-.3 .3 .2 .1v.5l-.1 .1-.4-.1M119.7 25.5v.7a.32 .32 0 0 1-.4 .3M120 25.5h.7l-.4 .3 .3 .1v.5l-.1 .1-.5-.1M120.7 22.4v.1M121.7 21.5h-.5l-.1 .4 .2-.1 .3 .1 .1 .1v.4l-.2 .1-.4-.1M122.1 21.9l.3-.1 .2 .1M122.1 21.8v.7"/>
<path d="M122.6 21.9l.1-.1h.3v.7M122.6 21.9v.6M123.5 21.9l.3-.1 .1 .1M123.5 21.8v.7M123.9 21.9l.1-.1h.3v.7M123.9 21.9v.6M145.6 37.3h-.4l-.2 .1 .1 .3 .4 .2v.3l-.1 .1-.4-.1M145.9 37.3l.3 1 .2-.8 .1 .8 .3-1M147.1 37.4l.4-.1 .2 .2-.6 .8h.6M148.8 23.5h1M148.8 22.9l.6 .6M149.8 24.2h-1l.3 .3"/>
<path d="M149.8 23.9v.6M149.8 22.9l-.5 .5M149.9 34.4h.6M150.2 34.4v1M150.7 35.1l.5-.1v-.2h-.3l-.2 .1 .1 .5h.4M150.9 27.4h.6M151.2 27.4v1M151.8 28.1l.4-.1v-.2h-.3l-.1 .1v.5h.4M152 30.4h.5M152 34.8h-.3l-.1 .1v.2h.4v.3h-.4M152.2 30.4v1M152.3 34.8h.4"/>
<path d="M152.5 34.4v.9l.2 .1M152.9 30.9h.4l.1-.2v-.2l-.2-.1h-.3v1M153 23.4h.5M153 27.8h-.2l-.2 .1 .1 .2 .3 .1v.2h-.4M153 35l.5-.1 .1-.1v-.3l-.2-.1h-.4v1M153.3 23.4v1M153.3 27.8h.4M153.5 27.4v.9l.2 .1M153.7 39.7a.59 .59 0 0 1 .9 .2 .57 .57 0 0 1-1-.1zM153.8 31.4h.6M153.8 30.7l.3-.3v1M153.9 23.9h.4l.1-.2v-.2l-.1-.1h-.4v1"/>
<path d="M153.9 39.2h.7M154 34.9l.2-.1 .3 .1v.3l-.1 .2h-.2l-.2-.1zM154 28l.5-.1 .1-.1v-.3l-.2-.1h-.4v1M154.6 38.7l-.6 .1-.1 .2 .1 .2M154.8 23.5l.4-.1 .2 .3-.6 .7h.6M154.9 34.4v.1M154.9 34.8v.6M155.1 27.8h.2l.2 .2v.3l-.2 .1h-.2l-.1-.1zM155.4 34.9l.2-.1h.2v.6M155.4 34.8v.6M155.6 37.4v-.7l.4 .4 .1-.3h.4l.1 .1-.1 .5M155.6 29.5a.54 .54 0 0 1 1 .2 .57 .57 0 0 1-1-.1z"/>
<path d="M155.9 28.5h.7M155.9 27.4v.1M155.9 27.8v.6M156.2 34.8h.4M156.2 38.7v.7M156.3 34.4v.9l.3 .1M156.4 27.8v.6M156.4 27.9l.2-.1h.2v.6M156.5 28.5l.1 .1-.1 .3h-.6M156.6 30.3v.6M156.6 30.6h-1l.2 .3M156.6 38h-1l.3 .3"/>
<path d="M156.6 37.7v.6M156.6 35.7l.3-.3v1M156.6 36.4h.5M156.6 33.8l.3-.3v1M156.6 34.5h.6M156.6 32.5h.6M156.6 31.8l.3-.3v1M157.2 27.8h.4M157.3 27.4v.9l.3 .1M157.6 35.5l.2-.1a.53 .53 0 0 1 .3 .5 .53 .53 0 0 1-.3 .5l-.2-.1-.1-.2zM157.7 31.6l.1-.1a.53 .53 0 0 1 .3 .5 .53 .53 0 0 1-.3 .5l-.1-.1-.1-.3zM157.7 33.5h.1a.53 .53 0 0 1 .3 .5 .53 .53 0 0 1-.3 .5 .67 .67 0 0 1-.1-1z"/>
<path d="M157.9 28h.2M158.2 27.7h-.3v.7M158.4 27.7a.32 .32 0 0 1 .4 .3 .32 .32 0 0 1-.4 .4zM158.5 35.8l.1 .6h.2l.2-.1M158.5 33.8l.1 .6 .2 .1 .2-.1M158.6 31.8v.7h.2l.2-.1M159 35.8v.6M159 33.8v.7M159 31.8v.7M159.4 27.7l-.3 .1a.27 .27 0 0 0 .3 .3v.2h-.4M159.8 27.7l-.1 .4h.4M160 27.9v.5"/>
<path d="M160 39.8h.6M160 39.1l.3-.3v1M160 37.1l.3-.3v1M160 37.8h.6M160 35.9h.6M160 35.2l.3-.3v1M160.4 27.7l-.1 .4h.4M160.6 27.9v.5M160.8 27.7h.4l-.2 .3h.2v.3h-.4M161 36.9l.2-.1a.53 .53 0 0 1 .3 .5 .53 .53 0 0 1-.3 .5h-.2l-.1-.3zM161.1 38.9l.1-.1a.53 .53 0 0 1 .3 .5 .53 .53 0 0 1-.3 .5 .66 .66 0 0 1-.1-.9zM161.1 34.9h.1a.53 .53 0 0 1 .4 .5 .53 .53 0 0 1-.4 .5 .67 .67 0 0 1-.1-1z"/>
<path d="M161.8 27.7h-.3v.3h.3v.3h-.3M161.9 39.1l.1 .7h.2l.2-.1M161.9 37.2l.1 .6h.2h.2M162 35.2v.6l.3 .1 .1-.1M162.1 28h.2M162.1 27.7h.2l.2 .1-.2 .2 .2 .2-.1 .2h-.3zM162.4 39.1v.7M162.4 37.2v.6M162.4 35.2v.7M162.6 24.5l.4-.1 .1-.1v-.3h-.1h-.4v1M162.7 27.7h.4l-.4 .7h.4M163.6 28.8l.3-.3v1"/>
<path d="M163.6 29.5h.6M163.6 24.3h.3l.1 .2v.3l-.1 .2-.3-.1-.1-.1zM164.5 24v.8l.1 .2M164.7 28.6l.1-.1a.53 .53 0 0 1 .4 .5 .53 .53 0 0 1-.4 .5l-.1-.1-.1-.3zM164.7 39.5h.6M164.9 24.3l.2 .7M165.1 25l-.2 .3M165.3 39.1h-.6v.3l.1 .1M165.4 24.3l-.3 .7M165.4 27.6h.3M165.6 28.8v.7h.3l.1-.1M165.6 24.3h.4"/>
<path d="M165.6 22.9h.7M165.7 24.3l-.3-.1-.1-.1a.53 .53 0 0 1 .5-.4 .53 .53 0 0 1 .5 .4l-.1 .1-.3 .1M165.9 27.2h-.5v1M166 28.8v.7M166 24l-.2 .1v.9M166.2 22.9l.1 .1v.2l-.7 .1M166.2 27.5l.3-.3v1M166.2 28.2h.6M166.3 24.7v.5M166.3 25h-1l.3 .2M166.3 24.3l.1 .6 .2 .1 .2-.1M166.8 24.3v.7"/>
<path d="M167.6 24.3h-.3l-.1 .1v.2l.4 .1v.2h-.4M168 24.6l.5-.1-.1-.2h-.3l-.1 .1v.5h.4M169.6 24.2l.3-.2v1M169.6 25h.6M170.6 24.9v.1M171.2 24.4l-.2 .2v.2l.2 .2h.2l.2-.2v-.3l-.2-.1M171.2 24.4l-.2-.2 .2-.2h.3l.1 .1-.2 .3M171.2 24.4h.2M171.9 25l.3-1 .4 1M172 24.7h.5M176.2 22.3v.8a.32 .32 0 0 1-.4 .2M176.6 22.3h.7l-.5 1"/>
<path d="M178.3 26h.7a.32 .32 0 0 1 .3 .4M178.3 25.1v.3a.67 .67 0 0 0 1 0l-.1-.3-.3-.1-.2 .2v.3l.2 .1M181.6 27.2v.5M181.6 27.4h1M181.6 24h.1M181.6 32.2v.3l.2 .2 .2-.1 .2-.4h.3l.1 .1-.1 .4M181.6 20.1a.59 .59 0 0 1 1 .2 .57 .57 0 0 1-1-.1zM181.9 25.7l.2 .3M181.9 30.6l.2 .3M181.9 30.9h.7M181.9 28.7l.7 .2-.5 .2 .5 .2-.7 .2M181.9 26h.7"/>
<path d="M181.9 25.3h.7M181.9 24h.7M181.9 23.5h.7M182 31.3l-.1 .3 .2 .2 .4-.1v-.4M182.1 24.9l-.2 .2 .1 .2M182.1 24.9h.5M182.2 22.2v.3l.2 .2 .2-.2-.1-.3M182.5 26.4l.1 .3-.2 .2-.4-.1v-.4h.2l.1 .5M182.5 29.9l.1 .3-.2 .1h-.4v-.4l.2-.1 .1 .5M182.6 22.2l-.6 .1v.3M182.6 23.1l-.6 .1-.1 .2 .1 .1M182.6 24.5h-.6l-.1 .3 .2 .1"/>
<path d="M182.6 21.6l-.2 .1h-.8M182.7 20.7v.7M182.7 27.8v.8M184.2 22.9h.6M184.2 22.4v1M184.8 22.4v1M185.2 22.4h.6l-.3 .4 .3 .1v.5h-.2h-.4M187.3 30.5h.3M187.8 30.1h-.5v1M188.1 30.1h.1M188.1 30.4v.7M189.1 30.4h-.3l-.2 .2 .1 .4h.4"/>
<path d="M189.1 30.1v1M189.5 30.4l.1 .6 .2 .1 .2-.1M190 30.4v.7M190.9 30.4h-.3l-.2 .2 .1 .4h.4M191.3 30.1h.1M191.3 30.4v.7M191.8 30.4h.3l.1 .7M192.2 30.6l-.3 .1-.2 .1 .2 .3 .3-.1M192.7 30.1v.8l.1 .2M15.7 59h.8l.2 .1-.1 .3-.1 .1h-.8M15.7 54.3v.6M15.7 54.6h1"/>
<path d="M15.7 57.1l.3-.1 .2 .2a.27 .27 0 0 1 .2-.3 .27 .27 0 0 1 .3 .2v.4h-1zM15.7 58v.3l.1 .2h.3l.2-.5h.2l.2 .1-.1 .4M15.7 53.4a.47 .47 0 0 0 .5 .6 .47 .47 0 0 0 .4-.6h-.3v.2M15.8 55.2a.68 .68 0 0 1 .9 .2 .33 .33 0 0 1-.3 .4h-.4a.34 .34 0 0 1-.3-.2 .34 .34 0 0 1 .1-.4zM16.2 57.2v.3M16.8 56v.8M20.1 56.8h.8a.32 .32 0 0 1 .2 .4M20.4 53.9h.5M20.5 46.5v.7a.32 .32 0 0 1-.4 .3M20.6 55.8l.2 .2v.2l-.2 .2-.4-.1-.1-.3 .1-.1a.66 .66 0 0 1 .9 .2v.2M20.7 53.9v1M21 46.8h.3l.1 .7"/>
<path d="M21.3 54.4h.4l.1-.2v-.2l-.1-.1h-.4v1M21.4 47l-.4 .1-.1 .1 .1 .3 .4-.1M22.3 53.9a.51 .51 0 0 1 .5 .5 .51 .51 0 0 1-.5 .5zM22.3 46.8h-.3l-.2 .2 .1 .4h.4M22.7 46.5v1M22.8 47.1l.3 .4M23.1 46.8l-.4 .4M23.5 53.9l-.3 .7h.6M23.7 54.2v.7M24.2 54.4h.4M24.7 53.9h-.5v1h.5M24.7 46.5h-.3a.67 .67 0 0 0 0 1l.4-.1v-.4l-.2-.2h-.2l-.2 .2"/>
<path d="M25.1 53.9v.8l.2 .2h.2l.2-.2v-.8M25.2 47.4v.1M25.6 46.5h.6l-.3 .3 .3 .1v.5l-.2 .1-.4-.1M26.7 54l-.4-.1-.2 .2 .1 .2 .5 .2v.3l-.2 .1h-.4M27.1 53.9h.4l.2 .2-.1 .2-.1 .1 .2 .1v.2l-.2 .2h-.4zM27.1 54.4h.4M27.1 46.5h-.4l-.1 .4 .2-.1 .3 .1 .1 .1-.1 .4-.1 .1-.4-.1M27.6 46.9l.3-.1 .1 .1M27.6 46.8v.7M27.7 41.3v.8a.32 .32 0 0 1-.4 .2M28 53.9h.7l-.4 .4 .3 .1v.4l-.1 .1-.5-.1M28 46.9l.2-.1h.2l.1 .7"/>
<path d="M28 46.9v.6M28.3 41.8l-.2 .2v.1l.2 .2h.2l.2-.2v-.1l-.2-.2M28.3 41.8l-.2-.2 .2-.3h.2l.2 .2-.2 .3M28.3 41.8h.2M29 46.9l.2-.1 .2 .1M29 46.8v.7M29.1 54l.2-.1a.53 .53 0 0 1 .3 .5 .53 .53 0 0 1-.3 .5l-.2-.1-.1-.3zM29.4 46.9l.1-.1h.3v.7M29.4 46.9v.6M41.6 57.1l.4-.1 .2 .3-.6 .7h.6M42.6 57v1M42.7 57.5l.5 .5"/>
<path d="M43.2 57l-.6 .6M43.3 59.8l.6 .6M43.6 57.1l.3-.1 .2 .3-.6 .7h.6M43.8 47.2h1M43.8 46.7l.6 .5M44.3 58.9v.6l-.7-.6-.3 .2 .1 .3M44.3 59.8l-.6 .5M44.8 48h-1l.3 .2M44.8 47.7v.5M44.8 46.7l-.6 .4M44.8 47.1a.59 .59 0 0 1 1 .2 .57 .57 0 0 1-1-.1zM44.8 48a.59 .59 0 0 1 1 .2 .57 .57 0 0 1-1-.1z"/>
<path d="M45.1 46.5h.7M45.8 48.9v.5M45.8 49.1h-1l.3 .3M45.8 46.1h-.6l-.1 .3 .1 .1M46.3 52h1M46.3 54v-.6l.4 .3 .1-.3h.4l.1 .1-.1 .5M46.3 52.5v.3a.67 .67 0 0 0 1 0l-.1-.4h-.3l-.2 .2v.3l.2 .1M46.3 51.4l.6 .6M47.3 51.4l-.6 .4M47.3 41.2h.1M47.3 46.3v.5h.5l-.1-.1 .1-.3 .1-.1h.3l.1 .2-.1 .3M47.3 50.2h.9l.1 .2v.3h-.1h-.9"/>
<path d="M47.4 41.7l.2-.1 .2 .2a.27 .27 0 0 1 .3-.2 .27 .27 0 0 1 .2 .2v.4h-1zM47.4 43.5l.2-.1 .2 .2a.27 .27 0 0 1 .3-.2 .27 .27 0 0 1 .2 .2v.3h-1zM47.4 49.2l-.1 .4 .2 .1h.3l.2-.5h.2l.1 .2v.3M47.4 48.3l.2-.1 .2 .2a.27 .27 0 0 1 .3-.2 .27 .27 0 0 1 .2 .2v.3h-1zM47.7 44.5h.6M47.7 41.2h.6M47.8 41.8v.4M47.8 43.6v.3M47.8 48.4v.3M48 44.3v.6l-.7-.2M48.2 52h1M48.2 52.5v.3a.67 .67 0 0 0 1 0l-.1-.4h-.3l-.2 .2v.3l.2 .1"/>
<path d="M48.2 54v-.6l.4 .3 .1-.3h.4l.1 .1-.1 .5M48.2 51.4l.6 .6M48.2 42.3a.59 .59 0 0 1 .9 .2 .57 .57 0 0 1-1-.1zM48.2 43.3a.59 .59 0 0 1 .9 .2 .57 .57 0 0 1-1-.1zM48.3 45.6h-1l.3 .3M48.3 45.3v.6M48.3 47.2v.6l-.7-.6-.3 .2 .1 .4M48.4 42.4v.8M48.5 41.7h.6M49.1 44.1v.5M49.1 44.4h-1l.3 .2M49.1 41.3l-.6 .1v.2l.1 .1"/>
<path d="M49.2 51.4l-.6 .4M49.8 58.4l.3-.3v1M49.8 59.1h.6M50.1 52.5v.3a.67 .67 0 0 0 1 0l-.1-.3-.3-.1-.2 .2v.2l.2 .2M50.1 54v-.6l.4 .3 .1-.3h.4l.1 .2-.1 .4M50.1 52h1M50.1 51.4l.6 .6M50.9 58.2l.1-.1a.53 .53 0 0 1 .4 .5 .53 .53 0 0 1-.4 .5l-.1-.1-.1-.3zM51.1 51.4l-.6 .4M51.2 40.1a.59 .59 0 0 1 .9 .2 .57 .57 0 0 1-1-.1zM51.4 54.5h.4M51.6 46.2h.9l.1 .1v.3l-.1 .1h-.9"/>
<path d="M51.8 58.2l.2-.1a.53 .53 0 0 1 .3 .5 .53 .53 0 0 1-.3 .5l-.2-.1-.1-.3zM51.9 54h-.5v1M52.1 45.1l.2 .2-.1 .3-.1 .1-.4-.1-.1-.3 .1-.1a.66 .66 0 0 1 .9 .2v.2M52.1 40.9v.6M52.1 41.2h-1l.3 .3M52.7 58.4v.7M52.7 58.5l.2-.1 .2 .1 .1 .6M52.8 54.1l-.4-.1-.2 .2 .1 .2 .5 .2v.3l-.2 .1h-.4M52.9 50.8a.59 .59 0 0 1 .9 .2 .57 .57 0 0 1-1-.1zM52.9 51.7a.59 .59 0 0 1 .9 .2 .57 .57 0 0 1-1-.1zM53.1 50.2h.7M53.2 54v.8l.2 .2h.2l.2-.2v-.8"/>
<path d="M53.8 49.8h-.6l-.1 .3 .1 .1M53.8 52.8h-1l.3 .3M53.8 52.6v.5M54.8 54.1l-.4-.1-.2 .2 .1 .2 .5 .2v.3l-.2 .1h-.4M55.2 54h.4l.2 .2-.1 .2-.1 .1 .2 .1v.2l-.2 .2h-.4zM55.2 54.5h.4M56.4 54l-.2 .7h.6M56.7 54.3v.7M57 46.1h.6M57 45.4l.3-.3v1M57.1 54.1l.4-.1 .2 .3-.6 .7h.6M58.1 45.2l.1-.1a.53 .53 0 0 1 .4 .5 .53 .53 0 0 1-.4 .5 .66 .66 0 0 1-.1-.9z"/>
<path d="M58.1 55v-1l.4 .7 .3-.7v1M59 45.5v.6h.3l.1-.1M59.3 54v.8l.2 .2h.2l.2-.2v-.8M59.4 49.1h.6l-.3 .4 .3 .1v.4l-.2 .1-.4-.1M59.4 45.5v.6M60.2 54l.7 1M60.9 49.1h-.3a.67 .67 0 0 0 0 1l.3-.1 .1-.3-.2-.2h-.3l-.1 .2M60.9 54l-.7 1M61.4 49.1v1M61.5 49.5l.5 .6M62 49.1l-.6 .6M62.1 49h1"/>
<path d="M62.1 43.9h1M62.1 43.4l.5 .5M62.1 49v-.3l.2-.2 .4 .1v.4M62.2 49.6l.2-.1h.2l.1 .1v.2l-.2 .2h-.2l-.1-.2M62.2 49.6l-.2-.1-.3 .1v.2l.2 .2 .3-.2M62.2 49.6v.2M62.7 50.4v.6M62.7 50.7h-1l.3 .3M63.1 44.4v.6l-.7-.6-.3 .1 .1 .4M63.1 45.3v.6M63.1 45.6h-1l.3 .3M63.1 43.4l-.6 .4"/>
<path d="M63.7 46.5v.4l.2 .2 .2-.1 .2-.5h.3l.1 .2-.1 .4M63.8 52.4a.47 .47 0 0 0 .3 .7 .47 .47 0 0 0 .6-.5l-.1-.2M64 52h.7M64 51.7l.2 .3M64 49.5v.4M64 51l.7 .2M64 46.1h.7M64.1 50.3l-.1 .2 .2 .1h.1l.1-.3h.2v.3M64.2 45.6h.5M64.2 45.6l-.2 .2 .1 .3M64.3 44.3v.3l.2 .2 .2-.2-.1-.3M64.3 48.8v.3l.2 .2 .2-.2-.1-.3"/>
<path d="M64.7 48.2l-.1 .1h-.9M64.7 48.8h-.6v.4M64.7 49.5l-.1 .3h-.9M64.7 44.3l-.6 .1v.3M64.7 45.2l-.6 .1-.1 .2 .2 .1M64.7 51.2l-.7 .3M64.7 51.2l.3 .3M64.7 43.7l-.1 .1h-.9M64.7 43.2l-.1 .1h-.9M64.8 47.3v.7M65.4 45.6h1M65.5 45.6l-.1-.3 .2-.2 .4 .1v.4"/>
<path d="M65.5 46.2l.2-.2h.2l.2 .2v.2l-.2 .2h-.3l-.1-.2M65.5 46.2l-.2-.2-.2 .2v.2l.2 .2 .2-.2M65.5 46.2v.2M66.1 47.3h-1l.3 .3M66.1 47v.6M66.5 48.3l.5 .3M67 48.6h.5M67 48.6l-.5 .3M67.5 47.4v.6M67.5 47.7h-1l.3 .3M68.4 51.7h.6M68.4 51l.3-.3v1"/>
<path d="M69.5 50.8l.1-.1a.53 .53 0 0 1 .4 .5 .53 .53 0 0 1-.4 .5 .67 .67 0 0 1-.1-.9zM70.4 51.1v.6h.3l.1-.1M70.7 42.1h.6M70.7 41.4l.3-.3v1M70.8 48v.2a.67 .67 0 0 0 1 0l-.1-.3h-.3l-.2 .1v.3l.2 .1M70.8 49.4v-.6l.4 .3 .1-.2h.4l.1 .1-.1 .4M70.8 47.4h1M70.8 46.9l.6 .5M70.8 51.1v.6M71.7 41.2l.4-.1 .1 .3-.6 .7h.6M71.8 46.9l-.6 .4M72.8 41.1h.1a.53 .53 0 0 1 .3 .5 .53 .53 0 0 1-.3 .5 .66 .66 0 0 1-.1-1z"/>
<path d="M73.4 42.2h.8M74.3 42.1h.6M74.3 41.4l.3-.3v1M74.9 48.3l.1 .3a.67 .67 0 0 0 .9 0v-.4h-.4l-.2 .2 .1 .3 .1 .1M74.9 50.9v-.6l.4 .3 .1-.3h.5v.2v.4M74.9 51.3v.5h.5l-.1-.1 .1-.4 .1-.1 .4 .1v.1v.4M74.9 52.2v.5l.5 .1-.1-.2 .1-.3 .1-.1h.4v.2v.4M74.9 49.1l1 .2-.7 .2 .7 .2-1 .2M75.4 41.1h.1a.53 .53 0 0 1 .4 .5 .53 .53 0 0 1-.4 .5 .67 .67 0 0 1-.1-1zM75.5 54.7l-.1-.5-.1-.1h-.3l-.1 .2v.4h1M75.7 55.1v.5M75.9 55l-1 .3 1 .4"/>
<path d="M75.9 53.1v.7l-.7-.7-.3 .2 .1 .4M76.4 41.1h.1a.53 .53 0 0 1 .3 .5 .53 .53 0 0 1-.3 .5 .67 .67 0 0 1-.1-1zM77.2 42.1v-1l.4 .7 .3-.7v1M77.5 40h1M77.5 40.6h1M77.6 43.2a.54 .54 0 0 1 .9 .2 .57 .57 0 0 1-1-.1zM77.6 42.2a.54 .54 0 0 1 .9 .3 .57 .57 0 0 1-1-.1zM77.6 45.9a.54 .54 0 0 1 .9 .2 .57 .57 0 0 1-1-.1zM78 40v.6M78.4 41.1v1M78.4 41.6h.6M78.5 48h-1l.3 .2"/>
<path d="M78.5 46.7v.6l-.7-.6-.3 .2 .1 .4M78.5 44.1v.5M78.5 47.7v.5M78.5 44.3h-1l.3 .3M78.5 41.1h-1l.7 .3-.7 .3h1M78.6 44.8v.8M79 41.1v1M79.3 41.4h.6l-.6 .7h.6M79.8 44h.5M79.8 43.6h.5M79.8 42.8l.2-.2v1.4M80 43l-.2 .3"/>
<path d="M80.7 43.1l.4-.1 .2 .3-.6 .7h.6M80.7 42.6h.4l.2 .2-.6 .8h.6M81.8 43h.1a.53 .53 0 0 1 .4 .5 .53 .53 0 0 1-.4 .5 .67 .67 0 0 1-.1-1zM81.8 42.6h.1a.53 .53 0 0 1 .4 .5 .53 .53 0 0 1-.4 .5 .67 .67 0 0 1-.1-1zM82.4 43.6h.8M82.7 40.4a.59 .59 0 0 1 1 .2 .57 .57 0 0 1-1-.1zM83.1 44.1a.51 .51 0 0 1 .5-.6 .51 .51 0 0 1 .5 .6h-1.7M83.4 44h.6M83.4 43.6h.6M83.4 42.8l.3-.2v1.4M83.7 42.2v.6l-.8-.6-.2 .2v.3M83.7 41.2v.6l-.8-.6-.2 .2v.4"/>
<path d="M83.7 43l-.3 .3M84.1 42.5v.6M84.1 42.8h-1l.3 .3M84.5 43h.1a.53 .53 0 0 1 .3 .5 .53 .53 0 0 1-.3 .5 .67 .67 0 0 1-.1-1zM84.5 42.6h.1a.53 .53 0 0 1 .3 .5 .53 .53 0 0 1-.3 .5 .67 .67 0 0 1-.1-1zM85.1 43.2l-.1 .4 .1 .1h.3l.2-.4 .2-.1 .2 .2v.4M85.1 40.3a.54 .54 0 0 1 .9 .2 .57 .57 0 0 1-1-.1zM85.4 41.2h.6M85.4 43h.1a.54 .54 0 0 1 .4 .5 .54 .54 0 0 1-.4 .5 .67 .67 0 0 1-.1-1zM85.4 42.6h.1a.53 .53 0 0 1 .4 .5 .53 .53 0 0 1-.4 .5 .67 .67 0 0 1-.1-1zM85.7 41.1v.6l-.7-.3M86 42.1h-1l.7 .4-.7 .3h1"/>
<path d="M86.3 44v-1.4l.3 .7 .4-.7v1.4M86.3 43l.3 .7 .4-.7M87.4 43.4h.6M87.4 42.6v1.4M87.4 43h.6M87.5 41.9h.5M87.8 41.9v1M88 42.6v1.4M88.4 41.9v1h.4M88.4 43.3h.5l-.5 .7h.5M88.4 42.9h.5l-.5 .7h.5M88.5 52.9v-.6l.3 .3 .1-.2h.5l.1 .1-.1 .4"/>
<path d="M88.5 53.2l1 .3-.7 .1 .7 .2-1 .3M88.5 54.4v.4l.1 .1h.2l.2-.4 .3-.1 .2 .2-.1 .4M89.2 42.5l.5-.1 .1-.1-.1-.3-.1-.1h-.4v1M90.1 42l.4-.1 .2 .3-.6 .7h.6M91 41.9h.7l-.4 1M91.9 40.2h.6l-.3 .4 .3 .1v.4l-.2 .1-.4-.1M91.9 46.4h.6M91.9 45.7l.3-.3v1M92.5 41.9l-.3 .1a.67 .67 0 0 0 0 .9l.4-.1v-.3l-.2-.2h-.2l-.2 .2M92.9 40.2h.6l-.4 .4 .3 .1v.4l-.1 .1-.4-.1M93 51.3l.3-.3v1M93 52h.5"/>
<path d="M93 42.2l.3-.3v1M93 42.9h.6M93 45.4h.1a.53 .53 0 0 1 .4 .5 .53 .53 0 0 1-.4 .5 .66 .66 0 0 1-.1-1zM93.2 52.6h.6M93.2 51.9l.3-.3v1M93.5 57.1h.1M93.5 53l.3-.1 .1 .2 .1-.2h.3l.2 .2v.4h-1zM93.7 57a.51 .51 0 0 1 .6 .5 .51 .51 0 0 1-.6 .5zM93.8 55.5l.2 .2M93.8 57.1h.7M93.8 50.7v.4M93.8 51.3v.4"/>
<path d="M93.8 55.7h.7M93.8 52h.7M93.8 49.5h.7M93.8 56.2v.3l.2 .1h.4v-.4M93.8 50l.5-.1 .1 .1 .1 .3-.2 .2h-.3l-.2-.2zM93.9 54.7h.5l.1 .1-.1 .3-.1 .1-.4-.1-.1-.1zM93.9 40.7h.5l.1-.2-.1-.2-.1-.1h-.4v1M93.9 45.9h.5l.1-.2-.1-.2-.1-.1h-.4v1M93.9 53.1v.4M94.1 40.7l.4 .5M94.1 45.9l.4 .5M94.2 54h.5"/>
<path d="M94.2 53.2l.2-.2v1M94.2 51a.57 .57 0 0 0 .1 1 .63 .63 0 0 0 0-1M94.2 51.7l.2-.1a.53 .53 0 0 1 .3 .5 .53 .53 0 0 1-.3 .5l-.2-.1-.1-.3zM94.4 52l.1 .2-.1 .2-.6 .1M94.5 57.6h-1l.7 .3-.7 .3h1M94.5 50.7l-.2 .3h-.8M94.5 51.3l-.2 .3h-.8M94.5 49.1h-.7v.3l.1 .1M95 51.1l.1-.1a.53 .53 0 0 1 .4 .5 .53 .53 0 0 1-.4 .5l-.1-.1-.1-.3zM95.2 53v1M95.2 51.7l.1-.1a.53 .53 0 0 1 .4 .5 .53 .53 0 0 1-.4 .5 .66 .66 0 0 1-.1-.9zM95.3 57v1l-.6-1v1"/>
<path d="M95.3 53.4l.4 .6M95.7 53l-.5 .5M95.8 57.4h.3M95.9 51.4l.1-.1 .3 .1v.6M95.9 51.3v.7M96.1 52v.6M96.1 52.1l.1-.1h.3v.6M96.2 57h-.4v1M97.4 55.5l.2 1 .2-.8 .2 .8 .2-1M97.5 40.2a.59 .59 0 0 1 1 .2 .57 .57 0 0 1-1-.1zM98.5 41v.5M98.5 41.3h-1l.2 .2"/>
<path d="M98.6 55.6l.4-.1 .1 .2-.6 .8h.6M99 52.6h.8l.2 .2-.1 .3-.1 .1h-.8M99.3 51.7h.7M99.6 51.6v.6l-.7-.2M100 44.1l.4-.1 .2 .2-.6 .8h.6M100 46h.4l.2 .2-.6 .8h.6M100 55.5h-.4l-.1 .4 .2-.1 .3 .1 .1 .1-.1 .4-.1 .1-.4-.1M100.6 55.5a.33 .33 0 0 1 .4 0 .33 .33 0 0 1 .1 .3v.3a.33 .33 0 0 1-.3 .4 .33 .33 0 0 1-.3-.4v-.3zM100.7 56.2l.3 .2M100.9 44h.7l-.5 1M100.9 46h.7l-.5 1M101 56.4l.2 .2"/>
<path d="M101.5 56.5h.6M101.5 55.7l.3-.2v1M101.9 44.5l.5-.1 .1-.1v-.2l-.2-.1h-.4v1M101.9 46.5l.5-.1 .1-.1v-.3h-.2h-.4v1M102.2 44.5l.3 .5M102.2 46.5l.3 .5M102.3 43h.5M102.3 42.2l.2-.2v1M102.5 55.6l.4-.1 .1 .2-.6 .8h.6M103.3 42.3v.6l.2 .1 .2-.1M103.6 55.9l-.2-.2 .2-.2h.3l.1 .1-.2 .3M103.6 55.9l-.2 .2v.2l.2 .2 .3-.1 .1-.1v-.2l-.2-.2"/>
<path d="M103.6 55.9h.2M103.7 42.3v.7M103.8 40.2l.2-.2v1M103.8 41h.5M104.4 52.1a.59 .59 0 0 1 1 .1 .57 .57 0 0 1-1 0zM104.4 53a.59 .59 0 0 1 1 .2 .57 .57 0 0 1-1-.1zM104.7 51.5h.7M104.7 55.5v.7a.32 .32 0 0 1-.4 .3M104.8 40.3v.6l.2 .1 .2-.1M105 55.5l.4 1 .3-1M105.2 40.3v.7M105.4 53.8v.6"/>
<path d="M105.4 54.1h-1l.2 .3M105.4 51.1h-.7v.2l.1 .2M106.6 55.5h-.4l-.2 .1v.2l.5 .2 .1 .3-.2 .2-.4-.1M106.8 41.5l.5-.1 .1-.1v-.2l-.2-.1h-.4v1M106.9 45.8h.8l.2 .2v.2l-.2 .2h-.8M106.9 45.4v-.6l.3 .3 .1-.3h.5l.1 .2-.1 .4M107.1 41.5l.3 .5M107.8 41.5l.5-.1 .1-.1v-.2l-.2-.1h-.4v1M108.8 41.1l.4-.1 .2 .2-.7 .8h.7M109.5 53.1a.54 .54 0 0 1 1 .2 .57 .57 0 0 1-1-.1zM109.5 52.1a.54 .54 0 0 1 1 .2 .57 .57 0 0 1-1 0zM109.8 51.6h.7"/>
<path d="M109.9 41h.1a.53 .53 0 0 1 .3 .5 .53 .53 0 0 1-.3 .5 .67 .67 0 0 1-.1-1zM110.2 59.2h.5M110.4 59.2v1M110.5 54.2h-1l.2 .3M110.5 53.9v.6M110.5 51.2h-.7v.2l.1 .2M110.6 56l.4-.1 .2 .3-.6 .7h.6M110.9 40.9l-.2 .7h.6M111 59.8l.5-.1-.1-.2h-.2l-.2 .1 .1 .5h.3M111.2 41.3v.7M111.2 47a.54 .54 0 0 1 .9 .2 .57 .57 0 0 1-1 0zM111.2 48a.54 .54 0 0 1 .9 .2 .57 .57 0 0 1-1-.1z"/>
<path d="M111.4 46.5h.7M111.6 55.9v1M111.8 56.3l.4 .6M111.8 41h.1a.53 .53 0 0 1 .3 .5 .53 .53 0 0 1-.3 .5 .67 .67 0 0 1-.1-1zM112 50.2h.6M112.1 49.4l.2-.2v1M112.1 49.4h-.1M112.1 46.1h-.6l-.1 .2 .1 .2M112.1 49.1h-1l.3 .3M112.1 48.8v.6M112.2 55.9l-.6 .6M112.2 55.1h.6"/>
<path d="M112.3 59.5h-.3l-.1 .1v.2l.4 .1v.2h-.4M112.5 55.1v1M112.6 56l.4-.1 .2 .3-.7 .7h.7M112.6 59.5h.4M112.7 59.2v.8l.3 .2M113.1 55.6h.5l.1-.2v-.2l-.2-.1h-.4v1M113.3 59.7l.5-.1 .1-.1-.1-.2-.1-.1h-.4v1M113.5 49.2h-.5l-.1 .4 .2-.1 .3 .1 .1 .1v.4l-.2 .1-.4-.1M113.9 49.5h.3l.2 .2-.1 .4h-.4M113.9 49.5v1M114.1 43h.5M114.1 42.3l.2-.3v1"/>
<path d="M114.3 59.6l.1-.1 .3 .1 .1 .4-.1 .1-.3 .1-.1-.1zM114.3 55.1l-.2 .7h.6M114.6 55.4v.7M114.8 55.5v1h.4M115.2 42a.53 .53 0 0 1 .4 .5 .53 .53 0 0 1-.4 .5 .67 .67 0 0 1 0-1zM115.2 59.2v.1M115.2 59.5v.7M115.3 49v1l-.6-1v1M115.5 49.5v-.7l.4 .4 .1-.3h.4l.1 .1-.1 .5M115.5 49.7v.6M115.5 50h1M115.5 54.3l.5 .3"/>
<path d="M115.5 53.9l.1 .1M115.6 58.1l.2-.1 .2 .2a.27 .27 0 0 1 .2-.2 .27 .27 0 0 1 .3 .2v.4h-1zM115.6 56h.3M115.7 59.5v.7M115.7 59.6l.1-.1h.3v.7M115.9 53.5h.6M115.9 52.8l.3-.3v1M115.9 56.1l.2-.2h.3l.1 .2v.3l-.2 .1h-.2l-.2-.2M115.9 56.1l-.2-.2-.2 .2 .1 .3 .1 .1 .2-.2M115.9 56.1v.2M116 58.2v.4M116 54.6h.5"/>
<path d="M116 54.6l-.5 .4M116.1 55.5h-.5v1h.5M116.1 42h.1a.53 .53 0 0 1 .3 .5 .53 .53 0 0 1-.3 .5 .67 .67 0 0 1-.1-1zM116.1 50.6v.8M116.1 54.7v.8M116.2 59v.5M116.3 49.1a.47 .47 0 0 0-.6 .3 .47 .47 0 0 0 .4 .6l.2-.1M116.4 59.5h.4M116.5 55.5a.5 .5 0 0 1 .6 .5 .5 .5 0 0 1-.6 .5zM116.5 51.8v.6l-.7-.6-.3 .2 .1 .4M116.5 53.4v.9l-.6-.6h-.2l-.2 .2M116.5 54.1l-.6-.6-.2-.1-.2 .2v.5l.1 .2"/>
<path d="M116.5 56.9h-1l.7 .3-.7 .4h1M116.5 58.9l-1 .3 1 .4M116.5 53.1l-1-.4v.7M116.6 59.2v.8l.2 .2M116.7 49.5h.5l.1-.2v-.2l-.2-.1h-.4v1M116.9 46v.5l.4 .1-.1-.2 .1-.3 .1-.1h.4l.1 .2-.1 .4M116.9 52.5v1M117 42.3v.7M117 42.4l.1-.1 .2 .1 .1 .6M117.1 52.9l.4 .6M117.2 45.6h1M117.2 45.6v-.3l.2-.2 .4 .1v.4"/>
<path d="M117.5 52.5l-.6 .6M117.7 50h.6M117.7 49.3l.3-.3v1M117.9 47.2h-1l.2 .3M117.9 46.9v.6M118.1 55.5l.3 .5M118.4 56v.5M118.7 50h.5M118.7 49.3l.2-.3v1M118.8 55.5l-.4 .5M119.6 50h.6M119.6 49.3l.3-.3v1"/>
<path d="M120.5 49h.7l-.5 1M120.6 48.2h.6M120.6 47.5l.3-.3v1M121 44.4l1 .3-.7 .2 .7 .2-1 .2M121 45.6v.4l.1 .1h.2l.2-.4 .3-.1 .2 .2-.1 .4M121 49.9h.6M121 49.1l.3-.2v1M121.3 43.6h.7M121.6 49.6h.7M121.6 43.5v.6l-.7-.2M121.7 47.2h.1a.53 .53 0 0 1 .3 .5 .53 .53 0 0 1-.3 .5 .67 .67 0 0 1-.1-1zM122.1 48.9h.1a.53 .53 0 0 1 .4 .5 .53 .53 0 0 1-.4 .5 .67 .67 0 0 1-.1-1z"/>
<path d="M122.5 47.5l.1 .6 .2 .1 .2-.1M122.7 49h.6l-.3 .4 .3 .1v.4l-.2 .1-.4-.1M123 49.2v.6l.3 .1 .1-.1M123 47.5v.7M123.4 49.2v.7M123.7 49.9v.1M124.1 49h.6l-.3 .4 .3 .1v.4l-.1 .1-.5-.1M124.9 50.1h.8M126 48.3h.1M126 44.2l.3-.1 .1 .2a.27 .27 0 0 1 .3-.2 .27 .27 0 0 1 .3 .2v.4h-1zM126.3 47h.7M126.3 48.3h.7"/>
<path d="M126.3 42v.3M126.3 42.5v.4M126.3 46.7l.2 .3M126.3 43.2h.7M126.3 40.7h.7M126.3 46l.5-.1 .1 .1 .1 .2-.2 .2h-.3l-.2-.2zM126.3 47.4v.3l.2 .2 .4-.1v-.4M126.3 41.2l.5-.1 .1 .1 .1 .3-.2 .2h-.3l-.2-.2zM126.4 44.3v.4M126.5 49.1l-.4-.1-.2 .2 .1 .2 .4 .2v.3l-.1 .1h-.4M126.9 43.2l.1 .2-.1 .2-.6 .1M126.9 49.1a.33 .33 0 0 1 .4-.1 .33 .33 0 0 1 .2 .3v.4a.33 .33 0 0 1-.3 .3 .33 .33 0 0 1-.4-.3z"/>
<path d="M127 48.8h-1l.7 .3-.7 .3h1M127 42l-.2 .2h-.8M127 42.5l-.2 .3h-.8M127 40.3h-.7v.3l.1 .1M127.8 49h.6M128.1 49v1M128.7 49.1l.3-.1 .2 .1v.2l-.6 .7h.6M129.6 49.1l.4-.1 .2 .3-.6 .7h.6M129.9 46.6a.5 .5 0 0 1 .6 .5 .5 .5 0 0 1-.6 .5zM130.5 49h.6l-.3 .4 .3 .1v.4l-.2 .1-.4-.1M130.9 47.3l.4-.1v-.2l-.3-.1-.1 .2v.5h.4M131 43.9v.7a.32 .32 0 0 1-.3 .3"/>
<path d="M131.5 44.9h.5M131.5 44.2l.3-.3v1M131.8 47l.3-.1 .1 .2-.1 .5h-.3M131.8 46.6v1M132.4 44l.4-.1 .2 .3-.6 .7h.6M132.7 46.9v.7h.3l.1-.1M133.1 46.9v.7M133.2 45h.6l-.4 1M134 47l-.3-.1-.2 .2 .1 .5h.4M134 46.9v.8l-.2 .2h-.2M134.4 44.9l-.2 .7h.6M134.6 45.3v.7"/>
<path d="M135 46l.3-1 .4 1M135.1 45.7h.5M135.8 53.6h.7a.32 .32 0 0 1 .3 .4M136 45v1M136 45.4h.6M136.2 51.8l-.2-.1-.2 .1v.2l.1 .2 .3-.2M136.2 51.8l.2-.1h.2l.2 .1v.2l-.2 .2h-.2l-.2-.2M136.2 51.8v.2M136.6 45v1M136.8 52.6v.6l-.8-.6-.2 .2v.4M136.8 45.9a.59 .59 0 0 1 .9 .2 .57 .57 0 0 1-1-.1zM137.2 45.3v-.5l-.1-.1-.3 .1-.1 .1v.4h1"/>
<path d="M137.6 45a.47 .47 0 0 0-.6 .4 .47 .47 0 0 0 .4 .6l.2-.1M137.7 46.7v.6l-.7-.6-.3 .2 .1 .4M137.7 47.6v.7l-.7-.7-.2 .1-.1 .1 .1 .4M137.7 44.7l-.5 .4M137.8 41.4h.4l.2 .2-.6 .8h.6M137.9 45h.6M138 44l.4-.1 .2 .3-.6 .7h.6M138.2 45v1M138.8 46h.5M138.8 45.2l.3-.2v1M139 44l.4-.1 .2 .3-.7 .7h.7M139 41.3l-.2 .7h.6"/>
<path d="M139.2 41.7v.7M139.7 41.9l.5-.1 .1-.1v-.3h-.2h-.4v1M139.8 42.6l.4-1 .3 1M139.9 42.3h.5M140.2 44.9a.53 .53 0 0 0 .3-.5 .53 .53 0 0 0-.3-.5 .62 .62 0 0 0 .1 1.1M140.2 45a.5 .5 0 0 0-.5 .4 .5 .5 0 0 0 .5 .6l.1-.1v-.4h-.1M140.7 45h.6l-.3 .3 .3 .1v.5l-.2 .1-.4-.1M140.7 41.6h.6M140.7 43.9a.59 .59 0 0 1 1 .1 .57 .57 0 0 1-1 0zM140.7 44.8a.59 .59 0 0 1 1 .2 .57 .57 0 0 1-1-.1zM140.9 44.5l.5-.1 .1-.1v-.3l-.2-.1h-.4v1M141 41.6v1"/>
<path d="M141 43.3h.7M141.2 44.5l.3 .4M141.2 50.1v-.6l.4 .3 .1-.3h.4l.1 .2-.1 .4M141.2 55.8h.7a.32 .32 0 0 1 .3 .4M141.2 53.9v.6M141.2 54.2h1M141.2 51.8h1M141.2 51.3h1M141.3 54.8l-.1 .4 .1 .1h.3l.2-.4 .2-.1 .2 .2v.3M141.5 41.3l-.9 1.3M141.5 41.6h.4h.2v.2l-.6 .8h.6M141.7 42.9h-.6l-.1 .2 .1 .2"/>
<path d="M141.7 45.6v.6M141.7 45.9h-1l.3 .3M141.7 45h.4h.1v.2l-.6 .8h.6M141.7 51.3v.5M141.7 52.8v-.5h-.2h-.2l-.1 .1v.4h1M141.8 41.9l.5-.1 .1-.1-.1-.3h-.1h-.4v1M142 41.9l.4 .5M142.7 41.5l-.2 .7h.6M143 41.9v.7M143.2 45h-.4h-.1v.3l.4 .2 .1 .3-.2 .2-.4-.1M143.5 41.4h.4l.2 .2M143.6 45.4h.4"/>
<path d="M144.1 41.6a.47 .47 0 0 0-.7 .4 .47 .47 0 0 0 .5 .6l.2-.1M144.1 41.6l-.6 .8h.6M144.1 45h-.5v1h.5M144.5 45.6h.8M144.7 53.8h.7a.32 .32 0 0 1 .3 .4M144.7 41.3l-.2 .7h.6M144.9 41.7v.7M145 41.6h-.4h-.1v.3l.4 .2 .1 .3-.2 .2-.3-.1M145 51.9h.7M145.4 51.8v.6l-.8-.2M145.5 41.8l.2-.1 .2 .1M145.5 41.7v.7"/>
<path d="M145.5 41.6h.1a.54 .54 0 0 1 .4 .5 .54 .54 0 0 1-.4 .5l-.1-.1-.1-.3zM145.7 45h.6l-.4 1M145.7 53.1h-1l.3 .3M145.7 52.8v.6M145.9 41.8v.6M145.9 41.7h.4v.7M145.9 41.7v.1M146.4 42.6h.5M146.4 41.8l.2-.2v1M146.8 41.8l.3-.1 .1 .1M146.8 41.7v.7M147.2 41.8l.2-.1h.2l.1 .7"/>
<path d="M147.2 41.8v.6M147.4 42.2h.7M148.4 40.8h.7l-.4 .3 .3 .1v.5l-.1 .1-.5-.1M148.5 43.1h.7l-.4 .3 .3 .1v.5l-.1 .1-.5-.1M149.1 41.6h-.4l-.2 .1 .1 .3 .5 .2v.3l-.2 .1-.4-.1M149.4 41.6h.6M149.5 40.8v1M149.6 43.1v1M149.6 41.2l.5 .6M149.7 41.6v1M149.7 43.5l.5 .6M150.1 40.8l-.6 .5"/>
<path d="M150.1 55.9h.8a.32 .32 0 0 1 .2 .4M150.1 52h1M150.1 54.1v.6M150.1 54.4h1M150.1 51.4h1M150.2 43.1l-.6 .5M150.2 54.9l-.1 .4 .2 .2 .3-.1 .2-.4h.2l.1 .1v.4M150.3 41.6v.8l.2 .2 .3-.1 .1-.1v-.8M150.5 49.8h.6M150.6 51.4v.6M150.7 53l-.1-.5-.1-.1-.3 .1-.1 .1v.4h1M150.8 49.6v.6l-.7-.2"/>
<path d="M151 41.2l-.2 .2h-.2l-.2-.2 .1-.4h.3l.2 .1a.66 .66 0 0 1-.3 .9h-.2M151.1 43.5l-.2 .2h-.2l-.2-.2 .1-.4h.3l.2 .1a.66 .66 0 0 1-.3 .9h-.2M151.4 42.6v-1l.3 .7 .3-.7v1M153.1 54.8h.6M153.1 54.1l.3-.3v1M153.7 40.7a.59 .59 0 0 1 .9 .2 .57 .57 0 0 1-1-.1zM154.1 57a.47 .47 0 0 0-.6 .3 .47 .47 0 0 0 .4 .6l.2-.1M154.2 53.8h.1a.53 .53 0 0 1 .3 .5 .53 .53 0 0 1-.3 .5 .66 .66 0 0 1-.1-1zM154.5 56.9h.6l-.3 .4h.2v.5l-.1 .1-.4-.1M154.6 41.8h-1l.3 .3M154.6 41.5v.6M155 46.4h1"/>
<path d="M155 45.9l.6 .5M155.1 53.8h.1a.53 .53 0 0 1 .4 .5 .53 .53 0 0 1-.4 .5 .66 .66 0 0 1-.1-1zM155.4 56.9h.6l-.3 .4h.3v.5l-.1 .1-.5-.1M155.6 45.7v.3a.68 .68 0 0 0 1 0l-.1-.3-.4-.1-.1 .2v.2l.1 .2M155.6 43.8v.5h.5l-.1-.1v-.4l.1-.1 .4 .1 .1 .1-.1 .4M155.6 42.9a.59 .59 0 0 1 1 .2 .57 .57 0 0 1-1-.1zM155.6 40.9v.4l.2 .1h.2l.2-.5h.3l.1 .2-.1 .3M155.9 44.8h.7M156 54.1v.6l.3 .1 .1-.1M156 46.9v.6l-.7-.6-.3 .2 .1 .3M156 47.8v.6M156 48.1h-1l.3 .3"/>
<path d="M156 45.9l-.6 .4M156.1 40.4v-.4l-.2-.1h-.2l-.1 .2v.3h1M156.1 47.2v-.5l-.2-.1h-.2l-.1 .2v.4h1M156.2 44.6v.7l-.7-.3M156.3 47.6v.5M156.4 54.1v.7M156.5 49.1h1M156.5 48.5l.5 .6M156.6 49.6a.54 .54 0 0 1 .9 .3 .57 .57 0 0 1-1-.1zM156.6 41.8v.6M156.6 47.5l-1 .3 1 .4M156.6 42.1h-1l.3 .3"/>
<path d="M156.9 44h1M156.9 43.5l.6 .5M157.3 46.9h.7M157.5 50.5v.6l-.7-.6-.3 .2 .1 .4M157.5 48.5l-.6 .5M157.8 53.1a.59 .59 0 0 1 1 .1 .57 .57 0 0 1-1-.1zM157.9 44.5v.6l-.7-.6-.3 .2 .1 .3M157.9 42.5v.6l-.7-.6-.3 .2 .1 .4M157.9 43.5l-.5 .4M158 47.3v.6M158 47.6h-1l.3 .3M158 46.5h-.6l-.1 .3 .1 .1"/>
<path d="M158.1 52.1h.7M158.7 52.1l.1 .1-.1 .2-.6 .1M158.8 53.9v.5M158.8 54.1h-1l.3 .3M158.9 49.2h.6M158.9 48.5l.3-.3v1M159 42.6h.8l.2 .2v.2l-.2 .1h-.8M159 41.7v.3a.66 .66 0 0 0 1 0l-.1-.3-.4-.1-.1 .2v.2l.1 .2M159.8 53.1a.59 .59 0 0 1 1 .2 .57 .57 0 0 1-1-.1zM159.9 48.6v.6M159.9 48.7l.1-.1h.3v.6M160.1 52.1h.7"/>
<path d="M160.2 45.1v-.6l.3 .3 .1-.3h.5l.1 .2-.1 .4M160.2 54.1h1l-1 .6h1M160.2 47v-.6l.3 .4 .1-.3h.5l.1 .1-.1 .4M160.2 50.3v.5h.4l-.1-.1 .1-.4 .1-.1 .4 .1 .1 .1-.1 .4M160.2 53.2v.3a.67 .67 0 0 0 1 0l-.1-.4h-.4l-.2 .2 .1 .3 .1 .1M160.2 49.4v.5M160.2 49.7h1M160.2 43.5l.5 .4M160.2 56.1v.4l.1 .1h.2l.2-.4 .3-.1 .2 .2-.1 .4M160.3 52.2a.54 .54 0 0 1 .9 .3 .57 .57 0 0 1-1-.1zM160.5 51.3h.7M160.7 52.1l.1 .1-.1 .2-.6 .1"/>
<path d="M160.7 43.9h.5M160.7 55.7l-.1-.5-.1-.1h-.2l-.1 .2v.4h1M160.7 46l-.1-.5-.1-.1-.2 .1-.1 .1v.4h1M160.7 43.9l-.5 .3M160.8 54.2h-1l.3 .2M160.8 53.9v.5M160.8 47.4v.8M160.8 51.1v.7l-.7-.3M160.9 48.6v.5M161.2 55.1l-.5 .3M161.2 48.5l-1 .4 1 .3M161.2 45.4l-.5 .4"/>
<path d="M161.4 58.4h.6M161.7 58.4v1M161.8 53.1a.59 .59 0 0 1 1 .1 .57 .57 0 0 1-1-.1zM162.1 52.1h.7M162.1 48.8h.7M162.3 59l.5-.1-.1-.2h-.3l-.1 .1v.5h.4M162.7 52.1l.1 .1-.1 .2-.6 .1M162.7 50.3h.1M162.8 53.9v.5M162.8 54.1h-1l.2 .3M162.8 49.3v.6l-.7-.6-.3 .2 .1 .3M162.8 51h-1l.3 .3"/>
<path d="M162.8 48.4l-.6 .1-.1 .2 .1 .1M162.8 50.7v.6M163.5 54.3h.6M163.5 58.7h-.2l-.2 .1 .1 .2 .3 .1v.2h-.4M163.8 54.3v1M163.9 58.7h.3M164 58.4v.8l.2 .2M164.3 49.6v1h.4M164.4 44a.59 .59 0 0 1 .9 .2 .57 .57 0 0 1-1-.1zM164.4 54.8h.5l.1-.2-.1-.2-.1-.1h-.4v1M164.4 40a.54 .54 0 0 1 .9 .3 .57 .57 0 0 1-1-.1zM164.4 41a.54 .54 0 0 1 .9 .2 .57 .57 0 0 1-1-.1z"/>
<path d="M164.6 58.9l.4-.1 .1-.1v-.2l-.1-.1h-.4v1M164.8 43.4v-.4l-.2-.1h-.2l-.1 .2v.3h1M165.3 54.3h.6l-.3 .4 .3 .1v.4l-.2 .1-.4-.1M165.3 44.8v.6M165.3 45.1h-1l.3 .3M165.3 42.9l-.5 .3M165.3 41.8v.6M165.3 42.1h-1l.3 .3M165.5 49.6h-.4l-.1 .5 .2-.1h.3l.1 .2-.1 .3-.1 .1-.4-.1M165.6 58.7h.3l.1 .2v.3l-.1 .2-.3-.1-.1-.1zM166.5 58.4v.1M166.5 58.7v.7"/>
<path d="M167 58.8l.1-.1h.2l.1 .7M167 58.7v.7M167.7 58.7h.4M167.9 58.4v.8l.2 .2M170.3 53.6a.59 .59 0 0 1 1 .2 .57 .57 0 0 1-1-.1zM170.6 52.6h.7M171.2 52.6l.1 .1-.1 .2-.6 .1M171.3 54.4v.5M171.3 54.7h-1l.3 .2M175 47v.7a.32 .32 0 0 1-.4 .3M175.5 47.3h.3l.1 .7M175.9 47.5l-.4 .1-.1 .1 .1 .3 .4-.1"/>
<path d="M176.8 47.3h-.3l-.2 .2 .1 .4h.4M177.2 47v1M177.3 47.6l.3 .4M177.6 47.3l-.4 .4M179.2 47h-.3a.67 .67 0 0 0 0 1l.4-.1v-.4l-.2-.2h-.2l-.2 .2M179.7 47.9v.1M180.1 47h.6l-.3 .3 .3 .1v.5l-.2 .1-.4-.1M181.6 41.4v.7a.32 .32 0 0 1-.3 .3M181.6 47h-.4l-.1 .4 .2-.1 .3 .1 .1 .1-.1 .4-.1 .1-.4-.1M182.1 47.4l.3-.1 .1 .1M182.1 47.3v.7M182.5 47.4l.2-.1h.2l.1 .7"/>
<path d="M182.5 47.4v.6M182.6 41.4h-.5v.4h.1h.3l.1 .1v.4l-.2 .1-.3-.1M183.5 47.4l.2-.1 .2 .1M183.5 47.3v.7M183.9 47.4l.1-.1h.3v.7M183.9 47.4v.6M24.8 73.9h.6M25.1 73.9v1M25.7 74.3h.4v.6M26.1 74.5h-.3l-.1 .1 .1 .3 .3-.1M27 61.8h.6M27 61.1l.3-.3v1"/>
<path d="M27 74.3l-.2-.1-.2 .2 .1 .4h.3M27.3 74.2h.4M27.5 73.9v.8l.2 .2M28 61.1v.7M28 61.2l.2-.1 .2 .1v.6M28 73.9v.1M28 74.2v.7M28.5 73.9v.8l.2 .2M29 74.6l.5-.1-.1-.2-.3-.1-.1 .2v.4h.4M29.2 66.5h-.3l-.2 .1v.3l.4 .2 .1 .2-.2 .2-.3-.1M29.6 66.5l.2 1 .2-.7 .2 .7 .2-1M30.7 73.9h.3l.2 .2-.2 .3 .2 .1v.2l-.2 .2h-.3z"/>
<path d="M30.7 74.4h.3M31.3 66.5h-.5v.5l.1-.1h.3l.1 .2v.3l-.2 .1-.3-.1M31.7 74.2v.6l.3 .1 .1-.1M32.1 74.2v.7M32.4 74.2h.4M32.6 73.9v.8l.2 .2M33 74.2h.4M33.1 73.9v.8l.3 .2M33.7 74.3l.2-.1 .2 .1 .1 .4-.1 .1-.2 .1-.2-.1zM34.6 74.3l.2-.1 .2 .1v.6M34.6 74.2v.7M43.3 60.4h1"/>
<path d="M44.3 60.8v.6l-.7-.6-.3 .2 .1 .4M71.7 62.9a.4 .4 0 0 0-.5 0 .4 .4 0 0 0-.1 .4 .37 .37 0 0 0 .2 .4 .37 .37 0 0 0 .4 0M72.2 63.8v-1l.3 .7 .3-.7v1M73.5 62.7l-.2 .7h.6M73.7 63.1v.7M92.5 75.4h.7a.32 .32 0 0 1 .3 .4M92.5 76.1v.4l.1 .1h.2l.2-.4 .3-.1 .2 .2-.1 .4M93 74.9l-.1-.5-.1-.1-.2 .1-.1 .1v.4h1M94 79.3h.7l-.5 1M95.2 79.3l-.2 .7h.6M95.5 79.6v.7M96.9 79.8h.5"/>
<path d="M96.9 79.3v1M97.4 79.3v1M98.2 75.4h.7a.32 .32 0 0 1 .3 .4M98.2 76.1v.4l.1 .2 .3-.1 .2-.5h.3l.1 .2-.1 .4M98.5 79.4a.47 .47 0 0 0-.7 .3 .47 .47 0 0 0 .5 .6l.2-.1M98.7 74.9l-.1-.5-.1-.1-.2 .1-.1 .1v.4h1M98.8 79.3h.5M99 79.3v1M99.6 79.6l.3-.3v1M99.8 73.9h.6M100.1 73.9v1M100.7 74.3h.4v.6"/>
<path d="M101.1 79.4a.47 .47 0 0 0-.5 .4 .47 .47 0 0 0 .5 .5l.1-.4h-.2M101.1 74.5h-.3l-.1 .1 .1 .3 .3-.1M101.2 62.5h-.3l-.2 .1 .1 .3 .4 .2v.3l-.2 .1-.3-.1M101.5 79.3h.6l-.3 .4 .3 .1v.4l-.2 .1-.4-.1M101.6 62.5l.2 1 .2-.8 .2 .8 .2-1M102 74.3l-.2-.1-.2 .2 .1 .4h.3M102.3 74.2h.4M102.5 73.9v.8l.2 .2M102.5 79.4l.2-.1 .3 .1M103 73.9v.1M103 74.2v.7M103.1 79.4v.4"/>
<path d="M103.2 62.5h-.2a.67 .67 0 0 0 0 1l.3-.1v-.4l-.2-.2h-.1l-.2 .2M103.5 73.9v.8l.2 .2M103.5 79.8h-1l.1-.5 .1-.1 .3 .1 .1 .3-.6 .7h.6M103.5 79.2l-.4 .3M104 74.6l.5-.1-.1-.2-.3-.1-.1 .2v.4h.4M104 79.4l-.3-.1-.2 .1v.3l.4 .2 .1 .2-.1 .2h-.4M104.5 79.8h.3M104.5 79.2l.6 .3M104.9 79.3h-.4v1h.4M105.1 79.5h.4M105.1 79.5l-.6 .3M105.4 79.9h.7"/>
<path d="M105.7 73.9h.3l.2 .2-.2 .3 .2 .1v.2l-.2 .2h-.3zM105.7 74.4h.3M106.5 79.3h.7l-.4 1M106.5 79.9l.6 .6M106.7 74.2v.6l.3 .1 .1-.1M107.1 74.2v.7M107.4 74.2h.4M107.5 79v.6l-.7-.6-.3 .2 .1 .4M107.5 79.9l-.5 .5M107.6 73.9v.8l.2 .2M108 74.2h.4M108.1 73.9v.8l.3 .2"/>
<path d="M108.5 79.5l.6 .5M108.8 74.3l.2-.1 .2 .2v.3l-.2 .2-.2-.1-.1-.1zM109.5 79.5l-.5 .4M109.6 74.3l.2-.1 .2 .1v.6M109.6 74.2v.7M114.2 67.3v-1l.3 .7 .4-.7v1M115.4 66.7l.1-.1 .3 .1v.4l-.1 .2h-.2l-.1-.1zM116.3 66.6v.7h.2l.2-.1M116.7 66.6v.7M117.2 66.7l.1-.1 .2 .1 .1 .6M117.2 66.6v.7M117.9 66.6h.4"/>
<path d="M118.1 66.3v.9l.2 .1M118.2 63.4h.6M118.2 63v1M118.6 66.3v.1M118.6 66.6v.7M118.8 63v1M119.1 66.7l.2-.1 .2 .1v.6M119.1 66.6v.7M119.8 63h-.5l-.1 .4 .2-.1 .3 .1 .1 .1v.4l-.2 .1-.4-.1M120.5 66.7l-.3-.1-.2 .2 .1 .5h.4M120.5 66.6v.8l-.2 .2h-.3M120.9 66.3v1"/>
<path d="M120.9 66.8h.6M121.5 66.3v1M122 66.7l.1-.1 .3 .1 .1 .4-.1 .2h-.3l-.1-.1zM122.9 66.3v.9l.1 .1M123.4 67l.4-.1v-.2l-.3-.1-.1 .2v.5h.4M163.2 67.3v-1l.3 .7 .4-.7v1M164.4 66.7l.1-.1 .3 .1v.4l-.1 .2h-.2l-.1-.1zM165.3 66.6v.7h.2l.2-.1M165.7 66.6v.7M166.2 66.6v.7M166.2 66.7l.1-.1 .2 .1 .1 .6M166.9 66.6h.4"/>
<path d="M167.1 66.3v.9l.2 .1M167.2 63v1M167.2 63.4h.6M167.6 66.3v.1M167.6 66.6v.7M167.8 63v1M168.1 66.6v.7M168.1 66.7l.2-.1 .2 .1v.6M168.5 62.9l-.3 .7h.7M168.7 63.3v.7M169.5 66.6v.8l-.2 .2h-.3M169.5 66.7l-.3-.1-.2 .2 .1 .5h.4"/>
<path d="M169.9 66.3v1M169.9 66.8h.6M170.5 66.3v1M171 66.7l.1-.1 .3 .1 .1 .4-.1 .2h-.3l-.1-.1zM171.9 66.3v.9l.1 .1M172.4 67l.4-.1v-.2l-.3-.1-.1 .2v.5h.4M174.8 73.9h.6M175.1 73.9v1M175.2 62.5h-.3l-.2 .1 .1 .3 .4 .2v.3l-.2 .1-.3-.1M175.6 62.5l.2 1 .2-.8 .2 .8 .2-1M175.7 74.3h.4v.6M176.1 74.5h-.3l-.1 .1 .1 .3 .3-.1"/>
<path d="M176.7 62.5h.7l-.4 1M177 74.3l-.2-.1-.2 .2 .1 .4h.3M177.3 74.2h.4M177.5 73.9v.8l.2 .2M178 73.9v.1M178 74.2v.7M178.5 73.9v.8l.2 .2M179 74.6l.5-.1-.1-.2-.3-.1-.1 .2v.4h.4M180.7 73.9h.3l.2 .2-.1 .2-.1 .1 .2 .1v.2l-.2 .2h-.3zM180.7 74.4h.3M181.7 74.2v.6l.3 .1 .1-.1M182.1 74.2v.7"/>
<path d="M182.4 74.2h.4M182.6 73.9v.8l.2 .2M183 74.2h.4M183.1 73.9v.8l.3 .2M183.8 74.3l.2-.1 .2 .2v.3l-.2 .2-.2-.1-.1-.1zM184.6 74.3l.2-.1 .2 .1v.6M184.6 74.2v.7M20.5 87.5v.7a.32 .32 0 0 1-.4 .3M21 87.8h.3l.1 .7M21.4 88l-.4 .1-.1 .1 .1 .3 .4-.1M22.3 87.8h-.3l-.2 .2 .1 .4h.4M22.7 87.5v1"/>
<path d="M22.8 88.1l.3 .4M23.1 87.8l-.4 .4M24.7 87.5h-.3a.67 .67 0 0 0 0 1l.4-.1v-.4l-.2-.2-.3 .1-.1 .1M25.2 88.4v.1M25.6 87.5h.6l-.3 .3 .3 .1v.5l-.2 .1-.4-.1M27.1 87.5h-.4l-.1 .4 .2-.1 .3 .1 .1 .1-.1 .4-.1 .1-.4-.1M27.2 82.3v.8a.32 .32 0 0 1-.3 .2M27.6 87.8v.7M27.6 87.9l.3-.1 .1 .1M27.7 82.4l.4-.1 .1 .3-.6 .7h.6M28 87.9v.6M28 87.9l.2-.1h.2l.1 .7"/>
<path d="M28.8 82.4l.1-.1a.53 .53 0 0 1 .3 .5 .53 .53 0 0 1-.3 .5 .67 .67 0 0 1-.1-.9zM29 87.8v.7M29 87.9l.2-.1 .2 .1M29.4 87.9v.6M29.4 87.9l.1-.1h.3v.7M95.9 80.3l.3-1 .3 1M95.9 80h.5M99.6 80.3h.6M102.5 83a.5 .5 0 0 1 .5 .5 .5 .5 0 0 1-.5 .5zM102.5 82v.4h1v-.4M102.6 81.2a.54 .54 0 0 1 .6-.2 .54 .54 0 0 1 .3 .5h-1zM103 82.1v.3"/>
<path d="M103.4 83.6l.5-.1-.1-.2h-.3l-.1 .1 .1 .5h.3M103.5 82.8v.5h-1M103.8 97.5v1M103.8 97.9h.5M103.9 80.8v.7a.32 .32 0 0 1-.4 .3M104.3 81.8h.6M104.3 81l.3-.2v1M104.3 83.3h.3l.2 .2-.1 .4h-.4M104.3 83v1M104.3 97.5v1M104.5 81.9v.5h1v-.5M104.6 81.1a.54 .54 0 0 1 .6-.2 .54 .54 0 0 1 .3 .6h-1z"/>
<path d="M104.8 98.5h.5M104.8 97.7l.2-.2v1M105 82v.4M105.2 83.3l.1 .6 .2 .1 .1-.1M105.5 82.7v.5h-1M105.6 83.3v.7M105.7 80.8h-.3a.67 .67 0 0 0 0 1l.4-.1v-.4l-.2-.2-.2 .1-.1 .1M106.2 97.5h-.3a.68 .68 0 0 0 0 1l.3-.1 .1-.4-.2-.2h-.2l-.2 .2M106.5 80.5h1M106.5 83.3h-.2l-.2 .2 .1 .4h.3M106.5 83.3v.8l-.1 .2-.3-.1M107.5 80.9v.7l-.7-.7-.2 .1-.1 .1 .1 .4"/>
<path d="M108.5 80h1M109.5 80.8h-1l.3 .2M109.5 80.5v.5M118.4 93.3h.7a.32 .32 0 0 1 .3 .4M119.4 92.3v.6l-.7-.6-.3 .2 .1 .4M119.4 91.7l-1-.4v.7M176 88.5v.7a.32 .32 0 0 1-.4 .3M176.5 88.8h.3l.1 .7M176.9 89l-.4 .1-.1 .1 .1 .3 .4-.1M177.8 88.8h-.3l-.2 .2 .1 .4h.4M178.2 88.5v1M178.3 89.1l.3 .4"/>
<path d="M178.6 88.8l-.4 .4M180.2 88.5h-.3a.67 .67 0 0 0 0 1l.4-.1v-.4l-.2-.2h-.2l-.2 .2M180.7 89.4v.1M181.1 88.5h.6l-.3 .3 .3 .1v.5l-.2 .1-.4-.1M181.1 82.4v.7a.32 .32 0 0 1-.3 .2M181.6 83.3h.5M181.6 82.6l.3-.2v.9M182.6 88.5h-.4l-.1 .4 .2-.1 .3 .1 .1 .1-.1 .4-.1 .1-.4-.1M182.7 82.8l-.2 .2v.2l.2 .1h.3l.1-.1v-.2l-.2-.2M182.7 82.8l-.2-.2 .2-.2h.3l.1 .1-.2 .3M182.7 82.8h.2M183.1 88.9l.3-.1 .1 .1"/>
<path d="M183.1 88.8v.7M183.5 88.9l.2-.1h.2l.1 .7M183.5 88.9v.6M184.5 88.9l.2-.1 .2 .1M184.5 88.8v.7M184.9 88.9l.1-.1h.3v.7M184.9 88.9v.6M22.5 108v.7a.32 .32 0 0 1-.4 .3M23 108.3h.3l.1 .7M23.4 108.5l-.4 .1-.1 .1 .1 .3 .4-.1M24.3 108.3h-.3l-.2 .2 .1 .4h.4M24.7 108v1"/>
<path d="M24.8 108.6l.3 .4M25.1 108.3l-.4 .4M25.2 113.5h-.3l-.2 .1v.2l.4 .2 .1 .3-.2 .2-.3-.1M25.6 113.5l.2 1 .2-.8 .2 .8 .2-1M26.7 108h-.3a.67 .67 0 0 0 0 1l.4-.1v-.4l-.2-.2h-.2l-.2 .2M27 113.9l-.2-.2 .2-.2h.2l.1 .1-.2 .3M27 113.9l-.2 .2v.2l.2 .2 .2-.1 .1-.1v-.2l-.2-.2M27 113.9h.1M27.2 108.9v.1M27.2 102.5v.8a.32 .32 0 0 1-.3 .2M27.6 108h.6l-.3 .3 .3 .1v.5l-.2 .1-.4-.1M27.7 103.5h.5"/>
<path d="M27.7 102.8l.3-.3v1M29.1 108h-.4l-.1 .4 .2-.1 .3 .1 .1 .1-.1 .4-.1 .1-.4-.1M29.2 103l-.2 .2-.3-.1-.1-.1 .1-.4 .3-.1 .1 .1a.66 .66 0 0 1-.2 .9h-.2M29.6 108.4l.3-.1 .1 .1M29.6 108.3v.7M30 108.4l.2-.1h.2l.1 .7M30 108.4v.6M31 108.4l.2-.1 .2 .1M31 108.3v.7M31.4 108.4l.1-.1h.3v.7M31.4 108.4v.6M49 104.1l-.4-.1-.2 .1v.3l.5 .2 .1 .2-.2 .2h-.4"/>
<path d="M49.7 104v.7a.32 .32 0 0 1-.4 .3M50.1 104.5h.5l.1-.2v-.2l-.2-.1h-.4v1M100.2 101.8v-1l.3 .7 .4-.7v1M100.2 113.5h-.3l-.2 .1v.2l.4 .2 .1 .3-.2 .2-.3-.1M100.6 113.5l.2 1 .2-.8 .2 .8 .2-1M101.4 101.2l.2-.1 .2 .2v.3l-.2 .2h-.2l-.1-.2zM102.3 101.1v.7h.2l.2-.1M102.3 113.9l-.2 .2h-.1l-.2-.2 .1-.4h.2l.2 .1a.66 .66 0 0 1-.3 .9h-.1M102.7 101.1v.7M103.2 101.1v.7M103.2 101.2l.1-.1 .2 .1 .1 .6M103.9 101.1h.4"/>
<path d="M104.1 100.8v.9l.2 .1M104.6 100.8v.1M104.6 101.1v.7M105.1 101.2l.2-.1 .2 .1v.6M105.1 101.1v.7M106.5 101.2l-.3-.1-.2 .2 .1 .5h.4M106.5 101.1v.8l-.2 .2h-.3M106.9 100.8v1M106.9 101.3h.6M107.5 100.8v1M108 101.2l.1-.1 .3 .1 .1 .4-.1 .2h-.3l-.1-.1zM108.9 100.8v.9l.1 .1"/>
<path d="M109.4 101.5l.4-.1v-.2l-.3-.1-.1 .2v.5h.4M170.3 114.9h.7a.32 .32 0 0 1 .3 .4M170.3 115.6v.4l.1 .2 .3-.1 .2-.5h.3l.1 .2-.1 .4M170.8 114.4l-.1-.5-.1-.1-.2 .1-.1 .1v.4h1M174.3 114h-.4l-.2 .1v.2l.5 .2 .1 .3-.2 .2-.4-.1M174.6 114l.2 1 .2-.8 .2 .8 .3-1M175.8 115h.6M175.8 114.2l.3-.2v1M176.5 108v.7a.32 .32 0 0 1-.4 .3M176.9 114h.1a.53 .53 0 0 1 .3 .5 .53 .53 0 0 1-.3 .5 .66 .66 0 0 1-.1-1zM177 108.3h.3l.1 .7M177.4 108.5l-.4 .1-.1 .1 .1 .3 .4-.1"/>
<path d="M178.3 108.3h-.3l-.2 .2 .1 .4h.4M178.7 108v1M178.8 108.6l.3 .4M179.1 108.3l-.4 .4M180.7 108h-.3a.67 .67 0 0 0 0 1l.4-.1v-.4l-.2-.2h-.2l-.2 .2M181.1 102.6v.7a.32 .32 0 0 1-.3 .3M181.2 108.9v.1M181.6 102.7l.4-.1 .1 .2-.6 .8h.6M181.6 108h.6l-.3 .3 .3 .1v.5l-.2 .1-.4-.1M182.5 102.7l.4-.1 .2 .2-.6 .8h.6M183.1 108h-.4l-.1 .4 .2-.1 .3 .1 .1 .1-.1 .4-.1 .1-.4-.1M183.6 108.4l.3-.1 .1 .1"/>
<path d="M183.6 108.3v.7M184 108.4l.2-.1h.2l.1 .7M184 108.4v.6M185 108.4l.2-.1 .2 .1M185 108.3v.7M185.4 108.4l.1-.1h.3v.7M185.4 108.4v.6M17.3 125.5h.3M17.8 125.1h-.5v1M18.1 125.1h.1M18.1 125.4v.7M19.1 125.1v1"/>
<path d="M19.1 125.4h-.3l-.2 .2 .1 .4h.4M19.5 125.4l.1 .6 .2 .1 .2-.1M20 125.4v.7M20.9 125.4h-.3l-.2 .2 .1 .4h.4M21.3 125.1h.1M21.3 125.4v.7M21.8 125.4h.3l.1 .7M22.2 125.6l-.3 .1-.2 .1 .2 .3 .3-.1M22.7 125.1v.8l.1 .2M24.8 125.9h.6M25.1 125.9v1M25.7 126.3h.4v.6"/>
<path d="M26.1 126.5h-.3l-.1 .1 .1 .3 .3-.1M27 126.3l-.2-.1-.2 .2 .1 .4h.3M27.3 126.2h.4M27.5 125.9v.8l.2 .2M28 125.9v.1M28 126.2v.7M28.5 125.9v.8l.2 .2M29 126.6l.5-.1-.1-.2-.3-.1-.1 .2v.4h.4M30.7 125.9l.4 .1 .1 .2-.2 .2a.27 .27 0 0 1 .2 .2 .27 .27 0 0 1-.2 .3h-.3zM30.7 126.4h.3M31.7 126.2v.6l.3 .1 .1-.1M32.1 126.2v.7"/>
<path d="M32.4 126.2h.4M32.6 125.9v.8l.2 .2M33 126.2h.4M33.1 125.9v.8l.3 .2M33.7 126.3l.2-.1 .2 .1 .1 .4-.1 .1-.2 .1-.2-.1zM34.6 126.2v.7M34.6 126.3l.2-.1 .2 .1v.6M37.2 131.8v-1l.3 .7 .4-.7v1M38.4 131.2l.1-.1 .3 .1v.4l-.1 .2h-.2l-.1-.1zM39.3 131.1v.7h.2l.2-.1M39.7 131.1v.7M40.2 131.2l.1-.1 .2 .1 .1 .6"/>
<path d="M40.2 131.1v.7M40.8 127.9h.5M40.8 127.5v1M40.9 131.1h.4M41.1 130.8v.9l.2 .1M41.3 127.5v1M41.6 130.8v.1M41.6 131.1v.7M41.8 128.5h.5M41.8 127.7l.2-.2v1M42.1 131.2l.2-.1 .2 .1v.6M42.1 131.1v.7"/>
<path d="M43 127.4l-.3 .7h.6M43.2 127.8v.7M43.5 131.2l-.3-.1-.2 .2 .1 .5h.4M43.5 131.1v.8l-.2 .2h-.3M43.9 131.3h.6M43.9 130.8v1M44.5 130.8v1M45 131.2l.1-.1 .3 .1 .1 .4-.1 .2h-.3l-.1-.1zM45.9 130.8v.9l.1 .1M46.4 131.5l.4-.1v-.2l-.3-.1-.1 .2v.5h.4M99.8 125.9h.6M100.1 125.9v1"/>
<path d="M100.7 126.3h.4v.6M101.1 126.5h-.3l-.1 .1 .1 .3 .3-.1M102 126.3l-.2-.1-.2 .2 .1 .4h.3M102.3 126.2h.4M102.5 125.9v.8l.2 .2M103 125.9v.1M103 126.2v.7M103.5 125.9v.8l.2 .2M104 126.6l.5-.1-.1-.2-.3-.1-.1 .2v.4h.4M105.7 125.9l.4 .1 .1 .2-.2 .2a.27 .27 0 0 1 .2 .2 .27 .27 0 0 1-.2 .3h-.3zM105.7 126.4h.3M106.7 126.2v.6l.3 .1 .1-.1"/>
<path d="M107.1 126.2v.7M107.4 126.2h.4M107.6 125.9v.8l.2 .2M108 126.2h.4M108.1 125.9v.8l.3 .2M108.8 126.3l.2-.1 .2 .2v.3l-.2 .2-.2-.1-.1-.1zM109.6 126.2v.7M109.6 126.3l.2-.1 .2 .1v.6M114.2 125.3v-1l.3 .7 .4-.7v1M115.4 124.7h.2l.2 .1v.3l-.2 .2h-.2l-.1-.2zM116.2 124.7l.1 .6h.2l.2-.1M116.7 124.7v.6"/>
<path d="M117.1 124.8l.2-.1h.2l.1 .6M117.1 124.7v.6M117.9 124.7h.4M118.1 124.3v.9l.2 .1M118.2 121v1M118.2 121.5h.6M118.6 124.3v.1M118.6 124.7v.6M118.8 121v1M119.1 124.8l.1-.1h.3v.6M119.1 124.7v.6M119.7 121h-.3a.67 .67 0 0 0 0 1l.3-.1 .1-.4-.2-.1h-.2l-.2 .1"/>
<path d="M120.4 124.7h-.3l-.1 .1 .1 .5h.3M120.4 124.7v.8l-.2 .2-.2-.1M120.9 124.3v1M120.9 124.8h.6M121.5 124.3v1M122 124.7h.2l.2 .1v.3l-.2 .2h-.2l-.1-.2zM122.9 124.3v.9l.1 .1M123.3 125l.5-.1v-.2h-.3l-.2 .1 .1 .5h.4M146.6 124.7h-.4h-.1v.3l.4 .2 .1 .3-.2 .2-.4-.1M146.9 120.6h-.4l-.2 .1 .1 .3 .5 .2v.3l-.2 .1-.4-.1M147.3 124.7v.7a.32 .32 0 0 1-.4 .3M147.6 120.6v.7a.32 .32 0 0 1-.4 .3"/>
<path d="M147.8 125.2l.5-.1 .1-.1-.1-.3h-.1h-.4v1M148.1 121.1l.5-.1 .1-.1-.1-.3h-.1h-.4v1M163.2 125.3v-1l.3 .7 .4-.7v1M163.2 131.8v-1l.3 .7 .4-.7v1M164.4 124.7l.1-.1 .3 .1v.4l-.1 .2h-.2l-.1-.1zM164.4 131.2l.1-.1 .3 .1v.4l-.1 .2h-.2l-.1-.1zM165.3 124.6v.7h.2l.2-.1M165.3 131.1v.7h.2l.2-.1M165.7 124.6v.7M165.7 131.1v.7M166.2 124.7l.1-.1 .2 .1 .1 .6M166.2 124.6v.7"/>
<path d="M166.2 131.1v.7M166.2 131.2l.1-.1 .2 .1 .1 .6M166.8 127.5v1M166.8 127.9h.5M166.9 124.6h.4M166.9 131.1h.4M167.1 124.3v.9l.2 .1M167.1 130.8v.9l.2 .1M167.2 121v1M167.2 121.4h.6M167.3 127.5v1M167.6 124.3v.1"/>
<path d="M167.6 124.6v.7M167.6 130.8v.1M167.6 131.1v.7M167.8 127.7l.2-.2v1M167.8 128.5h.5M167.8 121v1M168.1 124.7l.2-.1 .2 .1v.6M168.1 124.6v.7M168.1 131.1v.7M168.1 131.2l.2-.1 .2 .1v.6M168.2 121h.7l-.5 1M169.2 127.5h-.4l-.1 .4 .2-.1 .3 .1 .1 .1-.1 .4-.1 .1-.4-.1"/>
<path d="M169.5 124.7l-.3-.1-.2 .2 .1 .5h.4M169.5 124.6v.8l-.2 .2h-.3M169.5 131.1v.8l-.2 .2h-.3M169.5 131.2l-.3-.1-.2 .2 .1 .5h.4M169.9 124.3v1M169.9 130.8v1M169.9 124.8h.6M169.9 131.3h.6M170.5 124.3v1M170.5 130.8v1M171 124.7l.1-.1 .3 .1 .1 .4-.1 .2h-.3l-.1-.1zM171 131.2l.1-.1 .3 .1 .1 .4-.1 .2h-.3l-.1-.1z"/>
<path d="M171.9 124.3v.9l.1 .1M171.9 130.8v.9l.1 .1M172.4 125l.4-.1v-.2l-.3-.1-.1 .2v.5h.4M172.4 131.5l.4-.1v-.2l-.3-.1-.1 .2v.5h.4M174.8 125.9h.6M175.1 125.9v1M175.7 126.3h.4v.6M176.1 126.5h-.3l-.1 .1 .1 .3 .3-.1M177 126.3l-.2-.1-.2 .2 .1 .4h.3M177.3 126.2h.4M177.5 125.9v.8l.2 .2M178 125.9v.1"/>
<path d="M178 126.2v.7M178.5 125.9v.8l.2 .2M179 126.6l.5-.1-.1-.2-.3-.1-.1 .2v.4h.4M180.7 125.9l.4 .1 .1 .2-.2 .2a.27 .27 0 0 1 .2 .2 .27 .27 0 0 1-.2 .3h-.3zM180.7 126.4h.3M181.7 126.2v.6l.3 .1 .1-.1M182.1 126.2v.7M182.4 126.2h.4M182.6 125.9v.8l.2 .2M183 126.2h.4M183.1 125.9v.8l.3 .2M183.8 126.3l.2-.1 .2 .2v.3l-.2 .2-.2-.1-.1-.1z"/>
<path d="M184.6 126.3l.2-.1 .2 .1v.6M184.6 126.2v.7M187.3 125.5h.3M187.8 125.1h-.5v1M188.1 125.1h.1M188.1 125.4v.7M189.1 125.1v1M189.1 125.4h-.3l-.2 .2 .1 .4h.4M189.5 125.4l.1 .6 .2 .1 .2-.1M190 125.4v.7M190.9 125.4h-.3l-.2 .2 .1 .4h.4M191.3 125.1h.1"/>
<path d="M191.3 125.4v.7M191.8 125.4h.3l.1 .7M192.2 125.6l-.3 .1-.2 .1 .2 .3 .3-.1M192.7 125.1v.8l.1 .2"/>
</g>
<g fill="none" stroke="#848484" stroke-width=".13">
<path d="M42.4 18.8h14.4v.3h-.7v14.9h-13.1v-14.9h-.6zM117 18.2h6v1.8h1.5v1.2h1.5v11h-12v-11h1.5v-1.2h1.5zM172 16.8h9v13.5l-1 1h-8zM17.7 36.2h-3v11.4h3M17.7 32.8h20.6v18.2h-20.6zM19.4 28h.2M19.6 27.8h-.2v.4M19.8 27.8v.4M20 27.8a.2 .2 0 0 1 .2 .2 .2 .2 0 0 1-.2 .2zM20.4 28.2h.2M20.4 27.9l.1-.1v.4M32.8 26.9h7.3v3.3l-1 1h-6.3z"/>
<path d="M38.3 37.5h2.9v8.7h-2.9M38.9 23.9h1.3v2h-1.3zM39.3 25.2a.22 .22 0 0 0 .2 .4 .22 .22 0 0 0 .2-.4M39.5 24.8h.3M39.6 24.7v.4l-.3-.2M39.8 24.3v.3M39.8 24.4h-.5l.1 .2M40.9 23.9h1.3v2h-1.3zM41.3 25.2a.22 .22 0 0 0 .2 .4 .22 .22 0 0 0 .2-.4M41.4 24.8h.4M41.6 24.7v.4l-.4-.2M41.8 24.3v.3l-.4-.3-.1 .1v.2"/>
<path d="M43 22.5h13.1M49.4 39.3h1.2v2h-1.2zM49.9 39.7h.3M50 39.6v.3l-.3-.1M52.1 34l1-1 1 1M53.7 35.3h1.3v1.9h-1.3zM54.1 35.7a.24 .24 0 0 1 .3-.1 .24 .24 0 0 1 .2 .2 .24 .24 0 0 1-.3 .1 .24 .24 0 0 1-.2-.2zM54.1 36.6a.22 .22 0 0 0 .2 .3 .22 .22 0 0 0 .2-.3M54.2 36.1h.4M54.4 36.1v.3l-.3-.1M55.7 35.3h1.2v1.9h-1.2zM56 36.4v-.3l.2 .2 .1-.2h.2v.3"/>
<path d="M56.1 36.6a.22 .22 0 0 0 .2 .3 .22 .22 0 0 0 .2-.3M56.3 35.6v.3h-.2l-.1-.2 .1-.1h.3l.1 .3M57.1 31.7h1.2v2h-1.2zM57.4 32.6v.3h.3l-.1-.3h.3v.3M57.5 33.1a.22 .22 0 0 0 .2 .3 .22 .22 0 0 0 .2-.3M57.9 32.1v.3M57.9 32.3h-.5l.2 .1M62.8 28.2h10.9v11.6h-12v-10.5zM64.7 34h6M67.7 31v6M77.2 31.2h1.2v2h-1.2zM77.6 32.3a.22 .22 0 0 0 .2 .3 .22 .22 0 0 0 .2-.3"/>
<path d="M78 31.8v.3M78 31.9h-.5l.2 .2M80.9 40h1.3v2h-1.3zM81.2 36h5.6M82 34.3h4.8v1h-4.8zM82.4 28.3v2.8M82.9 36l1 2.3h4.2M83.6 32.2v3.8M84 21.2h1.5v-1.2h1.5v-1.8h6v1.8h1.5v1.2h1.5v11h-12zM84.5 36.8h4.9v1h-4.9zM86.3 24h2.3M87.5 37.4h6.7v3.8h-7.5v-2.8z"/>
<path d="M90.4 39v.4l.1 .1 .2-.1v-.4M90.6 36.8h4.9v1h-4.9zM90.9 39h.2l.1 .1-.3 .4h.3M91.4 24h2.3M93.2 34.3h4.8v1h-4.8zM93.2 36.2h5.6M96.3 32.2v4M97.1 36.2l-.9 2.1h-4.3M97.6 28.3v2.8M98.8 38.8h1.3v2.1h-1.3zM99.2 40h.1M99.7 39.2v.3"/>
<path d="M99.7 39.7v.3l-.4-.3-.1 .1v.2M99.7 39.4h-.5l.1 .1M101.2 37.9h2v1.3h-2zM101.2 39.9h2v1.2h-2zM101.7 38.3a.22 .22 0 0 0-.3 .2 .22 .22 0 0 0 .3 .2M101.9 38.7h.3M101.9 38.4l.1-.2v.5M102.3 38.2h.4l-.3 .5M107.7 38.8h2v1.3h-2zM108.4 39.2a.22 .22 0 0 0-.3 .2 .22 .22 0 0 0 .3 .2M108.6 39.7h.3M108.6 39.3l.2-.1v.5"/>
<path d="M109.1 39.2h.3l-.2 .2h.1v.2h-.2M111.2 36h5.6M112 34.3h4.8v1h-4.8zM112.4 28.3v2.8M112.9 36l1 2.3h4.2M113.6 32.2v3.8M114.5 36.8h4.9v1h-4.9zM116.3 24h2.3M120.6 36.8h4.9v1h-4.9zM121.4 24h2.3M123.2 34.3h4.8v1h-4.8zM123.2 36.2h5.6"/>
<path d="M126.3 32.2v4M127.1 36.2l-.9 2.1h-4.3M127.6 28.3v2.8M137.8 28.2h10.9v11.6h-12v-10.5zM139.7 34h6M142.7 31v6M150.6 22.7h1.2v2h-1.2zM151.2 24.1v-.2l-.2-.1-.1 .3h.5M151.4 23.8l-.2 .2M151.4 23.3v.3M151.4 23.5h-.5l.2 .1M153.8 28.7h1.2v2h-1.2z"/>
<path d="M154.2 29.8a.22 .22 0 0 0 .2 .3 .22 .22 0 0 0 .2-.3M154.3 29.3h-.1l-.1 .2 .1 .1 .2-.1M154.3 29.3h.1M154.3 29.3l.1 .1M154.4 29.4v.1M154.4 29.3v.1M154.4 29.3h.2v.2v.1l-.2-.1M154.4 29.3h.1M155.2 39.4h1.3v2h-1.3zM155.6 39.8v.2h.2v-.2M155.8 39.8h.1M155.8 39.8h.2"/>
<path d="M156 39.8h.1M156 39.8v.2M156.8 37h2v1.3h-2zM156.8 35.1h2v1.2h-2zM156.8 33.1h2v1.3h-2zM157.7 37.4a.22 .22 0 0 0-.3 .2 .22 .22 0 0 0 .3 .2M157.7 35.5a.22 .22 0 0 0-.3 .2 .22 .22 0 0 0 .3 .2M157.7 33.5a.22 .22 0 0 0-.3 .2 .22 .22 0 0 0 .3 .2M158.2 37.4h-.3v.2h.2l.1 .2h-.3M158.2 33.5l-.2 .1-.1 .3 .1 .1 .2-.1v-.2h-.3M158.2 35.6l-.2 .1-.1-.2 .2-.1 .1 .1v.3l-.2 .1M160.2 37.1h2v1.2h-2z"/>
<path d="M160.2 35.1h2v1.2h-2zM160.2 33.1h2v1.3h-2zM160.9 35.5a.22 .22 0 0 0-.3 .2 .22 .22 0 0 0 .3 .2M161.1 35.9h.3M161.1 35.6l.1-.2v.5M161.1 37.5a.22 .22 0 0 0-.3 .2 .22 .22 0 0 0 .3 .2M161.1 33.5a.22 .22 0 0 0-.3 .2 .22 .22 0 0 0 .3 .2M161.3 37.4h.3l-.2 .5M161.3 33.5h.3l-.1 .1 .1 .1v.2h-.3M161.6 35.5l.1-.1a.23 .23 0 0 1 .2 .3 .23 .23 0 0 1-.3 .2zM162.6 39.7h1.2v2h-1.2zM163.5 23h1.3v2h-1.3z"/>
<path d="M163.8 26.1h4.5v3.2h-4.5zM163.8 30.1h2v1.3h-2zM163.9 24.1a.22 .22 0 0 0 .2 .3 .22 .22 0 0 0 .2-.3M164.1 23.7h.3M164.2 23.6v.3l-.3-.1M164.7 30.5a.22 .22 0 0 0-.3 .2 .22 .22 0 0 0 .3 .2M164.9 30.5h.2l.1 .1-.3 .4h.3M170.4 20.7h9.8v9.5l-.5 .5h-9.3zM171.7 37.6h-2.9v8.7h2.9M171.7 32.8h20.6v18.2h-20.6zM173.3 20.7v10M174.5 22.2l2.1 2.1"/>
<path d="M174.5 27.2l2.1 2.1M174.7 22.1l2.1 2.1M174.7 27.1l2.1 2.1M178.2 20.7v10M179.7 20.7v10M189.4 28h.2M189.6 27.8h-.2v.4M189.8 27.8v.4M190 27.8a.2 .2 0 0 1 .2 .2 .2 .2 0 0 1-.2 .2zM190.4 27.8h.1l.1 .1-.3 .3h.3M192.3 36.2h3v11.4h-3M17.3 52.7h4.2l.8 .8v6.7h-5z"/>
<path d="M24.5 55.7h1.1v2.3l-.3 .2h-.8zM24.7 57.3h.5l.1 .1-.1 .2h-.5M25.3 56.2v.4M25.3 56.8v.3M25.3 56.9h-.6l.2 .2M25.3 56.4h-.6l.2 .2M26.8 59h1.9v1.3h-1.9zM27.4 59.4a.22 .22 0 0 0-.3 .2 .22 .22 0 0 0 .3 .2M27.9 59.4h-.3v.2h.3v.2h-.3M28.1 59.4h.1a.23 .23 0 0 1 .2 .2 .23 .23 0 0 1-.3 .2zM41.9 58.6h2v1.2h-2zM42.1 46.5h1.2v2h-1.2z"/>
<path d="M42.3 59.2h.2v-.2l-.2-.1v.5M42.4 59.2l.1 .2M42.7 47.8v-.2h-.2l-.1 .2h.5M42.7 59l.2-.1 .1 .2-.3 .3h.3M42.9 47.1v.3l-.3-.3-.2 .1 .1 .2M42.9 47.5l-.2 .2M43.2 59l.2-.1 .1 .2-.3 .3h.3M44.9 59.1h1.2v2h-1.2zM45.2 59.8v-.3l.2 .2 .1-.2h.2v.3M45.7 60v.3l-.3-.3-.2 .1 .1 .2M46.4 42h1.2v2h-1.2zM46.4 46.7h1.2v2h-1.2z"/>
<path d="M46.8 43.3a.22 .22 0 0 0 .2 .3 .22 .22 0 0 0 .2-.3M46.8 48.1a.22 .22 0 0 0 .2 .3 .22 .22 0 0 0 .2-.3M46.9 42.9h.3M46.9 47.6h.3M47 42.4v-.1l.2 .1-.1 .2-.1-.1M47 47.1v.2l-.2 .1-.1-.2 .1-.1h.3l.1 .2M47 42.4l-.1-.1-.2 .1 .1 .2 .2-.1M47 42.4v.1M47.1 42.8v.3l-.4-.1M47.1 47.6v.3l-.4-.1M47.9 51.7h1.2v2h-1.2zM48.2 52.1v.1l.2 .1h.3v-.2"/>
<path d="M48.4 52.1l.1 .2M48.4 52.1h.3M48.4 52.1h.1M48.5 53.3l-.1-.3h-.1l-.1 .3h.5M48.7 52.1h.1M48.7 52.5v.3l-.4-.3-.1 .1 .1 .2M48.7 53l-.2 .2M49.2 43h5l1 1v5h-6zM49.8 51.7h1.2v2h-1.2zM49.8 40.6a.22 .22 0 0 0 .2 .3 .22 .22 0 0 0 .2-.3M49.9 40.2h.3M50 40.1v.3l-.3-.1"/>
<path d="M50.1 52.1v.2h.2v-.2M50.3 52.1h.3v.2M50.3 52.1h.1M50.4 53.3l-.1-.3h-.1l-.1 .3h.5M50.5 59.7h2v1.2h-2zM50.6 53l-.2 .2M50.6 52.5v.3l-.3-.3-.2 .1 .1 .2M51.7 51.7h1.2v2h-1.2zM52.2 53h-.2v.3h.5M52.2 52.1l-.1-.1-.1 .1 .1 .2 .1-.1M52.2 52.1l.1-.1 .2 .1-.1 .2-.2-.1M52.2 53h.1"/>
<path d="M52.2 52.1v.1M52.2 53l.1 .3M52.5 53l-.2 .2M52.5 52.5v.3l-.3-.3-.2 .1 .1 .2M54.4 50.4h1.3v2h-1.3zM54.6 55.6h3v2.3l-.7 .7h-2.3zM54.8 51.8a.22 .22 0 0 0 .2 .3 .22 .22 0 0 0 .2-.3M54.9 51.3h.4M55.1 51.3v.3l-.4-.1M55.3 51l-.5-.2v.3M55.7 56.8v.5l.1 .1 .2-.1v-.5M56.4 57l-.1 .2 .1 .2 .2-.1-.1-.3"/>
<path d="M56.4 57h.1M56.5 57h.1M56.6 57l-.1-.2h-.1l-.1 .1 .1 .1M56.6 57h-.1M57.2 43.4h2v1.2h-2zM57.9 43.8a.22 .22 0 0 0-.3 .2 .22 .22 0 0 0 .3 .2M58.2 43.7l-.1 .4h.3M58.3 43.9v.3M58.8 43.7h-.2v.3l.2-.1v.3h-.2M59.7 47.4h2v1.2h-2zM60.1 48l.2-.1 .1-.1-.3-.1v.5M60.2 48l.2 .2"/>
<path d="M60.3 43.6h1.3v2h-1.3zM60.6 47.8l.2-.1 .1 .1-.4 .4h.4M60.9 44h.3M61 45.2l-.1-.2h-.2v.2h.5M61 47.7h.4l-.3 .5M61 44v.3l-.3-.1M61.2 44.9l-.2 .2M61.2 44.5v.3l-.4-.3-.1 .1v.2M63.3 45.4h1.3v2h-1.3zM63.3 48.8h1.3v2h-1.3zM63.7 49.2v.2h.2v-.2h.2v.2M63.7 46.7a.22 .22 0 0 0 .2 .3 .22 .22 0 0 0 .2-.3"/>
<path d="M63.7 50.1a.22 .22 0 0 0 .2 .3 .22 .22 0 0 0 .2-.3M64.2 45.9h-.5l.1 .1M64.2 46.3h-.5l.1 .2M64.2 45.7v.3M64.2 46.2v.3M64.2 49.6v.3l-.4-.3-.1 .1v.2M66.2 45.6h2.4v5h-3.2v-4.2zM68.6 52.3h2v1.3h-2zM69.3 52.7a.22 .22 0 0 0-.3 .2 .22 .22 0 0 0 .3 .2M69.5 52.7h.3l-.2 .2h.1M69.5 53.1h.2M69.7 52.9h.1"/>
<path d="M69.8 52.9v.2M69.8 53.1h-.1M70 53.1h.1M70.1 52.9h.1M70.1 52.9l-.1-.1 .1-.1 .2 .1-.1 .1M70.1 52.9l-.1 .2M70.2 52.9v.2h-.2M71.6 51.1h2.9v1.6h-2.5l-.4-.4zM72.4 47.1h1.2v2h-1.2zM72.7 48v.2M72.7 48.2h.1M72.7 47.7h.1"/>
<path d="M72.8 48h-.1M72.9 52.1l.4 .1-.1 .2h-.3M72.9 51.4a.19 .19 0 0 1 .2-.1 .19 .19 0 0 1 .2 .2l-.1 .1a.19 .19 0 0 1-.2 0 .19 .19 0 0 1-.1-.2zM72.9 47.5l.1 .2h-.2M73 48.7v-.2h-.2l-.1 .2h.5M73.2 47.6l-.4-.1-.1 .2M73.2 47.6h.1M73.2 47.6v.1M73.2 48.4l-.2 .2M73.2 48v.3l-.3-.3h-.1M73.3 51.7v.3M73.3 51.9h-.4l.1 .1"/>
<path d="M79.4 40.4h.8v1.6h-.8zM79.7 41h.3M79.9 40.9v.2h-.3M80 41.3v.2h-.4M80.2 43h1.6v.8h-1.6zM80.8 43.2v.4h.2M81.1 43.6h.2M81.1 43.3l.1-.1v.4M81.3 40.9v-.3l.2 .2v-.2h.2v.3M81.5 41.4v-.3h-.2v.3h.5M81.8 41.1l-.3 .1M82.8 40.5h1.8v2.8h-1.8z"/>
<path d="M83.1 41.6h1.1M83.7 41.6l.4 .6h-.8zM83.7 41.2v.4M83.7 42.2v.5M89.2 43.2h1.6v.8h-1.6zM89.2 41.8h1.6v.8h-1.6zM89.8 42v.4h.1M89.8 43.4v.4h.1M90 42h.3l-.1 .1h.1v.2h-.3M90.1 43.5l.1-.1 .1 .1-.3 .3h.3M90.3 52.2h2.5v3h-2.5zM92.2 41.8h2v1.2h-2z"/>
<path d="M92.2 43.7h2v1.2h-2zM92.8 44.3h.3v-.2l-.3-.1v.5M92.8 42.4h.3v-.2l-.3-.1v.5M93 42.4l.1 .2M93 44.3l.1 .2M93.4 42.1l-.1 .4h.3M93.6 42.3v.3M93.6 44h-.3v.3l.3-.1v.3h-.3M93.9 53.2h2v1.3h-2zM93.9 49.3h2v1.2h-2zM93.9 55.2h2v1.3h-2zM93.9 51.2h2v1.3h-2z"/>
<path d="M94.6 53.6a.22 .22 0 0 0-.3 .2 .22 .22 0 0 0 .3 .2M94.6 51.8h.2v-.2h-.2v.5M94.6 55.8h.2v-.2h-.2v.5M94.6 49.7a.22 .22 0 0 0-.3 .2 .22 .22 0 0 0 .3 .2M94.7 55.8l.2 .3M94.7 51.8l.2 .3M94.8 54.1h.2M94.8 53.7l.1-.1v.5M94.8 50.1h.3M94.8 49.8l.1-.2v.5M95.1 51.8l-.1-.1 .1-.1 .2 .1-.1 .1M95.1 51.8l-.1 .1 .1 .2 .2-.1-.1-.2"/>
<path d="M95.1 51.8h.1M95.3 49.7l.1-.1 .1 .1M95.3 49.7l.1 .1M95.3 49.7h.1M95.3 55.8l-.2 .1v-.3h.1l.1 .1v.3l-.2 .1M95.4 49.8l-.1 .1 .1 .2 .1-.1-.1-.2M95.4 49.8h.1M95.5 53.6h-.2l-.1 .2h.3v.2h-.3M95.5 49.8h-.1M95.5 49.8h.1M95.5 49.7h.1M95.5 49.7v.1"/>
<path d="M96.9 49.8h5.2v5.3h-4.2l-1-1zM98.4 43.8h2v1.3h-2zM98.4 45.7h2v1.3h-2zM98.8 44.4h.2l.1-.2h-.3v.5M98.9 44.4l.2 .3M99 46.3h.3v-.2h-.3v.5M99.1 46.3l.2 .3M99.2 40.2a.22 .22 0 0 0 .2 .3 .22 .22 0 0 0 .2-.3M99.3 44.7h.3M99.3 44.3l.1-.1v.5M99.7 41.9h2v1.3h-2zM99.7 46.1l-.2 .1v.3l.1 .1 .2-.1-.1-.2-.2 .1"/>
<path d="M99.8 44.2h.1a.23 .23 0 0 1 .1 .2 .23 .23 0 0 1-.2 .2zM100.4 42.3a.22 .22 0 0 0-.3 .2 .22 .22 0 0 0 .3 .2M100.6 42.8h.3M100.6 42.4l.1-.1v.5M101.1 42.3h.2l.1 .1-.3 .4h.3M101.9 40.3a.22 .22 0 0 0-.3 .2 .22 .22 0 0 0 .3 .2M102.1 40.7h.3M102.1 40.4l.1-.2v.5M102.7 40.2l-.2 .4h.4M102.7 51.7h1.3v2h-1.3zM102.8 40.4v.3M103.1 53a.22 .22 0 0 0 .2 .3 .22 .22 0 0 0 .2-.3"/>
<path d="M103.3 52.1l.1 .2h-.3v-.1l.1-.1h.3l.1 .2M103.6 52.5v.3M103.6 52.7h-.5l.1 .1M103.9 42.1h7v7h-6l-1-1zM108 51.8h1.3v2h-1.3zM108.4 53.1a.23 .23 0 0 0 .2 .3 .23 .23 0 0 0 .2-.3M108.8 53.1h.1M108.8 52.2a.24 .24 0 0 0-.3-.1 .24 .24 0 0 0-.1 .3h.4M108.8 52.2h.1M108.8 52.2v.2M108.8 52.4h.1M108.9 52.6v.4l-.4-.4-.1 .1v.2"/>
<path d="M110.9 54.2h2v1.2h-2zM111.3 54.8h.2v-.2l-.2-.1v.5M111.4 54.8l.2 .2M111.8 54.6l.1-.1 .1 .2-.3 .3h.3M112.2 50.8h2v1.2h-2zM112.2 55h.3M112.2 54.7l.2-.2v.5M112.6 46.7h1.2v2h-1.2zM112.9 51.2a.22 .22 0 0 0-.3 .2 .22 .22 0 0 0 .3 .2M112.9 47.1l.1 .2M113 48a.23 .23 0 0 0 .2 .3 .23 .23 0 0 0 .2-.3M113 47.3h.1"/>
<path d="M113 48h.1M113.1 51.2l.2-.1 .1 .2-.4 .3h.4M113.4 47.1h-.3l.1 .3M113.4 48h.1M113.4 47.1h.1M113.4 47.1l-.1 .3-.3-.1M113.4 47.7h-.5l.2 .1M113.4 47.5v.3M113.5 51.2l.2-.1 .1 .2-.3 .3h.3M114.4 53.8a.31 .31 0 0 1 .3 .3 .31 .31 0 0 1-.3 .4M114.4 52.8h3.4v2.7h-3.4zM114.8 43.6h2v1.3h-2z"/>
<path d="M115.4 44a.22 .22 0 0 0-.3 .2 .22 .22 0 0 0 .3 .2M115.6 44h.2l.1 .1-.3 .4h.3M115.7 50.8h2v1.2h-2zM115.7 57.1h2v.9l-.3 .3h-1.7zM116.1 44h.3l-.2 .2h.2v.2h-.3M116.1 51.4h.2l.1-.2-.3-.1v.5M116.2 51.4l.2 .2M116.3 57.4a.25 .25 0 0 1 .3 .3 .25 .25 0 0 1-.3 .2zM116.6 51.6h.3M116.6 51.3l.1-.2v.5M116.8 47.7h1.2v2h-1.2zM116.8 57.5l.2-.1 .1 .1-.3 .4h.3"/>
<path d="M117 51.6h.3M117 51.3l.2-.2v.5M117.1 48.1l.1 .2 .1 .1 .3-.1v-.2M117.2 49a.23 .23 0 0 0 .2 .3 .23 .23 0 0 0 .2-.3M117.3 48.1l.1 .3M117.4 48.1h.2M117.4 48.1h-.1M117.6 49h.1M117.6 48.1h.1M117.6 48.5v.4l-.3-.4-.2 .1 .1 .2M120.8 48.8h2v1.2h-2zM121 50.7h3.7v5.7l-1 1h-2.7z"/>
<path d="M121.5 49.2a.22 .22 0 0 0-.3 .2 .22 .22 0 0 0 .3 .2M121.7 49.2l.2-.1 .1 .2-.3 .3h.3M122.3 49.1l-.1 .4h.3M122.4 49.3v.3M122.5 54.2h.6l.2 .2v.1l-.2 .2h-.6M122.5 53.4v.4l.3 .1v-.4l.4-.1 .1 .2-.1 .3M122.8 43.4h2.5v3h-2.5zM124.2 48.8h2v1.3h-2zM124.9 49.2a.22 .22 0 0 0-.3 .2 .22 .22 0 0 0 .3 .2M125.1 49.2h.2l.1 .1-.3 .4h.3M125.6 49.2h.3l-.2 .5M128 43.2h7.7v2.5h-7l-.7-.6z"/>
<path d="M133 47.8h5.1v10h-5.1zM134.6 52.6h.5v.5h-.5zM134.6 50.6h.5v.4h-.5zM134.6 54.5h.5v.5h-.5zM136.5 42.8h1.2v2h-1.2zM137.1 44.2v-.3h-.2l-.1 .3h.5M137.3 43.9l-.2 .1M137.3 43.6l-.5-.2v.3M138.1 54.3l-.8 .5 .8 .5M138.8 45.5h2v1.3h-2zM139.1 42.8l.3-.3h1v2h-1.3zM139.3 46.1l.1 .3"/>
<path d="M139.4 45.9h-.2v.5M139.4 45.9h.1M139.4 45.9v.2h-.2M139.5 43.6h.4l.1 .1-.1 .2h-.4M139.6 45.9h.2l.1 .1-.3 .4h.3M140 43.1v.3M140 43.2h-.5l.1 .2M140.2 45.9a.24 .24 0 0 0-.1 .3 .24 .24 0 0 0 .2 .1l.1-.4M140.2 45.9h.1M140.3 45.9h.1M142 47h5v11.9h-5zM142.3 43.5h1.2v2h-1.2z"/>
<path d="M142.6 44.4v.2h.3l-.1-.2h.3v.2M142.7 44.8a.22 .22 0 0 0 .2 .3 .22 .22 0 0 0 .2-.3M143.1 43.9v.3l-.3-.3-.2 .1 .1 .2M143.5 49.7h.5v.5h-.5zM143.5 51.7h.5v.5h-.5zM143.5 53.7h.5v.5h-.5zM143.5 55.7h.5v.5h-.5zM145.2 43h1.6v2.5l-.4 .5h-1.2zM145.5 44.3l.1 .4 .1-.1v-.3M145.9 44.7h.2M145.9 44.4l.1-.1v.4M146.3 44.3h.1l.1 .1-.2 .3h.2"/>
<path d="M147 55.5l-.7 .5 .7 .5M148.7 42.3h2.1v1.3h-2.1zM148.9 44.6h1.9v1.3h-1.9zM149.1 42.9h.3v-.2h-.3v.5M149.2 45.2h.3v-.2h-.3v.5M149.3 42.9l.1 .3M149.4 45.2l.1 .3M149.6 43.2h.3M149.6 42.8l.2-.1v.5M149.7 45.5h.3M149.7 45.1l.2-.1v.5M150.3 43.2h-.2"/>
<path d="M150.3 45.2l-.1-.1 .1-.1 .2 .1-.1 .1M150.3 45.2l-.1 .1 .1 .2 .2-.1-.1-.2M150.3 45.2h.1M150.3 43.1v.1M150.4 42.9l-.3 .1v-.3h.2l.1 .1-.1 .3M151.1 55.3h7.3v3.3l-1 1h-6.3zM153.3 46.1h1.2v2h-1.2zM153.9 47.7v-.2h-.2l-.1 .2h.5M154.1 47.1h-.5l.2 .2M154.1 46.5v.3l-.3-.3-.2 .1 .1 .2M154.1 47v.3M154.1 47.5l-.2 .1"/>
<path d="M155.2 42.8h1.3v2h-1.3zM155.2 46.2h1.3v2h-1.3zM155.6 43.2v.2h.2v-.2h.2v.2M155.6 40.5v-.3l.2 .2v-.2h.2v.3M155.6 47.5a.22 .22 0 0 0 .2 .3 .22 .22 0 0 0 .2-.3M155.6 40.7a.23 .23 0 0 0 .2 .3 .23 .23 0 0 0 .2-.3M155.8 46.5l.1 .3h-.3v-.2l.1-.1 .2 .1 .2 .2M155.8 44.4v-.3h-.2v.3h.5M156 40.7h.1M156 52.2h1.3v2h-1.3zM156.1 43.6v.3M156.1 44.1l-.3 .2"/>
<path d="M156.1 43.8h-.5l.1 .1M156.1 47v.3l-.4-.3-.1 .1v.2M156.4 53.5a.22 .22 0 0 0 .2 .4 .22 .22 0 0 0 .2-.4M156.6 52.7l.1-.1 .2 .1-.1 .2-.2-.1M156.6 52.7l-.1-.1-.1 .1 .1 .2 .1-.1M156.6 52.7v.1M156.9 53.1v.3l-.4-.3-.1 .1v.2M157.1 40.4h3.9l1 1v2.9h-4.9zM158 52.2h1.3v2h-1.3zM158 48.8h1.3v2h-1.3zM158.4 53.4v-.3l.1 .1 .1-.1h.2v.3M158.4 52.6v.2"/>
<path d="M158.4 52.8h.1M158.4 52.8l.4 .1 .1-.2-.1-.1-.3 .1 .1 .2M158.4 53.6h.1M158.6 49.2h.3M158.6 46.5h2v1.2h-2zM158.7 50.4l-.1-.2-.2-.1v.3h.5M158.7 49.1v.4l-.3-.2M158.8 53.6a.23 .23 0 0 1-.2 .3 .23 .23 0 0 1-.2-.3M158.9 50.1l-.2 .2M158.9 49.6v.3M158.9 49.8h-.5l.1 .1M159.3 46.9a.22 .22 0 0 0-.3 .2 .22 .22 0 0 0 .3 .2"/>
<path d="M159.5 46.8h.3l-.2 .2 .2 .1v.2M159.5 47.3h.1M159.5 47.3h.2M159.8 47.3h-.1M160 52.2h1.2v2h-1.2zM160 48.8h1.3v2h-1.3zM160.1 46.8l-.1 .4h.3M160.2 47v.3M160.3 53.4v-.3l.2 .1 .1-.1h.2v.3M160.4 53.5a.22 .22 0 0 0 .2 .4 .22 .22 0 0 0 .2-.4M160.4 50.1a.22 .22 0 0 0 .2 .4 .25 .25 0 0 0 .3-.4M160.6 49.7v.1l-.2-.1v.3"/>
<path d="M160.6 49.7h.3M160.6 49.7h.1M160.8 52.6v.3l-.3-.3-.2 .1 .1 .2M160.9 49.7h.1M160.9 49.7v.3M160.9 50h.1M160.9 49.3h-.5l.1 .2M160.9 49.2v.3M161.9 47.1h6v6h-6zM162.6 43.1h1.2v2h-1.2zM162.9 40.9v-.3l.2 .1 .1-.1h.2v.3M162.9 43.8v-.3l.2 .2 .1-.2h.2v.3"/>
<path d="M163 40.1a.24 .24 0 0 1 .3 0 .24 .24 0 0 1 .1 .2 .24 .24 0 0 1-.3 .1 .24 .24 0 0 1-.1-.2zM163 41a.22 .22 0 0 0 .2 .4 .22 .22 0 0 0 .2-.4M163.2 44.7v-.2h-.2l-.1 .2h.5M163.4 44.1h-.5l.2 .2M163.4 44.5l-.2 .1M163.4 44v.3M168.5 52.7h1.3v2h-1.3zM168.9 53.9v-.3l.1 .1 .1-.1h.2v.3M168.9 54.1a.23 .23 0 0 0 .2 .3 .23 .23 0 0 0 .2-.3M169.3 54.1h.1M169.4 53.3l-.5-.2v.3M17.7 77.2h-3v11.4h3"/>
<path d="M17.7 73.8h20.6v18.2h-20.6zM24 61h12v12h-12zM38.3 78.5h2.9v8.7h-2.9M45.3 60.5l-.1 .2h.5M45.3 60.5h.1M45.3 60.5h.2v.2M45.7 60.5l-.2 .1M51.2 60.1a.22 .22 0 0 0-.3 .2 .22 .22 0 0 0 .3 .2M51.5 60l-.1 .4h.3M51.6 60.2v.3M51.9 60.3l.1-.1 .2 .1-.1 .2h-.2M51.9 60.5h.1"/>
<path d="M52.1 60l-.2 .1v.4M99 61h12v12h-12zM100 77.2l.3-.3h.9v2h-1.2zM100.3 77.9h.4l.1 .1-.1 .2h-.4M100.8 77.6l-.5-.2v.4M102.6 76.8h1.2v2h-1.2zM103.2 78.4v-.3h-.2l-.1 .3h.5M103.4 78.1l-.2 .1M103.4 77.3l-.5-.2v.3M103.4 77.6v.3M103.4 77.7h-.5l.2 .2M104.5 76.8h.9l.3 .3v1.7h-1.2z"/>
<path d="M104.9 77.9a.26 .26 0 0 1 .3 0 .26 .26 0 0 1 .1 .2h-.5zM105.3 77.6l-.5-.3v.4M106.5 76.8h.9l.3 .3v1.7h-1.2zM106.8 77.4l.1 .2h.3h.1v-.2h-.3l.1 .2M106.8 77.9a.27 .27 0 0 1 .3-.1 .27 .27 0 0 1 .2 .3h-.5zM108.4 76.7h1.3v2h-1.3zM108.8 77.1v.2l.2 .1M109 77.1h.2v.2h-.2zM109 77.3l.1 .1M109 78.3v-.2l-.2-.1v.3h.5M109.3 78l-.3 .2M109.3 77.5v.3"/>
<path d="M109.3 77.7h-.5l.1 .1M171.7 73.8h20.6v18.2h-20.6zM171.7 78.5h-2.9v8.7h2.9M174 61h12v12h-12zM192.3 77.2h3v11.4h-3M17.7 97.4h-3v11.4h3M17.7 94h20.6v18.2h-20.6zM38.3 98.7h2.9v8.7h-2.9M100.9 80h7l.6 .7v1.9h-7.6zM171.7 98.8h-2.9v8.7h2.9M171.7 94h20.6v18.2h-20.6zM192.3 97.4h3v11.4h-3"/>
<path d="M24 113h12v12h-12zM99 113h12v12h-12zM174 113h12v12h-12zM19.4 123h.2M19.6 122.8h-.2v.4M19.8 122.8v.4M20 122.8a.2 .2 0 0 1 .2 .2 .2 .2 0 0 1-.2 .2zM20.3 122.8h.3l-.1 .1M20.3 123.1l.1 .1M20.4 123.2h.1M20.5 122.9l.1 .1M20.6 123v.1"/>
<path d="M20.6 123.1l-.1 .1M189.4 123h.2M189.6 122.8h-.2v.4M189.8 122.8v.4M190 122.8a.2 .2 0 0 1 .2 .2 .2 .2 0 0 1-.2 .2zM190.5 122.8l-.1 .2h.2M190.5 122.9v.3"/>
<circle cx="20" cy="28" r="1.5"/>
<circle cx="67.7" cy="34" r="3"/>
<circle cx="142.7" cy="34" r="3"/>
<circle cx="175.6" cy="23.2" r="1.5"/>
<circle cx="175.6" cy="28.2" r="1.5"/>
<circle cx="190" cy="28" r="1.5"/>
<circle cx="91.5" cy="53.7" r=".75"/>
<circle cx="115" cy="54.4" r=".08"/>
<circle cx="124" cy="44.9" r=".75"/>
<circle cx="20" cy="123" r="1.5"/>
<circle cx="190" cy="123" r="1.5"/>
</g>
<path d="M84.7 15.6a.85 .85 0 0 1 .9 .5 .85 .85 0 0 1-.3 1.1h-.6zM86.3 15.6v1.6M88 15.6v1.6l-1-1.6v1.6M89.5 15.6h-.8v.8l.2-.2 .5 .1 .2 .2-.1 .6-.2 .1h-.4l-.2-.1M114.7 15.6a.85 .85 0 0 1 .9 .5 .85 .85 0 0 1-.3 1.1h-.6zM116.3 15.6v1.6M118 15.6v1.6l-1-1.6v1.6M119.5 15.6h-.8v.8l.2-.2 .5 .1 .2 .2-.1 .6-.2 .1h-.4l-.2-.1" fill="none" stroke="#848484" stroke-width=".16"/>
<path d="M157.2 26.3h5.3v3.8h-5.3z" fill="none" stroke="#848484" stroke-width=".2"/>
<g fill="#848484" stroke="#848484" stroke-width=".13">
<path d="M157.7 25.1h.5v1.1h-.5z" fill-rule="evenodd"/>
<path d="M157.7 30.2h.5v1.1h-.5z" fill-rule="evenodd"/>
<path d="M159 25.1h.5v1.1h-.5z" fill-rule="evenodd"/>
<path d="M159 30.2h.5v1.1h-.5z" fill-rule="evenodd"/>
<path d="M160.3 25.1h.4v1.1h-.4z" fill-rule="evenodd"/>
<path d="M160.3 30.2h.4v1.1h-.4z" fill-rule="evenodd"/>
<path d="M161.5 25.1h.5v1.1h-.5z" fill-rule="evenodd"/>
<path d="M161.5 30.2h.5v1.1h-.5z" fill-rule="evenodd"/>
</g>
<path d="M22.3 20.3l.3-.2 .4-.1h64.8v1l.2 .3 3.8 .1 .3-.2 .1-1.2h7.8a5 5 0 0 0 5 5 5 5 0 0 0 5-5h7.8l.1 1.2 .3 .2 3.8-.1 .2-.3v-1h64.8a1 1 0 0 1 1 1v2a3 3 0 0 0 3 3 1 1 0 0 1 1 1v97a1 1 0 0 1-1 1 3 3 0 0 0-3 3v2a1 1 0 0 1-1 1h-77a5 5 0 0 0-5-5 5 5 0 0 0-5 5h-77a1 1 0 0 1-1-1v-2a3 3 0 0 0-3-3 1 1 0 0 1-1-1v-97a1 1 0 0 1 1-1 3 3 0 0 0 3-3v-2l.1-.4z" fill="none" stroke="#c2c200" stroke-width=".13"/>
<g fill="none" stroke="#c2c2c2" stroke-width=".13">
<path d="M15.4 19.5h179.2v112.3h-179.2zM25 20h7.1M31.5 20v3M31.5 20l.6 1.1M31.5 20l-.6 1.1M25 23h7.1M30.9 21.9l.6 1.1M32.1 21.9l-.6 1.1M17.8 52.5v8M18.2 55.7h.4v.1l-.2 .1v-.2M18.2 56.9l.2 .1 .1-.1h.1l.1 .3h-.5zM18.2 57.4a.22 .22 0 0 0 .2 .3 .22 .22 0 0 0 .2-.3"/>
<path d="M18.3 55.2h.4l.1 .2M18.4 55.2v.2h.2v-.2M18.4 57.9h-.2v.3h.5M18.4 57.9h.1M18.4 57.9v.3M18.4 57v.2M18.6 54.8v.2h-.2v-.2v-.1l.1 .3M18.6 56.1v.2h-.2v-.2l.1 .2M119 55.9v7.1M119 56.5h52.5M119 56.5l1.1 .6M120.1 55.9l-1.1 .6"/>
<path d="M166.9 55.9l2.2 1.2M168 55.9v7.1M169.1 55.9l-2.2 1.2M170.4 55.9l1.1 .6M171.5 55.9v7.1M171.5 56.5l-1.1 .6M102.4 60h16.1M103 60v65M103 60l.6 1.1M103 60l-.6 1.1M106.9 63.5h11.6M107.5 63.5v58"/>
<path d="M107.5 63.5l.6 1.1M107.5 63.5l-.6 1.1M111.5 63.5v29M111.5 63.5l.6 1.1M111.5 63.5l-.6 1.1M110.9 92.5h7.6M110.9 91.4l.6 1.1M112.1 91.4l-.6 1.1M14.6 106.1v42.3M195.4 106.1v42.3M102.4 125h16.1M102.4 123.9l.6 1.1"/>
<path d="M103.6 123.9l-.6 1.1M106.9 121.5h11.6M106.9 120.4l.6 1.1M108.1 120.4l-.6 1.1M14.6 147.8h180.8M14.6 147.8l1.1 .6M15.7 147.2l-1.1 .6M194.3 147.2l1.1 .6M195.4 147.8l-1.1 .6"/>
<circle cx="119" cy="92.5" r=".25"/>
</g>
<g fill="none" stroke="#c2c2c2" stroke-width=".15">
<path d="M25 13.9v8.6M25 14.5l1.1 .6M26.1 13.9l-1.1 .6M80 16.9v2.6M80 17.5h50M80 17.5l1.1 .6M81.1 16.9l-1.1 .6M102.1 13.1l.2-.3v1M102.1 13.8h.5M103 15.8h-.4l-.1 .5 .2-.1h.3l.1 .2-.1 .3-.1 .1-.4-.1M103.5 12.8l-.3 .1a.67 .67 0 0 0 0 .9l.3-.1 .1-.3-.2-.2h-.2l-.2 .2M103.6 15.9l.1-.1a.53 .53 0 0 1 .4 .5 .53 .53 0 0 1-.4 .5l-.1-.1-.1-.3z"/>
<path d="M104.1 12.9l.1-.1a.53 .53 0 0 1 .3 .5 .53 .53 0 0 1-.3 .5l-.1-.1-.1-.3zM105.2 16.1v.7M105.2 16.2l.3-.1 .2 .2M105.7 16.3l.1-.2 .2 .1 .1 .6M105.7 16.3v.5M105.7 13.1v.7M105.7 13.2l.3-.1 .1 .2M106.1 13.3l.2-.2 .2 .1 .1 .6M106.1 13.3v.5M106.6 16.2l.3-.1 .1 .2M106.6 16.1v.7M107 16.3l.1-.2 .3 .1v.6"/>
<path d="M107 16.3v.5M107.1 13.1v.7M107.1 13.2l.2-.1 .2 .2M107.5 13.3l.1-.2 .3 .1v.6M107.5 13.3v.5M128.9 16.9l1.1 .6M130 16.9v2.6M130 17.5l-1.1 .6M183.9 13.9l1.1 .6M185 13.9v8.6M185 14.5h-160M185 14.5l-1.1 .6"/>
<path d="M185 14.6h7M185 14.6l1.1 .6M186.1 14l-1.1 .6M186.5 12.9h.6l-.4 1M187.5 20h14.3M188.3 13.2v.7M188.3 13.3l.3-.1 .1 .2M188.7 13.4v.5M188.7 13.4l.1-.2 .3 .1v.6M189.6 13.3l.3-.1 .1 .2M189.6 13.2v.7M190 13.4l.2-.2 .2 .1 .1 .6"/>
<path d="M190 13.4v.5M190.9 14l1.1 .6M192 14.6l-1.1 .6M192 14v8.5M201.2 20v111M201.2 20l.6 1.1M201.2 20l-.6 1.1M33.1 24.5v-.6l.4 .4v-.3h.5l.1 .1-.1 .4M33.4 22.7h.7M33.4 21.4h.7M33.5 22.3l-.1 .1 .1 .3M33.5 21l-.1 .1 .1 .3"/>
<path d="M33.5 22.3h.6M33.5 21h.6M34.1 20.5l-.6 .1-.1 .2 .1 .2M34.1 21.9h-.6l-.1 .3 .1 .1M86.6 20.4h.3l.1 .1v.5h-.4l-.1-.2 .5-.1M87.4 20.4h.3l.2 .2-.1 .4h-.4M87.9 20.1h-.3l-.2 .2v.8M88.4 20.4h.2l.2 .2-.1 .4h-.3M88.4 20.4v1M89.3 20.4h.2l.2 .1-.1 .5h-.3l-.1-.2 .5-.1M90.9 20.4h.5v1l-.5-.1v-.2l.2-.2-.3-.2zM91.1 20.9h.3"/>
<path d="M91.8 20.5a.47 .47 0 0 1 .7 .3 .47 .47 0 0 1-.5 .6l-.2-.1M93.4 20.4v1h-.4l-.1-.1-.1-.2 .1-.2h.5M116.6 20.4h.3l.1 .1v.5h-.4l-.1-.2 .5-.1M117.5 20.4h.2l.2 .2-.1 .4h-.3M117.9 20.1h-.3l-.1 .2v.8M118.4 20.4h.2l.2 .2-.1 .4h-.3M118.4 20.4v1M119.3 20.4h.2l.2 .1-.1 .5h-.3l-.1-.2 .5-.1M120.9 20.4h.5v1l-.5-.1v-.2l.2-.2-.3-.2zM121.1 20.9h.3M121.8 20.5a.47 .47 0 0 1 .7 .3 .47 .47 0 0 1-.5 .6l-.2-.1M123.4 20.4v1h-.4l-.1-.1-.1-.2 .1-.2h.5"/>
<path d="M143 34h56.6M199 34v97M199 34l.6 1.1M199 34l-.6 1.1M67.5 48.5v4.1M67.5 52h25M67.5 52l1.1 .6M68.6 51.4l-1.1 .6M75.4 50.4l.4-.1 .2 .3-.7 .7h.7M76.9 50.3h-.5l-.1 .5 .2-.1h.3l.1 .2v.3l-.2 .1-.4-.1M77.3 51.2v.1M77.9 50.4l.1-.1a.53 .53 0 0 1 .3 .5 .53 .53 0 0 1-.3 .5 .66 .66 0 0 1-.1-.9z"/>
<path d="M78.9 50.4l.1-.1a.53 .53 0 0 1 .3 .5 .53 .53 0 0 1-.3 .5 .67 .67 0 0 1-.1-.9zM79.8 50.4l.1-.1a.53 .53 0 0 1 .4 .5 .53 .53 0 0 1-.4 .5 .67 .67 0 0 1-.1-.9zM80.8 50.4l.1-.1a.53 .53 0 0 1 .3 .5 .53 .53 0 0 1-.3 .5 .66 .66 0 0 1-.1-.9zM82.4 50.6v.7M82.4 50.7l.3-.1 .1 .2M82.8 50.8l.2-.2 .2 .1v.6M82.8 50.8v.5M83.7 50.7l.3-.1 .1 .2M83.7 50.6v.7M84.1 50.8l.2-.2 .2 .1 .1 .6M84.1 50.8v.5M91.4 51.4l1.1 .6"/>
<path d="M92.5 48.5v4.1M92.5 52l-1.1 .6M141.2 54.8l-.2 .7h.6M141.5 55.1v.7M142.5 55.2l-.2 .2h-.2l-.1-.2 .1-.3 .2-.1 .2 .1a.66 .66 0 0 1-.3 .9h-.1M143.7 55.1v.7M143.7 55.2l.3-.1 .1 .2M144.1 55.3l.2-.2 .2 .1 .1 .6M144.1 55.3v.5M145.1 55.2l.2-.1 .2 .2M145.1 55.1v.7M145.5 55.3l.1-.2 .3 .1v.6"/>
<path d="M145.5 55.3v.5M168.2 54h.6l-.3 .3 .3 .1v.5l-.2 .1-.4-.1M169.3 54.9v.1M170.2 54h-.5v.4l.1-.1 .4 .1 .1 .1-.1 .4-.1 .1-.4-.1M171.5 54.3v.7M171.5 54.4l.2-.1 .2 .1M171.9 54.4l.1-.1h.3v.7M171.9 54.4v.6M172.8 54.4l.3-.1 .1 .1M172.8 54.3v.7M173.2 54.4l.2-.1h.2v.7M173.2 54.4v.6"/>
<path d="M197.3 52.1v-.6l.4 .3 .1-.3h.4l.1 .1-.1 .5M197.3 53v-.6l.4 .3 .1-.2h.4l.1 .1-.1 .4M197.6 50.3h.7M197.6 48.9h.7M197.8 49.8l-.2 .2 .1 .3M197.8 48.5l-.2 .1 .1 .3M197.8 49.8h.5M197.8 48.5h.5M198.3 48.1h-.6l-.1 .3 .2 .1M198.3 49.4l-.6 .1-.1 .2 .2 .1M110.1 77.8h.7M110.1 76.4h.7"/>
<path d="M110.2 79l.2 .1v.2l-.2 .2-.4-.1v-.3l.1-.1a.66 .66 0 0 1 .9 .2v.2M110.3 77.3l-.2 .2 .1 .3M110.3 76l-.2 .1 .1 .3M110.3 77.3h.5M110.3 76h.5M110.8 79.9v.6l-.7-.6-.3 .2 .1 .4M110.8 75.6h-.6l-.1 .3 .2 .1M110.8 76.9l-.6 .1-.1 .2 .2 .1M143 67h56.6M198.4 65.9l1.2 2.2M199.6 65.9l-1.2 2.2M199.8 74.8h.7"/>
<path d="M199.8 73.5h.7M200 74.4l-.2 .1 .1 .3M200 73l-.2 .2 .1 .3M200 74.4h.5M200 73h.5M200.5 76v.5M200.5 76.9v.6M200.5 77.9v.6M200.5 78.2h-1l.3 .3M200.5 77.2h-1l.3 .3M200.5 76.3h-1l.3 .2M200.5 72.6h-.6l-.1 .3 .2 .1"/>
<path d="M200.5 73.9l-.6 .1-.1 .2 .2 .2M101.3 94.5v.3a.67 .67 0 0 0 1 0l-.1-.3-.3-.1-.2 .2v.3l.2 .1M101.3 93.5v.5h.5l-.1-.1v-.3l.2-.1h.3l.1 .1-.1 .4M101.6 92.3h.7M101.6 90.9h.7M101.8 91.8h.5M101.8 90.5h.5M101.8 91.8l-.2 .2 .1 .3M101.8 90.5l-.2 .1 .1 .3M102.3 91.4l-.6 .1-.1 .2 .2 .1M102.3 90.1h-.6l-.1 .3 .2 .1M105.8 94.5v.4l.5 .1-.1-.2v-.3l.2-.1 .3 .1 .1 .1-.1 .4"/>
<path d="M106.1 92.3h.7M106.1 90.9h.7M106.2 93.6l-.2-.1-.2 .1v.3l.2 .1 .2-.2M106.2 93.6l.2-.1h.3l.1 .1-.1 .3-.1 .1h-.3l-.1-.2M106.2 93.6v.2M106.3 90.5l-.2 .1 .1 .3M106.3 91.8l-.2 .2 .1 .3M106.3 91.8h.5M106.3 90.5h.5M106.8 90.1h-.6l-.1 .3 .2 .1M106.8 91.4l-.6 .1-.1 .2 .2 .1M197.3 95v.4l.5 .1-.1-.2v-.3l.2-.1 .3 .1 .1 .1-.1 .4"/>
<path d="M197.6 92.8h.7M197.6 91.4h.7M197.8 91l-.2 .1 .1 .3M197.8 92.3l-.2 .2 .1 .3M197.8 92.3h.5M197.8 91h.5M198.3 94v.6l-.7-.6-.3 .1 .1 .4M198.3 90.6h-.6l-.1 .3 .2 .1M198.3 91.9l-.6 .1-.1 .2 .2 .1M30 119.5v23.1M105 119.5v23.1M180.2 119h19.4"/>
<path d="M198.4 117.9l1.2 2.2M199.6 117.9l-1.2 2.2M18 125.5v20.1M180.2 131h21.6M192 125.5v20.1M197.8 123.9h.7M197.8 122.5h.7M197.9 123.4l-.1 .2 .1 .3M197.9 122.1l-.1 .1 .1 .3M197.9 123.4h.6M197.9 122.1h.6M198.4 129.9l.6 1.1"/>
<path d="M198.5 125.1v.6l-.8-.6h-.2v.1v.4M198.5 126v.6M198.5 126.3h-1l.2 .3M198.5 121.7h-.7v.3l.1 .1M198.5 123l-.7 .1v.2l.1 .1M199.6 129.9l-.6 1.1M200.6 129.9l.6 1.1M201.8 129.9l-.6 1.1M18 145h174M18 145l1.1 .6M19.1 144.5l-1.1 .5M30 142h75"/>
<path d="M30 142l1.1 .6M31.1 141.4l-1.1 .6M62.8 140.3h.7l-.4 1M64.4 140.3h-.5l-.1 .5 .2-.1h.3l.1 .2v.3l-.2 .1-.4-.1M64.8 141.2v.1M65.4 140.4l.1-.1a.53 .53 0 0 1 .3 .5 .53 .53 0 0 1-.3 .5 .67 .67 0 0 1-.1-.9zM66.4 140.4l.1-.1a.53 .53 0 0 1 .3 .5 .53 .53 0 0 1-.3 .5 .67 .67 0 0 1-.1-.9zM67.3 140.4l.1-.1a.53 .53 0 0 1 .4 .5 .53 .53 0 0 1-.4 .5 .67 .67 0 0 1-.1-.9zM68.2 140.4l.2-.1a.53 .53 0 0 1 .3 .5 .53 .53 0 0 1-.3 .5l-.2-.1-.1-.3zM69.9 140.6v.7M69.9 140.7l.3-.1 .1 .2M70.3 140.8l.2-.2 .2 .1v.6"/>
<path d="M70.3 140.8v.5M71.2 140.7l.3-.1 .1 .2M71.2 140.6v.7M71.6 140.8l.2-.2 .2 .1 .1 .6M71.6 140.8v.5M100.9 147.1h.5M100.9 146.4l.2-.3v1M102 146.5l-.2 .2v.2l.2 .2h.3l.1-.2v-.2l-.2-.2M102 146.5l-.2-.2 .2-.2 .3 .1 .1 .1-.2 .2M102 146.5h.2M102 144.4h.6M102 143.6l.3-.2v1"/>
<path d="M102.9 146.2l.1-.1a.53 .53 0 0 1 .3 .5 .53 .53 0 0 1-.3 .5l-.1-.1-.1-.3zM103 143.4h.6l-.4 1M103.8 147v.1M103.9 141.4l1.1 .6M104.2 143.3l-.2 .7h.6M104.4 146.5l-.2 .2v.3l.2 .1h.3l.1-.2-.1-.3-.1-.1M104.4 146.5l-.2-.2 .2-.2 .3 .1 .1 .1-.2 .2M104.4 146.5h.2M104.4 143.7v.7M105 142l-1.1 .6M105.4 146.1l-.3 .7h.7M105.6 146.4v.7"/>
<path d="M105.7 143.7v.7M105.7 143.8l.3-.1 .1 .1M106.1 143.8l.2-.1h.2l.1 .7M106.1 143.8v.6M106.9 146.4v.7M106.9 146.5l.3-.1 .1 .2M107 143.8l.3-.1 .2 .1M107 143.7v.7M107.3 146.6l.2-.2 .2 .1 .1 .6M107.3 146.6v.5M107.5 143.8l.1-.1h.3v.7M107.5 143.8v.6"/>
<path d="M108.2 146.5l.3-.1 .2 .2M108.2 146.4v.7M108.7 146.6l.1-.2 .2 .1 .1 .6M108.7 146.6v.5M190.9 144.5l1.1 .5M192 145l-1.1 .6"/>
</g>
<g fill="none" stroke="#000084" stroke-width=".15">
<circle cx="25" cy="23" r="2.35"/>
<circle cx="185" cy="23" r="2.35"/>
<circle cx="30" cy="67" r="3"/>
<circle cx="105" cy="67" r="3"/>
<circle cx="119" cy="63.5" r="2.35"/>
<circle cx="168" cy="63.5" r="2.35"/>
<circle cx="180" cy="67" r="3"/>
<circle cx="105" cy="98" r="2.35"/>
<circle cx="30" cy="119" r="3"/>
<circle cx="105" cy="119" r="3"/>
<circle cx="180" cy="119" r="3"/>
<circle cx="42" cy="128" r="2.35"/>
<circle cx="119" cy="121.5" r="2.35"/>
<circle cx="168" cy="121.5" r="2.35"/>
<circle cx="168" cy="128" r="2.35"/>
</g>
<g fill="none" stroke="#480000" stroke-width=".15">
<path d="M10 10h277v190h-277zM12 12h273v186h-273zM35.3 11.6h.8M35.3 10.7l.4-.4v1.3M60 10v2M85.3 10.4l.2-.1 .5 .1a.35 .35 0 0 1 0 .5l-.7 .7h.8M110 10v2M135.3 10.3h.8l-.4 .5a.35 .35 0 0 1 .4 .2v.3l-.1 .2-.5 .1-.2-.1M160 10v2M185.7 10.2l-.4 1h.9M186 10.7v.9M210 10v2"/>
<path d="M236 10.3h-.6l-.1 .6 .2-.1 .5 .1 .1 .1-.1 .5-.2 .1h-.3l-.2-.1M260 10v2M286 10.3a.52 .52 0 0 0-.7 .6v.4l.2 .2 .3 .1 .2-.1 .1-.5-.1-.1-.4-.1-.3 .2M10.6 35.6l.4-1.3 .4 1.3M10.7 35.2h.6M285.6 35.6l.4-1.3 .4 1.3M285.7 35.2h.6M10 60h2M285 60h2M10.7 84.3h.4l.2 .1v.3l-.2 .2a.35 .35 0 0 1 .3 .3 .35 .35 0 0 1-.2 .4h-.5zM10.7 84.9h.4M285.7 84.3h.4l.2 .1v.3l-.2 .2a.35 .35 0 0 1 .3 .3 .35 .35 0 0 1-.2 .4h-.5z"/>
<path d="M285.7 84.9h.4M10 110h2M285 110h2M11.4 134.4a.52 .52 0 0 0-.6 0 .52 .52 0 0 0-.2 .6 .49 .49 0 0 0 .2 .5 .49 .49 0 0 0 .6 0M286.4 134.4a.52 .52 0 0 0-.6 0 .52 .52 0 0 0-.2 .6 .49 .49 0 0 0 .3 .5 .49 .49 0 0 0 .5 0M10 160h2M285 160h2M177 166h108v32h-108zM178.5 173.2v1.5h.7M179.2 176.3l-.5-.1a.36 .36 0 0 0-.3 .4 .36 .36 0 0 0 .3 .3 .55 .55 0 0 1 .5 .4v.3l-.2 .1-.6-.1M179.2 170.3a.62 .62 0 0 0-.7 .1 .62 .62 0 0 0-.1 .7 .56 .56 0 0 0 .3 .5 .56 .56 0 0 0 .6 0v-.5h-.3M179.7 173.2v.1"/>
<path d="M179.7 173.7v1M179.7 173.2l-.1 .1h.1M180 170.2v.1M180 170.7v1M180 176.8a.41 .41 0 0 1 .6 .2v.4a.41 .41 0 0 1-.4 .3 .41 .41 0 0 1-.4-.3v-.4zM180 170.2l-.1 .1h.1M180.5 170.7h.5M180.7 170.2v1.3v.1l.3 .1M181 173.8l-.4-.1-.3 .3v.4l.2 .2 .1 .1 .4-.1M181.2 176.7l.1 .9a.41 .41 0 0 0 .6 0M181.6 174.2l.7-.1-.1-.3-.4-.1-.2 .2 .1 .7 .1 .1 .4-.1M181.9 176.7v1"/>
<path d="M182.6 176.7v1M183 173.8a.37 .37 0 0 1 .6 .1v.8M183 173.7v1M183 176.7l-.3 .1-.1 .2M183.3 170.8l-.4-.1-.3 .3v.4l.1 .2 .2 .1 .4-.1M184 170.8a.41 .41 0 0 1 .4-.1 .41 .41 0 0 1 .3 .3v.4a.41 .41 0 0 1-.4 .3 .41 .41 0 0 1-.4-.3zM184.2 176.8l-.5-.1-.2 .3v.4l.1 .2 .1 .1 .5-.1M184.7 177.2l.8-.1-.1-.3-.4-.1-.3 .2 .1 .7 .2 .1 .4-.1M184.8 173.8l-.3-.1-.3 .2 .1 .2 .5 .2 .1 .1-.1 .2-.1 .1-.5-.1M185.3 170.8a.37 .37 0 0 1 .7 .1M185.3 170.7v1M185.5 174.2l.7-.1-.1-.3-.4-.1-.2 .2v.7l.2 .1 .4-.1"/>
<path d="M186 170.9l.2-.2 .3 .1 .1 .9M186 170.9v.8M186.8 174.6h.1l-.1 .1M186.8 174.6h-.1l.1 .1M186.8 173.8v.1M186.8 174.6v.1M186.8 173.8h.1l-.1 .1M186.8 173.8h-.1l.1 .1M187.3 170.8a.37 .37 0 0 1 .7 .1M187.3 170.7v1M188 170.9l.2-.2 .3 .1 .1 .9M188 170.9v.8"/>
<path d="M188.1 176.3a.6 .6 0 0 0-.7 0 .6 .6 0 0 0-.2 .8 .56 .56 0 0 0 .3 .5 .56 .56 0 0 0 .6 0M188.8 176.8a.41 .41 0 0 1 .7 .2v.4a.41 .41 0 0 1-.4 .3 .41 .41 0 0 1-.4-.3v-.4zM189.3 170.2l-.1 .1h.1M189.3 170.2v.1M189.3 170.7v1M189.3 170.2l.1 .1h-.1M189.5 173.3a.6 .6 0 0 0-.7 0 .6 .6 0 0 0-.2 .8 .56 .56 0 0 0 .3 .5 .56 .56 0 0 0 .6 0M189.8 170.7h.6M190 170.2v1.3l.1 .1 .3 .1M190.2 173.9h.5M190.7 176.2v1.5M190.7 176.8l-.4-.1-.3 .3v.4l.2 .2 .1 .1 .4-.1"/>
<path d="M190.9 173.2h-.7v1.5h.7M191.4 177.2l.7-.1-.1-.3-.4-.1-.2 .2 .1 .7 .1 .1 .4-.1M191.5 174h.6a.41 .41 0 0 0 .3-.4 .41 .41 0 0 0-.3-.4h-.6v1.5M191.9 174l.5 .7M192 170.8a.37 .37 0 0 1 .7 .1v.8M192 170.2v1.5M192.7 177.6h.1l-.1 .1M192.7 177.6v.1M192.7 176.8v.1M192.7 176.8h.1l-.1 .1M193.4 170.8l.1-.1 .5 .1v.9M193.9 173.2v1.5l-.9-1.5v1.5"/>
<path d="M194 171.1h-.5a.29 .29 0 0 0-.2 .3 .29 .29 0 0 0 .2 .3l.5-.1M194.6 176.2v1.5M194.6 176.8a.37 .37 0 0 1 .6 .1v.8M195.2 170.8l-.3-.1-.2 .2v.2l.5 .2 .1 .1-.1 .2-.1 .1-.4-.1M195.7 173.4a.5 .5 0 0 1 .6-.2 .5 .5 0 0 1 .4 .5v.5a.5 .5 0 0 1-.5 .5 .5 .5 0 0 1-.5-.5zM195.7 176.7h.6M196 176.2v1.3v.1l.3 .1M196 170.2v1.5M196 170.8a.37 .37 0 0 1 .6 .1v.8M196.6 176.7h.6M196.8 176.2v1.3l.1 .1 .3 .1M197.3 173.8l.4-.1 .3 .3v.4l-.1 .2-.2 .1-.4-.1"/>
<path d="M197.3 170.8v.1M197.3 171.6v.1M197.3 173.7v1.5M197.3 171.6h.1l-.1 .1M197.3 171.6h-.1l.1 .1M197.3 170.8h.1l-.1 .1M197.3 170.8h-.1l.1 .1M197.7 176.8l.4-.1 .3 .3v.4l-.2 .2-.1 .1-.4-.1M197.7 176.7v1.5M198.6 174.2l.7-.1-.1-.3-.4-.1-.2 .2 .1 .7 .1 .1 .4-.1M199 170.2h1l-.5 .6a.41 .41 0 0 1 .5 .3v.3l-.2 .2-.6 .1-.2-.1M199.5 176.8l-.3-.1-.2 .2v.2l.5 .2 .1 .1-.1 .2-.1 .1-.4-.1"/>
<path d="M200 173.8a.37 .37 0 0 1 .6 .1v.8M200 173.7v1M200.2 177.6h.1l-.1 .1M200.2 177.6v.1M200.2 176.8v.1M200.2 176.8h.1l-.1 .1M200.8 170.8l-.2-.1a.3 .3 0 0 1 0-.3 .3 .3 0 0 1 .2-.2l.4 .1a.31 .31 0 0 1 .2 .3 .31 .31 0 0 1-.3 .2M200.8 170.8l-.3 .3v.3l.3 .3h.3l.3-.3v-.3l-.3-.3M200.8 170.8h.3M202 176.1l-1.3 2M202.5 173.9h.8M202.5 173.2v1.5"/>
<path d="M202.7 170.2h-.7v.7l.2-.1h.5l.1 .3-.1 .5-.2 .1h-.3l-.2-.1M203.3 173.2v1.5M203.5 170.3a.36 .36 0 0 1 .4-.1 .36 .36 0 0 1 .3 .3 .78 .78 0 0 1-.5 1.2 .91 .91 0 0 1-.2-1.4zM203.6 176.1l-1.3 2M204 173.8l.2-.1 .4 .1 .1 .9M204.7 174.1h-.5a.29 .29 0 0 0-.3 .3 .29 .29 0 0 0 .3 .3l.5-.1M204.7 176.8l-.4-.1-.3 .3v.4l.2 .2 .1 .1 .4-.1M204.7 176.7v1.2a.41 .41 0 0 1-.6 .2M204.9 170.8l.1-.1 .5 .1v.9M205.4 173.7v1M205.5 176.2v.1M205.5 176.7v1"/>
<path d="M205.5 176.2l-.1 .1h.1M205.5 171.1h-.5a.29 .29 0 0 0-.2 .3 .29 .29 0 0 0 .2 .3l.5-.1M205.8 173.7l-.3 .1-.1 .2M206 176.7h.5M206.2 176.2v1.3v.1l.3 .1M206.5 170.8l-.3-.1a.3 .3 0 0 1 0-.3 .3 .3 0 0 1 .3-.2l.4 .1a.31 .31 0 0 1 .1 .3 .31 .31 0 0 1-.3 .2M206.5 170.8l-.3 .3v.3l.3 .3h.2l.3-.3v-.3l-.3-.3M206.5 170.8h.2M207 173.8l-.5-.1-.3 .3v.4l.2 .2 .1 .1 .5-.1M207 173.2v1.5M207 176.8a.37 .37 0 0 1 .7 .1v.8M207 176.2v1.5"/>
<path d="M207.5 173.7l.3 1 .3-.7 .3 .7 .3-1M208.3 170.8l-.4-.1-.3 .3v.4l.1 .2 .2 .1 .4-.1M208.4 176.7l.1 .9a.41 .41 0 0 0 .5 0M208.9 170.3l.2-.1 .5 .1a.41 .41 0 0 1 .1 .5l-.9 .9h.9M209 176.7v1M209.2 173.8l.2-.1 .4 .1 .1 .9M209.7 176.8l.5-.1 .3 .3v.4l-.2 .2-.1 .1-.5-.1M209.7 176.2v1.5M209.9 174.1h-.5a.3 .3 0 0 0-.2 .3 .3 .3 0 0 0 .2 .3l.5-.1M210.6 173.7v1M211 173.7l-.3 .1-.1 .2M211.1 177.6h.1l-.1 .1"/>
<path d="M211.1 177.6h-.1l.1 .1M211.1 177.6v.1M211.5 174.2l.7-.1-.1-.3-.4-.1-.2 .2v.7l.2 .1 .4-.1M212.5 176.8l-.5-.1-.3 .3v.4l.2 .2 .1 .1 .5-.1M213.1 176.8a.41 .41 0 0 1 .4-.1 .41 .41 0 0 1 .3 .3v.4a.41 .41 0 0 1-.4 .3 .41 .41 0 0 1-.4-.3zM214 173.2v1.5h.7M214.5 176.8a.37 .37 0 0 1 .6 .1M214.5 176.7v1M215.1 176.9l.2-.2 .4 .1v.9M215.1 176.9v.8M215.2 173.2l-.1 .1h.1M215.2 173.2v.1"/>
<path d="M215.2 173.7v1M216.5 173.8l-.4-.1-.3 .3v.4l.2 .2 .1 .1 .4-.1M217.1 174.2l.7-.1-.1-.3-.4-.1-.2 .2 .1 .7 .1 .1 .4-.1M217.5 176.1l-1.3 2M218 176.7v1.5M218 176.8l.5-.1 .2 .3v.4l-.1 .2-.1 .1-.5-.1M218.5 173.8a.37 .37 0 0 1 .6 .1v.8M218.5 173.7v1M219.3 177.2l.7-.1v-.3l-.5-.1-.2 .2 .1 .7 .1 .1 .5-.1M220.5 173.8l-.5-.1-.3 .3v.4l.2 .2 .1 .1 .5-.1M221 174.2l.7-.1v-.3l-.5-.1-.2 .2 .1 .7 .1 .1 .5-.1M221.3 176.8l-.4-.1-.3 .3v.4l.1 .2 .2 .1 .4-.1"/>
<path d="M221.3 176.2v1.5M222 176.8l.2-.1 .4 .1 .1 .9M222.7 177.1h-.5a.29 .29 0 0 0-.3 .3 .29 .29 0 0 0 .3 .3l.5-.1M223.3 173.2l.5 1.5 .5-1.5M223.4 176.2v1.3l.2 .2M224.2 176.8l.4-.1 .3 .3v.4l-.2 .2-.1 .1-.4-.1M224.2 176.2v1.5M224.7 174.2l.8-.1-.1-.3-.4-.1-.3 .2 .1 .7 .2 .1 .4-.1M225.6 176.8a.41 .41 0 0 1 .6 .2v.4a.41 .41 0 0 1-.3 .3 .41 .41 0 0 1-.4-.3v-.4zM226.1 173.7v1M226.5 173.7l-.3 .1-.1 .2M226.9 176.8l.1-.1 .5 .1v.9"/>
<path d="M227.5 177.1h-.5a.29 .29 0 0 0-.2 .3 .29 .29 0 0 0 .2 .3l.5-.1M227.5 173.8l-.3-.1-.2 .2v.2l.5 .2 .1 .1-.1 .2-.1 .1-.4-.1M228.2 173.2v.1M228.2 173.7v1M228.2 176.7v1M228.2 173.2l.1 .1h-.1M228.7 176.7l-.3 .1-.2 .2M229 173.8a.41 .41 0 0 1 .7 .2v.4a.41 .41 0 0 1-.4 .3 .41 .41 0 0 1-.4-.3v-.4zM229.8 176.8l-.4-.1-.3 .3v.4l.1 .2 .2 .1 .4-.1M229.8 176.2v1.5M230.3 173.8a.37 .37 0 0 1 .7 .1v.8M230.3 173.7v1"/>
<path d="M231.6 176.1l-1.3 2M232.1 176.8l.4-.1 .3 .3v.4l-.1 .2-.2 .1-.4-.1M232.1 176.7v1.5M232.7 173.3l.3-.1 .5 .1a.41 .41 0 0 1 0 .5l-.8 .9h.9M233.4 177.2l.7-.1-.1-.3-.4-.1-.2 .2 .1 .7 .1 .1 .4-.1M235.4 176.8l-.4-.1-.3 .3v.4l.1 .2 .2 .1 .4-.1M235.4 176.2v1.5M235.4 174.1h1.1M236.1 176.8l.1-.1 .5 .1v.9M236.7 177.1h-.5a.29 .29 0 0 0-.2 .3 .29 .29 0 0 0 .2 .3l.5-.1M237.5 176.2v1.3l.2 .2M238.2 176.8l.5-.1 .3 .3v.4l-.2 .2-.1 .1-.5-.1"/>
<path d="M238.2 176.2v1.5M238.4 174h.6a.41 .41 0 0 0 .3-.4 .41 .41 0 0 0-.3-.4h-.6v1.5M239.7 176.8a.41 .41 0 0 1 .6 .2v.4a.41 .41 0 0 1-.4 .3 .41 .41 0 0 1-.4-.3v-.4zM239.8 174.2l.7-.1v-.3l-.5-.1-.2 .2 .1 .7 .1 .1 .5-.1M241 176.8l.1-.1 .4 .1 .1 .9M241.2 173.7v1M241.6 177.1h-.5a.29 .29 0 0 0-.2 .3 .29 .29 0 0 0 .2 .3l.5-.1M241.6 173.7l-.3 .1-.1 .2M242.1 173.8a.37 .37 0 0 1 .6 .1M242.1 173.7v1M242.3 176.7v1M242.7 176.7l-.2 .1-.2 .2"/>
<path d="M242.7 173.9l.3-.2 .3 .1 .1 .9M242.7 173.9v.8M243.9 176.8l-.4-.1-.3 .3v.4l.1 .2 .2 .1 .4-.1M243.9 176.2v1.5M244.1 173.2v.1M244.1 173.7v1M244.1 173.2l-.1 .1h.1M244.1 173.2l.1 .1h-.1M244.6 177.1h1.1M245.3 173.8l-.3-.1-.3 .2 .1 .2 .5 .2 .1 .1-.1 .2-.1 .1-.5-.1M246.5 176.8a.37 .37 0 0 1 .6 .1v.8M246.5 176.2v1.5"/>
<path d="M246.5 173.8l-.3-.1-.2 .2v.2l.5 .2 .1 .1-.1 .2-.1 .1-.4-.1M247.2 173.2v.1M247.2 173.7v1M247.2 173.2l.1 .1h-.1M247.7 176.7l.3 1 .2-.7 .3 .7 .3-1M247.8 173.7l.4 1 .3-1M249 174.2l.7-.1v-.3l-.5-.1-.2 .2 .1 .7 .1 .1 .5-.1M10.7 184.3a.66 .66 0 0 1 .7 .6 .66 .66 0 0 1-.7 .7zM35.3 198.7l.4-.4v1.3M35.3 199.6h.8M60 198v2M85.3 198.4l.2-.1 .5 .1a.35 .35 0 0 1 0 .5l-.7 .7h.8"/>
<path d="M110 198v2M135.3 198.3h.8l-.4 .5a.35 .35 0 0 1 .4 .2v.4l-.1 .1-.5 .1-.2-.1M160 198v2M177 194.5h108M177 191.5h108M177 187.5h108M177 181.5h108M178.5 185.6h.5M178.5 195.1v1.5M178.7 195.7l.6 .9M179.2 184.9h-.7v1.5M179.2 192.4l-.5-.1a.36 .36 0 0 0-.3 .4 .36 .36 0 0 0 .3 .3 .55 .55 0 0 1 .5 .4v.3l-.2 .1-.6-.1"/>
<path d="M179.2 182.3l-.5-.1a.36 .36 0 0 0-.3 .4 .36 .36 0 0 0 .3 .3 .55 .55 0 0 1 .5 .4v.3l-.2 .1-.6-.1M179.3 195.1l-.8 .9M179.7 184.9v.1M179.7 185.4v1M179.7 184.9l.1 .1h-.1M179.9 182.2v1.5M179.9 192.3v.1M179.9 192.8v1M179.9 192.3l-.1 .1h.1M179.9 192.3l.1 .1h-.1M179.9 182.8a.37 .37 0 0 1 .6 .1v.8M180 195.1v.1"/>
<path d="M180 195.6v1M180 195.1l-.1 .1h.1M180.5 192.8h.7l-.7 1h.7M180.5 184.9v1.3l.2 .2M181.2 183.2l.7-.1-.1-.3-.4-.1-.2 .2v.7l.2 .1 .4-.1M181.2 185.9l.7-.2-.1-.2-.4-.1-.2 .2v.7l.2 .1 .4-.1M181.5 195.2a.6 .6 0 0 0-.7 0 .6 .6 0 0 0-.2 .8 .56 .56 0 0 0 .3 .5 .56 .56 0 0 0 .6 0M181.7 193.3l.8-.1-.1-.3-.4-.1-.3 .2 .1 .7 .2 .1 .4-.1M182.2 195.7l.1-.1 .4 .1 .1 .9M182.5 183.2l.7-.1-.1-.3-.4-.1-.2 .2v.7l.2 .1 .4-.1M182.5 186.3h.1l-.1 .1M182.5 186.3v.1"/>
<path d="M182.5 185.5v.1M182.5 185.5h.1l-.1 .1M182.8 196h-.5a.29 .29 0 0 0-.2 .3 .29 .29 0 0 0 .2 .3l.5-.1M183.1 193.7h.1l-.1 .1M183.1 193.7h-.1l.1 .1M183.1 192.9v.1M183.1 193.7v.1M183.1 192.9h.1l-.1 .1M183.1 192.9h-.1l.1 .1M183.6 182.7h.6M183.8 182.2v1.3l.1 .1 .3 .1M184.2 195.7l-.5-.1-.2 .3v.4l.1 .2 .1 .1 .5-.1"/>
<path d="M184.2 195.1v1.5M184.4 185.5l.4-.1 .3 .3v.4l-.1 .2-.2 .1-.4-.1M184.4 185.4v1.5M184.7 183.6v.1M184.7 183.6h-.1l.1 .1M184.7 182.8v.1M184.7 182.8h-.1l.1 .1M184.7 193.8l.5-1.5 .5 1.5M184.9 193.4h.7M185.7 198.2l-.4 1h.9M185.7 185.9l.7-.2-.1-.2-.4-.1-.2 .2v.7l.2 .1 .4-.1M186 198.7v.9"/>
<path d="M186 195.8h.5M186.5 192.2l-.3 1.1h.9M186.5 182.9h.5M186.7 195.1h-.7v1.5h.7M186.9 192.8v1M187.2 182.2h-.7v1.5M187.4 196.5h.1l-.1 .1M187.4 196.5h-.1l.1 .1M187.4 196.5v.1M187.7 185.5l-.5-.1-.2 .3v.4l.1 .2 .1 .1 .5-.1M187.7 184.9v1.5M187.8 182.7v1"/>
<path d="M188.1 195.1a.79 .79 0 0 1 .9 .5 .79 .79 0 0 1-.3 .9l-.6 .1zM188.2 182.7l-.2 .1-.2 .2M188.4 185.5l.1-.1 .5 .1v.9M188.8 182.8a.41 .41 0 0 1 .7 .2v.4a.41 .41 0 0 1-.4 .3 .41 .41 0 0 1-.4-.3v-.4zM189 185.7l-.5 .1a.3 .3 0 0 0-.2 .3 .3 .3 0 0 0 .2 .3l.5-.1M189.6 196.5h.1l-.1 .1M189.6 196.5h-.1l.1 .1M189.6 196.5v.1M189.7 184.9v1.3l.3 .2M190.1 196.6l.5-1.5 .5 1.5M190.1 182.8a.37 .37 0 0 1 .6 .1v.8M190.1 182.7v1"/>
<path d="M190.2 196.2h.8M190.5 185.5l.5-.1 .2 .3v.4l-.1 .2-.1 .1-.5-.1M190.5 184.9v1.5M191.2 182.7h.6M191.5 182.2v1.3v.1l.3 .1M191.6 196.5h.1l-.1 .1M191.6 196.5h-.1l.1 .1M191.6 196.5v.1M191.9 185.5a.41 .41 0 0 1 .4-.1 .41 .41 0 0 1 .3 .3v.4a.41 .41 0 0 1-.4 .3 .41 .41 0 0 1-.4-.3zM193.2 185.5l.2-.1 .4 .1 .1 .9M193.4 196.6h.8M193.4 195.5l.4-.4v1.5"/>
<path d="M193.9 185.7l-.5 .1a.29 .29 0 0 0-.2 .3 .29 .29 0 0 0 .2 .3l.5-.1M194.1 182.8l-.4-.1-.3 .3v.4l.1 .2 .2 .1 .4-.1M194.1 182.2v1.5M194.6 185.4v1M194.8 182.8a.41 .41 0 0 1 .4-.1 .41 .41 0 0 1 .3 .3v.4a.41 .41 0 0 1-.4 .3 .41 .41 0 0 1-.4-.3zM195 195.2a.36 .36 0 0 1 .3-.1 .36 .36 0 0 1 .3 .3 .77 .77 0 0 1-.4 1.2 .91 .91 0 0 1-.2-1.4zM195 185.4l-.3 .1-.1 .2M196.2 185.5l-.5-.1-.2 .3v.4l.1 .2 .1 .1 .5-.1M196.2 184.9v1.5M196.3 196.5h.1l-.1 .1M196.3 196.5h-.1l.1 .1M196.3 196.5v.1"/>
<path d="M196.8 182.8l-.4-.1-.3 .3v.4l.1 .2 .2 .1 .4-.1M196.9 185.8h1.1M197 191.5v3M197.1 195.2a.36 .36 0 0 1 .4-.1 .36 .36 0 0 1 .2 .3 .77 .77 0 0 1-.4 1.2 .91 .91 0 0 1-.2-1.4zM197.5 182.7v.9a.41 .41 0 0 0 .6 0M198.1 182.7v1M198.5 196.5v.1M198.5 196.5h-.1l.1 .1M198.7 185.5a.37 .37 0 0 1 .7 .1v.8M198.7 184.9v1.5M198.8 182.8a.37 .37 0 0 1 .7 .1M198.8 182.7v1"/>
<path d="M199.1 196.6h.9M199.1 195.5l.4-.4v1.5M199.5 182.9l.2-.2 .3 .1 .1 .9M199.5 182.9v.8M200 185.4l.2 1 .3-.7 .3 .7 .3-1M200.5 192.3a.79 .79 0 0 1 .8 .5 .79 .79 0 0 1-.3 .9l-.5 .1zM200.6 196h1.1M200.7 183.2l.8-.1-.1-.3-.4-.1-.3 .2 .1 .7 .2 .1 .4-.1M201.7 186.3v.1M201.7 186.3h-.1l.1 .1M202 192.9l.1-.1 .4 .1 .1 .9M202.1 182.8a.37 .37 0 0 1 .6 .1v.8"/>
<path d="M202.1 182.7v1M202.4 196.6h.8M202.4 195.5l.4-.4v1.5M202.4 184.9v1.5M202.5 185.8l.5 .6M202.6 193.2h-.5a.29 .29 0 0 0-.2 .3 .29 .29 0 0 0 .2 .3l.5-.1M203 185.4l-.6 .6M203.1 192.8h.6M203.2 182.7h.6M203.3 192.3v1.3l.1 .1 .3 .1M203.5 182.2v1.3v.1l.3 .1M203.6 184.9v.1"/>
<path d="M203.6 185.4v1M203.6 184.9l-.1 .1h.1M203.6 184.9l.1 .1h-.1M204 195.2a.36 .36 0 0 1 .3-.1 .36 .36 0 0 1 .3 .3 .77 .77 0 0 1-.4 1.2 .91 .91 0 0 1-.2-1.4zM204.1 193.3l.7-.1-.1-.3-.4-.1-.2 .2 .1 .7 .1 .1 .4-.1M204.3 182.8l.2-.1 .4 .1 .1 .9M205 185.5l-.5-.1-.3 .3v.4l.2 .2 .1 .1 .5-.1M205 183.1h-.5a.29 .29 0 0 0-.3 .3 .29 .29 0 0 0 .3 .3l.5-.1M205.3 196.5h.1l-.1 .1M205.3 196.5h-.1l.1 .1M205.3 196.5v.1M205.5 193.7v.1"/>
<path d="M205.5 193.7h-.1l.1 .1M205.5 192.9v.1M205.5 192.9h-.1l.1 .1M205.5 182.7h.5M205.6 185.5l.1-.1 .5 .1v.9M205.7 182.2v1.3v.1l.3 .1M206.1 195.2a.36 .36 0 0 1 .4-.1 .36 .36 0 0 1 .2 .3 .77 .77 0 0 1-.4 1.2 .91 .91 0 0 1-.2-1.4zM206.2 185.7l-.5 .1a.29 .29 0 0 0-.2 .3 .29 .29 0 0 0 .2 .3l.5-.1M206.5 182.2v.1M206.5 182.7v1M206.5 182.2l.1 .1h-.1M207.2 192.4l.3-.1 .5 .1a.41 .41 0 0 1 0 .5l-.8 .9h.9"/>
<path d="M207.2 182.8a.41 .41 0 0 1 .4-.1 .41 .41 0 0 1 .4 .3v.4a.41 .41 0 0 1-.4 .3 .41 .41 0 0 1-.4-.3zM207.5 196.5v.1M207.5 196.5h-.1l.1 .1M207.6 185.5l-.4-.1-.3 .3v.4l.1 .2 .2 .1 .4-.1M207.6 184.9v1.5M208 186.5h1.1M208.1 196.6h.9M208.1 195.5l.4-.4v1.5M208.6 182.8a.37 .37 0 0 1 .6 .1v.8M208.6 182.7v1M208.9 192.4a.35 .35 0 0 1 .6 .2 .77 .77 0 0 1-.5 1.2 1 1 0 0 1-.1-1.4zM209.4 194.7h15.9"/>
<path d="M209.5 185.5l.4-.1 .3 .3v.4l-.2 .2-.1 .1-.4-.1M209.5 185.4v1.5M209.6 195.6l.1 .9a.41 .41 0 0 0 .5 0M210 198v2M210.1 192.4l.2-.1 .5 .1a.41 .41 0 0 1 .1 .5l-.9 .9h1M210.2 195.6v1M211 195.1v1.5M211 195.7l.4-.1 .3 .3v.4l-.2 .2-.1 .1-.4-.1M211.5 185.5l-.5-.1-.3 .3v.4l.2 .2 .1 .1 .5-.1M211.9 192.2l-.4 1.1h1M212.1 185.5l.4-.1 .3 .3v.4l-.1 .2-.2 .1-.4-.1M212.1 184.9v1.5"/>
<path d="M212.2 192.8v1M212.3 195.6l.1 .9a.41 .41 0 0 0 .6 0M213 195.6v1M213 193.2h1.2M213.7 195.7a.37 .37 0 0 1 .6 .1v.8M213.7 195.6v1M214.8 193.8h.9M214.8 192.7l.4-.4v1.5M214.8 195.6h.6M215 195.1v1.3l.1 .1 .3 .1M215.9 195.6l.1 .9a.41 .41 0 0 0 .5 0M216.5 192.4a.36 .36 0 0 1 .5 .2 .77 .77 0 0 1-.4 1.2 1 1 0 0 1-.1-1.4z"/>
<path d="M216.5 195.6v1M217.2 195.2l.2-.1 .5 .1a.41 .41 0 0 1 .1 .5l-.9 .9h.9M217.7 193.2h1.2M219.4 195.1h-.7l-.1 .7 .2-.1h.5l.2 .3-.1 .5-.2 .1h-.4l-.2-.1M219.5 193.8h.9M219.5 192.7l.5-.4v1.5M220.1 196.5h.1l-.1 .1M220.1 196.5h-.1l.1 .1M220.1 196.5v.1M220.7 196.6h.9M220.7 195.5l.5-.4v1.5M221.7 192.3a.6 .6 0 0 0-.7 .6v.6l.1 .2 .4 .1 .2-.1 .1-.5-.1-.3h-.5l-.2 .3"/>
<path d="M222.3 195.2a.36 .36 0 0 1 .4-.1 .36 .36 0 0 1 .3 .3 .77 .77 0 0 1-.5 1.2 .91 .91 0 0 1-.2-1.4zM223.7 196.5v.1M223.7 196.5h-.1l.1 .1M224.3 196.6h.9M224.3 195.5l.4-.4v1.5M227 196h1.1M227.5 195.4v1.2M230 195.1v1.5M230.2 195.7l.6 .9M230.8 195.1l-.8 .9M231.5 195.1v.1M231.5 195.6v1"/>
<path d="M231.5 195.1l-.1 .1h.1M232.2 195.1l.6 .1a.36 .36 0 0 1 .2 .3 .36 .36 0 0 1-.3 .3 .4 .4 0 0 1 .3 .4 .4 .4 0 0 1-.3 .4h-.5zM232.2 195.8h.5M233.7 195.7a.41 .41 0 0 1 .7 .2v.4a.41 .41 0 0 1-.4 .3 .41 .41 0 0 1-.4-.3v-.4zM234.8 195.6h.6M235 195.1v1.3l.1 .1 .3 .1M236 198.3h-.6l-.1 .6 .2-.1 .5 .1 .1 .1-.1 .5-.2 .1h-.3l-.2-.1M236.9 195.6l.3 1 .4-1M238.1 196.6h.9M238.1 195.5l.4-.4v1.5M239.6 196.5h.1l-.1 .1M239.6 196.5h-.1l.1 .1"/>
<path d="M239.6 196.5v.1M241.1 195.7l-.3 .3h-.3l-.3-.3v-.3l.2-.2 .4-.1 .2 .1a.99 .99 0 0 1-.3 1.4h-.3M241.7 196.5h.1l-.1 .1M241.7 196.5v.1M242.5 195.2a.36 .36 0 0 1 .4-.1 .36 .36 0 0 1 .3 .3 .77 .77 0 0 1-.5 1.2 .91 .91 0 0 1-.2-1.4zM260 198v2M261 191.5v6.5M263.5 195.1v1.5M264.8 195.7l-.4-.1-.3 .3v.4l.1 .2 .2 .1 .4-.1M264.8 195.1v1.5M265.5 196.5h.1l-.1 .1M265.5 196.5v.1"/>
<path d="M265.5 195.7v.1M265.5 195.7h.1l-.1 .1M268 195.1a.6 .6 0 0 0-.7 .6v.6l.2 .2 .4 .1 .2-.1 .1-.5-.2-.3h-.4l-.3 .3M269.9 195l-1.3 2M271 195.1a.6 .6 0 0 0-.7 .6v.6l.2 .2 .4 .1 .2-.1 .1-.5-.2-.3h-.4l-.3 .3M285.7 184.3a.66 .66 0 0 1 .7 .6 .66 .66 0 0 1-.7 .7zM286 198.3a.52 .52 0 0 0-.7 .6v.5l.2 .1 .3 .1 .2-.1 .1-.5-.1-.1-.4-.1-.3 .2"/>
</g>
<g fill="none" stroke="#480000" stroke-width=".3">
<path d="M178.6 179.2v1.5M178.6 179.8a.37 .37 0 0 1 .6 .1v.8M179.7 179.7h.6M179.9 179.2v1.3l.1 .1 .3 .1M180.6 179.7h.5M180.8 179.2v1.3v.1l.3 .1M181.6 179.8l.5-.1 .2 .3v.4l-.1 .2-.1 .1-.5-.1M181.6 179.7v1.5M183.5 179.8l-.4-.1-.2 .2 .1 .2 .5 .2 .1 .1-.1 .2-.2 .1-.4-.1M184.2 179.8v.1M184.2 179.8h.1l-.1 .1M184.2 179.8h-.1l.1 .1"/>
<path d="M186 179.1l-1.3 1.9M187.6 179.1l-1.3 1.9M188.7 179.8l-.4-.1-.3 .3v.4l.1 .2 .2 .1 .4-.1M188.7 179.7v1.2a.41 .41 0 0 1-.6 .2M189.4 179.2v.1M189.4 179.7v1M189.4 179.2l-.1 .1h.1M189.4 179.2l.1 .1h-.1M189.9 179.7h.6M190.1 179.2v1.3l.1 .1 .3 .1M191 179.8a.37 .37 0 0 1 .6 .1v.8M191 179.2v1.5"/>
<path d="M192.3 179.7l.1 .9a.41 .41 0 0 0 .6-.1M193 179.7v1M193.7 179.8l.4-.1 .3 .3v.4l-.1 .2-.2 .1-.4-.1M193.7 179.2v1.5M196.4 179.8l-.4-.1-.3 .3v.4l.1 .2 .2 .1 .4-.1M197.1 179.8a.41 .41 0 0 1 .4-.1 .41 .41 0 0 1 .3 .3v.4a.41 .41 0 0 1-.4 .3 .41 .41 0 0 1-.4-.3zM198.4 179.8a.37 .37 0 0 1 .7 .1M198.4 179.7v1M199.1 179.9l.2-.2 .3 .1 .1 .9M199.1 179.9v.8M201.5 179.1l-1.3 1.9M202 179.8l.4-.1 .3 .3v.4l-.1 .2-.2 .1-.4-.1"/>
<path d="M202 179.7v1.5M205.3 179.8l-.5-.1-.2 .3v.4l.1 .2 .1 .1 .5-.1M205.3 179.2v1.5M206 179.8l.1-.1 .5 .1v.9M207.3 179.2v1.3l.3 .2M208.1 179.8l.5-.1 .2 .3v.4l-.1 .2-.1 .1-.5-.1M208.1 179.2v1.5M209.5 179.8a.41 .41 0 0 1 .4-.1 .41 .41 0 0 1 .3 .3v.4a.41 .41 0 0 1-.4 .3 .41 .41 0 0 1-.4-.3zM210.8 179.8l.2-.1 .4 .1 .1 .9M212.2 179.7v1M212.6 179.7a.38 .38 0 0 0-.4 .3M213.8 179.8l-.5-.1-.2 .3v.4l.1 .2 .1 .1 .5-.1"/>
<path d="M213.8 179.2v1.5M184.2 180.5l.1 .1-.1 .1M184.2 180.5l-.1 .1 .1 .1M184.2 180.5v.2M195.1 180.5v.1v.1M195.1 180.5l-.1 .1 .1 .1M195.1 180.5v.2M203.3 180.2l.7-.2-.1-.2-.4-.1-.2 .2v.7l.2 .1 .4-.1M206.6 180l-.5 .1a.29 .29 0 0 0-.2 .3 .29 .29 0 0 0 .2 .3l.5-.1M211.5 180l-.5 .1a.29 .29 0 0 0-.2 .3 .29 .29 0 0 0 .2 .3l.5-.1M263.6 193.1h.5a.41 .41 0 0 0 .3-.4 .41 .41 0 0 0-.3-.4h-.5v1.5M263.9 193.1l.5 .7"/>
<path d="M265 193.3l.7-.2-.1-.2-.4-.1-.2 .2 .1 .7 .1 .1 .4-.1M266.2 192.8l.4 1 .3-1M267.5 193.6l.1 .1-.1 .1M267.5 193.6l-.1 .1 .1 .1M267.5 192.9v.1M267.5 193.6v.2M267.5 192.9h.1l-.1 .1M267.5 192.9h-.1l.1 .1M270 192.9l-.4-.1-.3 .3v.4l.1 .2 .2 .1 .4-.1M270 192.3v1.5M270.6 193.3l.7-.2v-.2l-.5-.1-.2 .2 .1 .7 .1 .1 .5-.1M271.8 192.8l.4 1 .4-1"/>
</g>
<g fill="none" stroke="#480000" stroke-width=".4">
<path d="M178.7 188.2h1.1M179.3 188.2l-.3 2M180.4 188.9l-.1 1.3M180.5 188.2l-.1 .1 .1 .1M180.5 188.2l.1 .1-.1 .1M180.5 188.2v.2M181.1 188.9h.7M181.5 188.2l-.3 1.7 .1 .2 .4 .1M182.6 188.2l-.2 1.7 .1 .2 .1 .1M183.4 189.5l1-.1-.1-.4-.2-.1-.5 .1-.2 .2-.1 .7 .1 .2 .2 .1 .6-.1M185.1 190l.1 .1-.1 .1M185.1 190l-.1 .1 .1 .1"/>
<path d="M185.1 190v.2M185.3 189l-.1 .2M185.3 189v.1l-.1 .1M185.3 189l-.1 .1v.1M187.8 188.5a.69 .69 0 0 1 1.1 0 1.67 1.67 0 0 1-.3 1.6l-.3 .1-.5-.1a1.5 1.5 0 0 1 0-1.6zM189.8 189l.2-.1 .6 .1 .2 .3-.1 .5a.66 .66 0 0 1-1 .3M189.8 188.9l-.2 2M191.5 189.5l1-.1-.1-.4-.6-.1-.3 .3-.1 .7 .1 .2 .2 .1 .6-.1M193.3 189.1a.49 .49 0 0 1 .9 .1l-.1 1M193.4 188.9l-.2 1.3M196.7 189.3h.7a.55 .55 0 0 0 .5-.5 .55 .55 0 0 0-.3-.6h-.8l-.3 2M198.5 189.5l1-.1v-.4l-.6-.1-.3 .3-.1 .7 .1 .2 .1 .1 .6-.1"/>
<path d="M201.3 189a.66 .66 0 0 0-1 .3l-.1 .5 .2 .3 .1 .1 .6-.1M201.4 188.2l-.3 2M202.2 189l.2-.1 .6 .1 .1 .2-.2 1M203 189.4h-.7a.4 .4 0 0 0-.3 .4 .4 .4 0 0 0 .3 .4l.6-.1M204.1 188.2l-.2 1.7 .1 .2 .2 .1M205.1 189l.2-.1 .5 .1 .2 .3-.1 .5a.66 .66 0 0 1-1 .3M205.2 188.2l-.3 2M206.9 189.1a.52 .52 0 0 1 .5-.2 .52 .52 0 0 1 .4 .4l-.1 .5a.55 .55 0 0 1-.5 .4 .55 .55 0 0 1-.5-.4l.1-.5zM208.7 189l.2-.1 .6 .1v.2l-.1 1M209.5 189.4h-.7a.4 .4 0 0 0-.3 .4 .4 .4 0 0 0 .2 .4l.7-.1M210.5 188.9l-.2 1.3M211.1 188.9a.59 .59 0 0 0-.6 .4"/>
<path d="M212.6 189a.66 .66 0 0 0-1 .3l-.1 .5 .2 .3 .2 .1 .6-.1M212.7 188.2l-.3 2M214.9 190.2l.3-2 .5 1.4 .8-1.4-.2 2M217.4 189l.2-.1 .5 .1 .1 .2-.1 1M218.2 189.4h-.7a.4 .4 0 0 0-.3 .4 .4 .4 0 0 0 .2 .4l.7-.1M219.2 188.9l-.2 1.3M219.3 188.2l-.1 .1v.1M219.3 188.2v.1l-.1 .1M219.3 188.2l-.1 .2M220.1 189.1a.49 .49 0 0 1 .9 .1l-.2 1M220.1 188.9l-.1 1.3M221.9 189l.2-.1 .6 .1 .1 .3v.5a.66 .66 0 0 1-1 .3"/>
<path d="M222 188.2l-.2 2M223.7 189.1a.52 .52 0 0 1 .6-.2 .52 .52 0 0 1 .4 .4l-.1 .5a.55 .55 0 0 1-.5 .4 .55 .55 0 0 1-.6-.4l.1-.5zM225.6 189l.2-.1 .5 .1 .1 .2-.1 1M226.4 189.4h-.7a.4 .4 0 0 0-.4 .4 .4 .4 0 0 0 .3 .4l.7-.1M227.4 188.9l-.2 1.3M227.9 188.9a.59 .59 0 0 0-.6 .4M229.5 189a.66 .66 0 0 0-1 .3l-.1 .5 .2 .3 .1 .1 .6-.1M229.6 188.2l-.3 2"/>
</g>
<use href="#words"/>
</svg>
